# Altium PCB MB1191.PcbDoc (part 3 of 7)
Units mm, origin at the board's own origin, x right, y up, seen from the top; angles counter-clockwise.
Board outline 130 x 80 mm, 8 copper layers (Top, F2, F3, F4, F5, F6, F7, Bottom), stack 1.115 mm thick; 360 components, 347 nets, 1451 pads, 1068 vias.

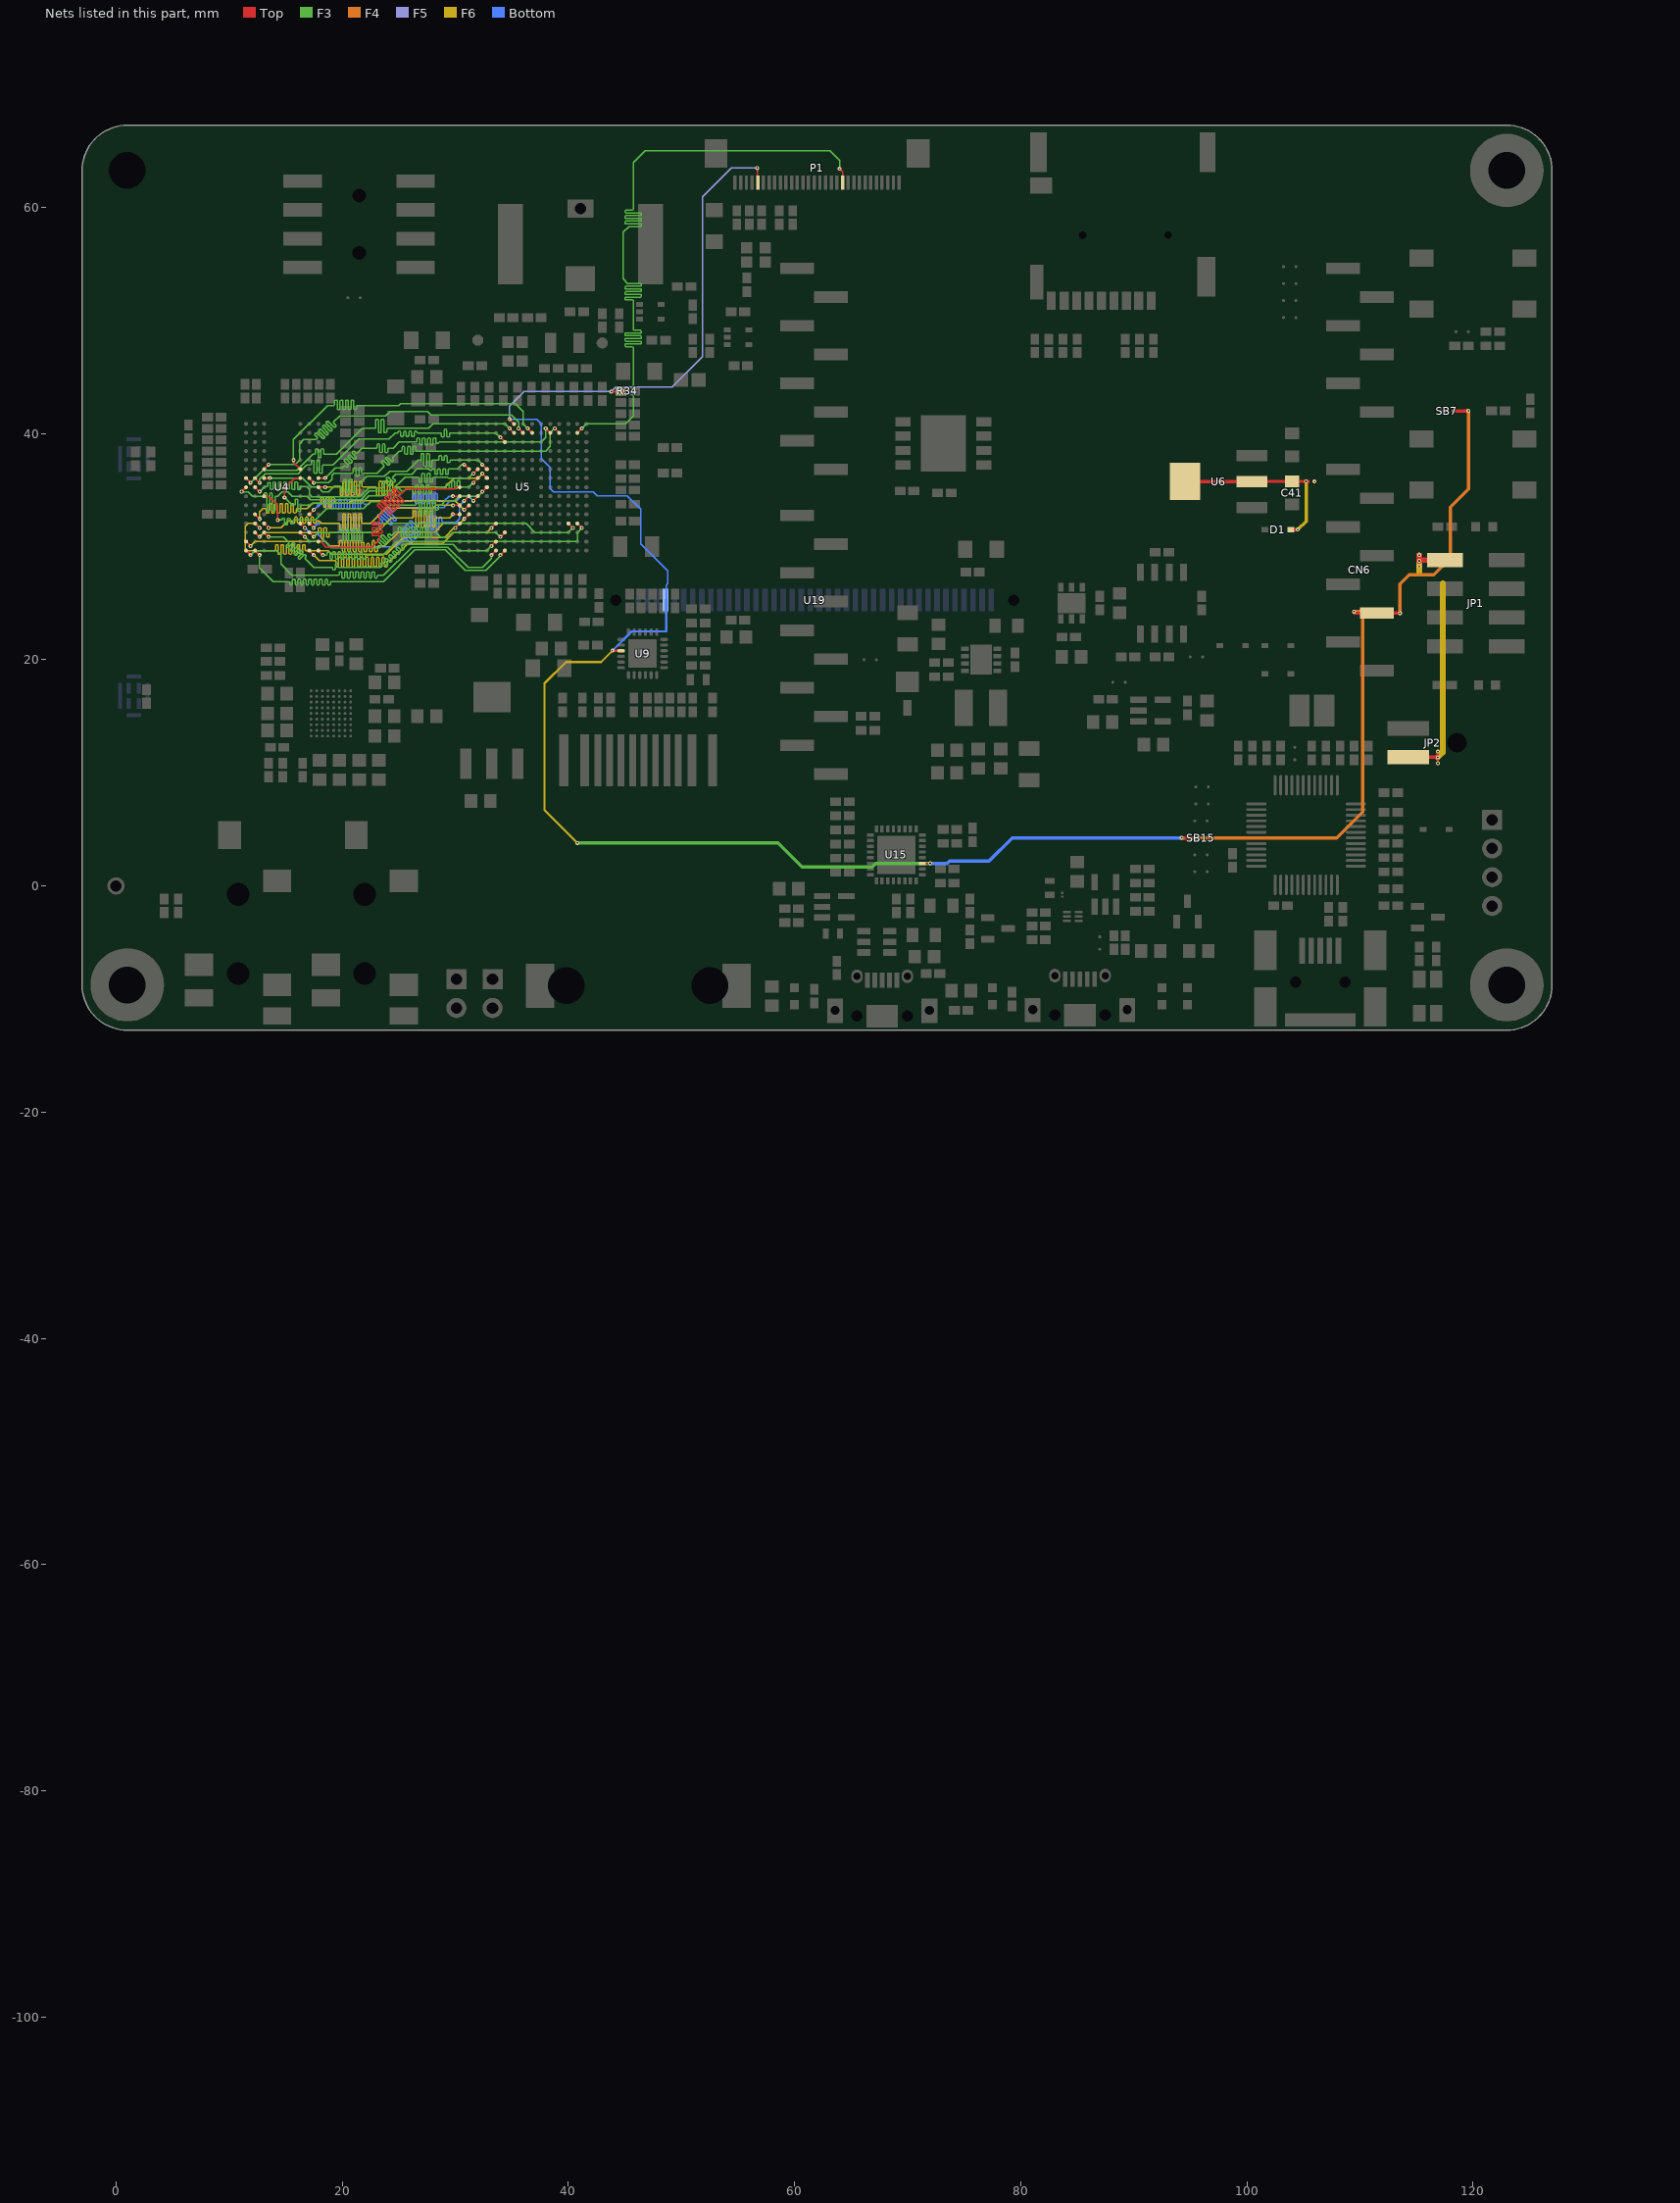
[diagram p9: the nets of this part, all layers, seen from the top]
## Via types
v1: diameter 0.35, hole 0.15, Top to Bottom, tented both sides, 1041 vias
v2: diameter 0.25, hole 0.1, Top to Bottom, tented both sides, 26 vias
v3: diameter 0.3, hole 0.1, Top to Bottom, tented both sides, 1 vias

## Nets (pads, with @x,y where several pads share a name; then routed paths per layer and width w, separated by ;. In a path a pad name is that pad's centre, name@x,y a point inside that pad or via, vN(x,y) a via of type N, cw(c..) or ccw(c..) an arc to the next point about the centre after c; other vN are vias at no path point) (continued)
DCMI_D7: P1.11 U5.B2 | length 74.9
  Top w0.12: U5.B2@40.8,40.05 v1(41.2,40.45) ; v1(64,63.4) 64.25,63.15 P1.11@64.25,62.175
  F3 w0.12: v1(41.2,40.45) 41.6,40.85 45.05,40.85 45.74,41.54 45.74,47.62 45.68,47.68 45.08,47.68 45.02,47.74 45.02,47.86 45.08,47.92 46.4,47.92 46.46,47.98 46.46,48.1 46.4,48.16 45.08,48.16 45.02,48.22 45.02,48.34 45.08,48.4 46.4,48.4 46.46,48.46 46.46,48.58 46.4,48.64 45.08,48.64 45.02,48.7 45.02,48.82 45.08,48.88 46.4,48.88 46.46,48.94 46.46,49.06 46.4,49.12 45.8,49.12 45.74,49.18 45.74,51.76 45.68,51.82 45.08,51.82 45.02,51.88 45.02,52 45.08,52.06 46.4,52.06 46.46,52.12 46.46,52.24 46.4,52.3 45.08,52.3 45.02,52.36 45.02,52.48 45.08,52.54 46.4,52.54 46.46,52.6 46.46,52.72 46.4,52.78 45.08,52.78 45.02,52.84 45.02,52.96 45.08,53.02 46.4,53.02 46.46,53.08 46.46,53.2 46.4,53.26 45.25,53.26 44.84,53.67 44.84,57.79 45.35,58.3 46.4,58.3 46.46,58.36 46.46,58.48 46.4,58.54 45.08,58.54 45.02,58.6 45.02,58.72 45.08,58.78 46.4,58.78 46.46,58.84 46.46,58.96 46.4,59.02 45.08,59.02 45.02,59.08 45.02,59.2 45.08,59.26 46.4,59.26 46.46,59.32 46.46,59.44 46.4,59.5 45.08,59.5 45.02,59.56 45.02,59.68 45.08,59.74 45.68,59.74 45.74,59.8 45.74,63.96 46.78,65 63.15,65 64,64.15 v1(64,63.4)
DCMI_NRST: CN6.3 P1.26 R34.1 SB7.1 SB15.2 U5.J1 U9.15 U15.27 U19.37 | length 221.2
  Top w0.12: v1(34.8,41.25) U5.J1@35.2,40.85 ; v1(56.71,63.47) 56.71,62.175 P1.26@56.75,62.175 ; U15.27@71.3,2 v1(72,2)
  Top w0.2: v1(43.8,43.7) 44.65,43.7 R34.1@44.65,43.75 ; v1(43.9,20.8) 43.9,20.789 U9.15@44.672,20.789
  Top w0.3: v1(94.25,4.25) SB15.2@95.4,4.25 ; v1(109.5,24.25) 109.5,24.12 CN6.3@111.5,24.12 113.57,24.12 v1(113.55,24.1) ; SB7.1@118.25,42 v1(119.6,42)
  F3 w0.3: v1(40.8,3.8) 58.55,3.8 60.68,1.67 66.87,1.67 67.2,2 v1(72,2)
  F4 w0.3: v1(94.25,4.25) 107.95,4.25 110.25,6.55 110.25,24.25 v1(109.5,24.25) ; v1(113.55,24.1) 113.55,26.7 114.35,27.5 116.55,27.5 118,28.95 118,33.5 119.6,35.1 v1(119.6,42)
  F5 w0.12: v1(34.8,41.25) 34.8,42.41 36.09,43.7 v1(43.8,43.7) 44.2,44.1 49.2,44.1 51.88,46.78 51.88,60.93 54.42,63.47 v1(56.71,63.47)
  F6 w0.2: v1(40.8,3.8) 37.9,6.7 37.9,17.9 39.8,19.8 42.9,19.8 v1(43.9,20.8)
  Bottom w0.12: v1(34.8,41.25) 37.2,41.25 37.6,40.85 37.6,37.8 38.4,37 38.4,35.15 38.7,34.85 42.2,34.85 42.55,34.5 45.2,34.5 46.4,33.3 46.4,30.25 48.804,27.846 48.804,27.148 ; U19.37@48.6,25.25 48.65,25.3 48.65,25.346 48.65,26.575 48.805,26.73 48.805,27.147
  Bottom w0.2: v1(43.9,20.8) 45.6,22.5 48.65,22.5 U19.37@48.65,25.3
  Bottom w0.3: v1(72,2) 73.5,2 73.7,2.2 77.2,2.2 79.25,4.25 v1(94.25,4.25)
E5V: C41.2 D1.1 JP1.1 JP2.2 U6.2 U6.4 | length 39.4
  Top w0.2: v1(116.89,11.375) v1@116.89,11.385 ; v1(116.9,11.875) 116.89,11.875 v1@116.89,11.385 ; v1(116.91,10.845) 116.91,11.385 v1@116.89,11.385
  Top w0.3: U6.4@94.55,35.75 U6.2@100.45,35.75 100.45,35.766 C41.2@104,35.766 v1(105.25,35.766) 105.434,35.766 ; D1.1@103.893,31.5 v1(104.5,31.5) ; 105.45,35.75 105.434,35.766 ; 105.45,35.766 105.434,35.766 ; JP2.2@114.3,11.385 v1@116.89,11.385
  Top w0.5: v1(115.25,28.75) 115.25,28.81 JP1.1@117.52,28.81 ; 115.25,29 v1(115.25,29.25)
  F6 w0.3: v1(104.5,31.5) 105.25,32.25 v1(105.25,35.766)
  F6 w0.5: 115.25,27.75 v1(115.25,28.25) v1(115.25,28.75) v1(115.25,29.25) ; v1(116.89,11.375) 117.325,11.81 117.325,26.75
  other v1: 106,35.75
FMC_A0: U4.G8 U5.D2 | length 33
  Top w0.12: U4.G8@17.1,36.05 v1(17.5,35.65) ; v1(38.8,40.45) U5.D2@39.2,40.05
  F3 w0.12: v1(17.5,35.65) 18.8,35.65 19.1,35.95 19.1,36.3 19.3,36.5 20.93,36.5 20.99,36.56 20.99,36.9 21.05,36.96 21.17,36.96 21.23,36.9 21.23,36.26 21.29,36.2 21.41,36.2 21.47,36.26 21.47,36.9 21.53,36.96 21.65,36.96 21.71,36.9 21.71,36.56 21.77,36.5 23.11,36.5 23.709,37.099 23.709,37.184 23.472,37.42 23.472,37.505 23.557,37.59 23.642,37.59 24.033,37.198 24.118,37.198 24.203,37.283 24.203,37.368 23.811,37.76 23.811,37.845 23.896,37.93 23.981,37.93 24.373,37.538 24.458,37.538 24.542,37.623 24.542,37.708 24.472,37.778 24.472,37.862 25.06,38.45 25.24,38.45 25.3,38.51 25.3,38.79 25.36,38.85 25.48,38.85 25.54,38.79 25.54,38.21 25.6,38.15 25.72,38.15 25.78,38.21 25.78,38.79 25.84,38.85 25.96,38.85 26.02,38.79 26.02,38.21 26.08,38.15 26.2,38.15 26.26,38.21 26.26,38.79 26.32,38.85 26.44,38.85 26.5,38.79 26.5,38.51 26.56,38.45 38,38.45 38.4,38.85 38.4,40.05 v1(38.8,40.45)
FMC_A1: U4.G9 U5.E2 | length 33.1
  Top w0.12: U4.G9@17.9,36.05 v1(18.5,36.05) ; v1(38,40.45) U5.E2@38.4,40.05
  F3 w0.12: v1(18.5,36.05) 19.4,36.95 20.01,36.95 20.206,37.146 20.291,37.146 20.387,37.051 20.472,37.051 20.557,37.136 20.557,37.221 20.198,37.579 20.198,37.664 20.283,37.748 20.368,37.748 20.726,37.39 20.811,37.39 20.896,37.475 20.896,37.56 20.538,37.918 20.538,38.003 20.623,38.088 20.708,38.088 21.066,37.73 21.15,37.73 21.235,37.815 21.235,37.9 20.877,38.258 20.877,38.342 20.962,38.427 21.047,38.427 21.225,38.25 21.31,38.25 21.76,38.7 23.02,38.7 23.08,38.76 23.08,39 23.14,39.06 23.26,39.06 23.32,39 23.32,38.35 23.38,38.29 23.5,38.29 23.56,38.35 23.56,39 23.62,39.06 23.74,39.06 23.8,39 23.8,38.35 23.86,38.29 23.98,38.29 24.04,38.35 24.04,38.64 24.1,38.7 24.51,38.7 25.06,39.25 26.55,39.25 26.61,39.31 26.61,39.56 26.67,39.62 26.79,39.62 26.85,39.56 26.85,39.05 26.91,38.99 27.03,38.99 27.09,39.05 27.09,39.56 27.15,39.62 27.27,39.62 27.33,39.56 27.33,39.05 27.39,38.99 27.51,38.99 27.57,39.05 27.57,39.56 27.63,39.62 27.75,39.62 27.81,39.56 27.81,39.05 27.87,38.99 27.99,38.99 28.05,39.05 28.05,39.56 28.11,39.62 28.23,39.62 28.29,39.56 28.29,39.18 28.35,39.12 28.47,39.12 28.53,39.18 28.53,39.19 28.59,39.25 37.6,39.25 38,39.65 v1(38,40.45)
FMC_A2: U4.F7 U5.G2 | length 33.1
  Top w0.12: v1(15.7,37.65) 15.7,37.45 U4.F7@16.3,36.85 ; v1(36.4,40.45) U5.G2@36.8,40.05
  F3 w0.12: v1(15.7,37.65) 15.7,39.45 18.72,42.47 19.28,42.47 19.34,42.53 19.34,42.88 19.4,42.94 19.52,42.94 19.58,42.88 19.58,42.16 19.64,42.1 19.76,42.1 19.82,42.16 19.82,42.88 19.88,42.94 20,42.94 20.06,42.88 20.06,42.16 20.12,42.1 20.24,42.1 20.3,42.16 20.3,42.88 20.36,42.94 20.48,42.94 20.54,42.88 20.54,42.16 20.6,42.1 20.72,42.1 20.78,42.16 20.78,42.88 20.84,42.94 20.96,42.94 21.02,42.88 21.02,42.16 21.08,42.1 21.2,42.1 21.26,42.16 21.26,42.41 21.32,42.47 24.98,42.47 25.16,42.65 35.31,42.65 36,41.96 36,40.85 v1(36.4,40.45)
FMC_A3: U4.F3 U5.H2 | length 33.1
  Top w0.12: U4.F3@13.1,36.85 v1(13.5,37.25) ; v1(35.6,40.45) U5.H2@36,40.05
  F3 w0.12: v1(13.5,37.25) 15.85,37.25 16.25,37.65 16.25,39.1 16.6,39.45 17.68,39.45 17.807,39.577 17.807,39.662 17.587,39.883 17.587,39.967 17.672,40.052 17.757,40.052 18.269,39.539 18.354,39.539 18.439,39.624 18.439,39.709 17.926,40.222 17.926,40.307 18.011,40.392 18.096,40.392 18.609,39.879 18.694,39.879 18.779,39.964 18.779,40.049 18.266,40.561 18.266,40.646 18.351,40.731 18.435,40.731 18.948,40.218 19.033,40.218 19.118,40.303 19.118,40.388 18.605,40.901 18.605,40.986 18.69,41.071 18.775,41.071 19.288,40.558 19.373,40.558 19.457,40.643 19.457,40.727 19.25,40.935 19.25,41.02 19.78,41.55 23.85,41.55 24.25,41.95 27.55,41.95 27.85,41.65 34.95,41.65 35.6,41 v1(35.6,40.45)
FMC_A4: U4.G1 U5.J2 | length 33.1
  Top w0.12: U4.G1@11.5,36.05 v1(11.9,35.65) ; v1(34.8,40.45) U5.J2@35.2,40.05
  F3 w0.12: v1(11.9,35.65) 13,36.75 16,36.75 17.4,38.15 17.58,38.15 17.64,38.21 17.64,38.6 17.7,38.66 17.82,38.66 17.88,38.6 17.88,37.92 17.94,37.86 18.06,37.86 18.12,37.92 18.12,38.6 18.18,38.66 18.3,38.66 18.36,38.6 18.36,38.21 18.42,38.15 19.5,38.15 21.8,40.45 22.92,40.45 22.98,40.51 22.98,41.18 23.04,41.24 23.16,41.24 23.22,41.18 23.22,40.12 23.28,40.06 23.4,40.06 23.46,40.12 23.46,41.18 23.52,41.24 23.64,41.24 23.7,41.18 23.7,40.12 23.76,40.06 23.88,40.06 23.94,40.12 23.94,40.39 24,40.45 27.65,40.45 28.05,40.85 34.4,40.85 v1(34.8,40.45)
FMC_A5: U4.G2 U5.K3 | length 33
  Top w0.12: U4.G2@12.3,36.05 v1(12.7,35.65) ; v1(34,39.65) U5.K3@34.4,39.25
  F3 w0.12: v1(12.7,35.65) 12.7,35.95 13.2,36.45 16.1,36.45 16.85,37.2 17.22,37.2 17.28,37.26 17.28,37.56 17.34,37.62 17.46,37.62 17.52,37.56 17.52,36.54 17.58,36.48 17.7,36.48 17.76,36.54 17.76,37.56 17.82,37.62 17.94,37.62 18,37.56 18,36.54 18.06,36.48 18.18,36.48 18.24,36.54 18.24,37.14 18.3,37.2 19.2,37.2 21.5,39.5 24.15,39.5 24.7,40.05 24.88,40.05 24.94,40.11 24.94,40.13 25,40.19 25.12,40.19 25.18,40.13 25.18,39.8 25.24,39.74 25.36,39.74 25.42,39.8 25.42,40.13 25.48,40.19 25.6,40.19 25.66,40.13 25.66,39.8 25.72,39.74 25.84,39.74 25.9,39.8 25.9,40.13 25.96,40.19 26.08,40.19 26.14,40.13 26.14,39.8 26.2,39.74 26.32,39.74 26.38,39.8 26.38,40.13 26.44,40.19 26.56,40.19 26.62,40.13 26.62,40.11 26.68,40.05 28.72,40.05 28.78,39.99 28.78,39.74 28.84,39.68 28.96,39.68 29.02,39.74 29.02,40.3 29.08,40.36 29.2,40.36 29.26,40.3 29.26,39.74 29.32,39.68 29.44,39.68 29.5,39.74 29.5,39.99 29.56,40.05 33.6,40.05 v1(34,39.65)
FMC_A6: U4.G3 U5.M6 | length 33
  Top w0.12: U4.G3@13.1,36.05 v1(13.6,36.05) ; v1(32.4,37.25) U5.M6@32.8,36.85
  F3 w0.12: v1(13.6,36.05) 16.5,36.05 17.3,35.25 17.9,35.25 18.3,34.85 18.8,34.85 19.32,35.37 19.86,35.37 19.92,35.31 19.92,34.84 19.98,34.78 20.1,34.78 20.16,34.84 20.16,35.92 20.22,35.98 20.34,35.98 20.4,35.92 20.4,34.84 20.46,34.78 20.58,34.78 20.64,34.84 20.64,35.92 20.7,35.98 20.82,35.98 20.88,35.92 20.88,34.84 20.94,34.78 21.06,34.78 21.12,34.84 21.12,35.31 21.18,35.37 21.36,35.37 22.19,36.2 23.75,36.2 24.2,36.65 25.75,36.65 26.75,37.65 26.93,37.65 26.99,37.71 26.99,38.15 27.05,38.21 27.17,38.21 27.23,38.15 27.23,37.15 27.29,37.09 27.41,37.09 27.47,37.15 27.47,38.15 27.53,38.21 27.65,38.21 27.71,38.15 27.71,37.15 27.77,37.09 27.89,37.09 27.95,37.15 27.95,37.59 28.01,37.65 28.51,37.65 28.57,37.71 28.57,37.96 28.63,38.02 28.75,38.02 28.81,37.96 28.81,37.69 28.87,37.63 28.99,37.63 29.05,37.69 29.05,37.96 29.11,38.02 29.23,38.02 29.29,37.96 29.29,37.48 29.35,37.42 29.47,37.42 29.53,37.48 29.53,37.59 29.59,37.65 32,37.65 v1(32.4,37.25)
FMC_A7: U4.H1 U5.N6 | length 33
  Top w0.12: v1(11.1,34.85) U4.H1@11.5,35.25 ; v1(31.6,36.45) U5.N6@32,36.85
  F3 w0.12: v1(11.1,34.85) 11.7,34.85 12.1,34.45 13.04,34.45 13.1,34.51 13.1,34.67 13.16,34.73 13.28,34.73 13.34,34.67 13.34,33.21 13.4,33.15 13.52,33.15 13.58,33.21 13.58,34.67 13.64,34.73 13.76,34.73 13.82,34.67 13.82,33.21 13.88,33.15 14,33.15 14.06,33.21 14.06,34.39 14.12,34.45 14.3,34.45 14.7,34.85 15.2,34.85 15.6,34.45 16.9,34.45 17.2,34.15 21.65,34.15 22.4,34.9 24.3,34.9 25.55,36.15 26.75,36.15 26.81,36.09 26.81,35.74 26.87,35.68 26.99,35.68 27.05,35.74 27.05,36.43 27.11,36.49 27.23,36.49 27.29,36.43 27.29,35.74 27.35,35.68 27.47,35.68 27.53,35.74 27.53,36.43 27.59,36.49 27.71,36.49 27.77,36.43 27.77,35.74 27.83,35.68 27.95,35.68 28.01,35.74 28.01,36.09 28.07,36.15 29.3,36.15 29.4,36.05 31.15,36.05 31.55,36.45 v1(31.6,36.45)
FMC_A8: U4.H2 U5.P6 | length 33.1
  Top w0.12: U4.H2@12.3,35.25 v1(12.7,34.85) ; v1(30.8,37.25) U5.P6@31.2,36.85
  F3 w0.12: v1(12.7,34.85) 13.17,35.32 13.35,35.32 13.41,35.38 13.41,35.61 13.47,35.67 13.59,35.67 13.65,35.61 13.65,35.1 13.71,35.04 13.83,35.04 13.89,35.1 13.89,35.65 13.95,35.71 14.07,35.71 14.13,35.65 14.13,35.1 14.19,35.04 14.31,35.04 14.37,35.1 14.37,35.65 14.43,35.71 14.55,35.71 14.61,35.65 14.61,35.15 14.67,35.09 14.79,35.09 14.85,35.15 14.85,35.65 14.91,35.71 15.03,35.71 15.09,35.65 15.09,35.15 15.15,35.09 15.27,35.09 15.33,35.15 15.33,35.65 15.39,35.71 15.51,35.71 15.57,35.65 15.57,35.1 15.63,35.04 15.75,35.04 15.81,35.1 15.81,35.65 15.87,35.71 15.99,35.71 16.05,35.65 16.05,35.1 16.11,35.04 16.23,35.04 16.29,35.1 16.29,35.26 16.35,35.32 16.83,35.32 17.1,35.05 17.1,34.65 17.35,34.4 21.55,34.4 22.35,35.2 23.55,35.2 23.737,35.387 23.737,35.472 23.59,35.62 23.59,35.704 23.675,35.789 23.76,35.789 24.188,35.36 24.273,35.36 24.358,35.445 24.358,35.53 23.931,35.957 23.931,36.042 24.016,36.127 24.101,36.127 24.528,35.7 24.613,35.7 24.698,35.785 24.698,35.869 24.501,36.066 24.501,36.151 24.75,36.4 26.15,36.4 26.6,36.85 27.65,36.85 27.77,36.73 27.89,36.73 28.01,36.85 28.13,36.85 28.19,36.79 28.19,36.45 28.25,36.39 28.37,36.39 28.43,36.45 28.43,36.79 28.49,36.85 28.61,36.85 28.67,36.79 28.67,36.45 28.73,36.39 28.85,36.39 28.91,36.45 28.91,36.79 28.97,36.85 29.09,36.85 29.15,36.79 29.15,36.45 29.21,36.39 29.33,36.39 29.39,36.45 29.39,36.79 29.45,36.85 30.2,36.85 30.6,37.25 v1(30.8,37.25)
FMC_A9: U4.J3 U5.M8 | length 33
  Top w0.12: U4.J3@13.1,34.45 13.5,34.45 14.3,33.65 v1(14.3,32.35) ; v1(32.4,34.85) U5.M8@32.8,35.25
  F3 w0.12: v1(14.3,32.35) 14.62,32.35 14.68,32.41 14.68,32.43 14.74,32.49 14.86,32.49 14.92,32.43 14.92,31.99 14.98,31.93 15.1,31.93 15.16,31.99 15.16,32.43 15.22,32.49 15.34,32.49 15.4,32.43 15.4,32.09 15.46,32.03 15.58,32.03 15.64,32.09 15.64,32.29 15.7,32.35 17.65,32.35 18.65,33.35 21.9,33.35 22.51,33.96 23.56,33.96 23.85,33.67 26.51,33.67 26.57,33.73 26.57,34.03 26.63,34.09 26.75,34.09 26.81,34.03 26.81,32.9 26.87,32.84 26.99,32.84 27.05,32.9 27.05,34.03 27.11,34.09 27.23,34.09 27.29,34.03 27.29,32.9 27.35,32.84 27.47,32.84 27.53,32.9 27.53,34.03 27.59,34.09 27.71,34.09 27.77,34.03 27.77,32.9 27.83,32.84 27.95,32.84 28.01,32.9 28.01,34.03 28.07,34.09 28.19,34.09 28.25,34.03 28.25,33.29 28.31,33.23 28.43,33.23 28.49,33.29 28.49,33.61 28.55,33.67 28.75,33.67 29.13,34.05 29.95,34.05 30.33,34.43 31.98,34.43 v1(32.4,34.85)
FMC_A10: U4.G7 U5.N7 | length 33
  Top w0.12: v1(14.9,34.35) 14.9,35.15 15.8,36.05 U4.G7@16.3,36.05 ; v1(31.6,35.65) U5.N7@32,36.05
  F3 w0.12: v1(14.9,34.35) 15.6,33.65 15.78,33.65 15.84,33.71 15.84,34.12 15.9,34.18 16.02,34.18 16.08,34.12 16.08,33.17 16.14,33.11 16.26,33.11 16.32,33.17 16.32,33.59 16.38,33.65 17.25,33.65 17.45,33.85 21.7,33.85 22.35,34.5 23.54,34.5 23.6,34.56 23.6,34.6 23.66,34.66 23.78,34.66 23.84,34.6 23.84,34.49 23.9,34.43 24.02,34.43 24.08,34.49 24.08,34.6 24.14,34.66 24.26,34.66 24.32,34.6 24.32,34.23 24.38,34.17 24.5,34.17 24.56,34.23 24.56,34.44 24.62,34.5 25.02,34.5 25.147,34.627 25.147,34.712 24.842,35.018 24.842,35.102 24.927,35.187 25.012,35.187 25.317,34.882 25.402,34.882 25.63,35.11 26.18,35.11 26.24,35.05 26.24,34.74 26.3,34.68 26.42,34.68 26.48,34.74 26.48,35.4 26.54,35.46 26.66,35.46 26.72,35.4 26.72,34.74 26.78,34.68 26.9,34.68 26.96,34.74 26.96,35.38 27.02,35.44 27.14,35.44 27.2,35.38 27.2,34.74 27.26,34.68 27.38,34.68 27.44,34.74 27.44,35.38 27.5,35.44 27.62,35.44 27.68,35.38 27.68,34.74 27.74,34.68 27.86,34.68 27.92,34.74 27.92,35.05 27.98,35.11 28.25,35.11 28.39,35.25 28.91,35.25 28.97,35.19 28.97,35.18 29.03,35.12 29.15,35.12 29.21,35.18 29.21,35.51 29.27,35.57 29.39,35.57 29.45,35.51 29.45,35.18 29.51,35.12 29.63,35.12 29.69,35.18 29.69,35.75 29.75,35.81 29.87,35.81 29.93,35.75 29.93,35.18 29.99,35.12 30.11,35.12 30.17,35.18 30.17,35.75 30.23,35.81 30.35,35.81 30.41,35.75 30.41,35.31 30.47,35.25 31.2,35.25 v1(31.6,35.65)
FMC_A11: U4.H9 U5.M7 | length 33.1
  Top w0.12: U4.H9@17.9,35.25 v1(18.5,35.25) ; v1(32.4,36.45) U5.M7@32.8,36.05
  F6 w0.12: v1(18.5,35.25) 19.78,35.25 19.84,35.19 19.84,34.59 19.9,34.53 20.02,34.53 20.08,34.59 20.08,35.69 20.14,35.75 20.26,35.75 20.32,35.69 20.32,34.59 20.38,34.53 20.5,34.53 20.56,34.59 20.56,35.69 20.62,35.75 20.74,35.75 20.8,35.69 20.8,34.59 20.86,34.53 20.98,34.53 21.04,34.59 21.04,35.69 21.1,35.75 21.22,35.75 21.28,35.69 21.28,34.59 21.34,34.53 21.46,34.53 21.52,34.59 21.52,35.69 21.58,35.75 21.7,35.75 21.76,35.69 21.76,35.31 21.82,35.25 22.97,35.25 23.03,35.19 23.03,34.59 23.09,34.53 23.21,34.53 23.27,34.59 23.27,35.72 23.33,35.78 23.45,35.78 23.51,35.72 23.51,34.59 23.57,34.53 23.69,34.53 23.75,34.59 23.75,35.72 23.81,35.78 23.93,35.78 23.99,35.72 23.99,34.59 24.05,34.53 24.17,34.53 24.23,34.59 24.23,35.72 24.29,35.78 24.41,35.78 24.47,35.72 24.47,34.59 24.53,34.53 24.65,34.53 24.71,34.59 24.71,35.19 24.77,35.25 29.1,35.25 29.9,36.05 32,36.05 v1(32.4,36.45)
FMC_D0: U4.R8 U5.L12 | length 33
  Top w0.12: U4.R8@17.1,29.65 v1(17.5,29.25) ; v1(33.2,31.65) U5.L12@33.6,32.05
  F6 w0.12: v1(17.5,29.25) 18,28.75 19.38,28.75 19.44,28.69 19.44,28.28 19.5,28.22 19.62,28.22 19.68,28.28 19.68,29 19.74,29.06 19.86,29.06 19.92,29 19.92,28.28 19.98,28.22 20.1,28.22 20.16,28.28 20.16,29 20.22,29.06 20.34,29.06 20.4,29 20.4,28.28 20.46,28.22 20.58,28.22 20.64,28.28 20.64,29 20.7,29.06 20.82,29.06 20.88,29 20.88,28.28 20.94,28.22 21.06,28.22 21.12,28.28 21.12,29 21.18,29.06 21.3,29.06 21.36,29 21.36,28.28 21.42,28.22 21.54,28.22 21.6,28.28 21.6,29 21.66,29.06 21.78,29.06 21.84,29 21.84,28.28 21.9,28.22 22.02,28.22 22.08,28.28 22.08,29 22.14,29.06 22.26,29.06 22.32,29 22.32,28.28 22.38,28.22 22.5,28.22 22.56,28.28 22.56,29 22.62,29.06 22.74,29.06 22.8,29 22.8,28.28 22.86,28.22 22.98,28.22 23.04,28.28 23.04,29 23.1,29.06 23.22,29.06 23.28,29 23.28,28.28 23.34,28.22 23.46,28.22 23.52,28.28 23.52,29 23.58,29.06 23.7,29.06 23.76,29 23.76,28.28 23.82,28.22 23.94,28.22 24,28.28 24,28.69 24.06,28.75 24.28,28.75 25.82,30.29 28.89,30.29 29.85,31.25 32.8,31.25 v1(33.2,31.65)
FMC_D1: U4.N7 U5.K13 | length 33
  Top w0.12: U4.N7@16.3,31.25 v1(16.7,30.85) ; v1(34,30.85) U5.K13@34.4,31.25
  F3 w0.12: v1(16.7,30.85) 17.1,30.45 18.5,30.45 19.04,29.91 23.33,29.91 23.48,30.06 23.48,30.144 23.117,30.507 23.117,30.592 23.202,30.677 23.287,30.677 23.765,30.199 23.85,30.199 23.935,30.283 23.935,30.368 23.456,30.847 23.456,30.931 23.541,31.016 23.626,31.016 24.104,30.538 24.189,30.538 24.274,30.623 24.274,30.708 24.052,30.93 24.052,31.015 24.137,31.099 24.222,31.099 24.328,30.993 24.413,30.993 24.71,31.29 24.91,31.29 24.97,31.35 24.97,31.65 25.03,31.71 25.15,31.71 25.21,31.65 25.21,30.88 25.27,30.82 25.39,30.82 25.45,30.88 25.45,31.65 25.51,31.71 25.63,31.71 25.69,31.65 25.69,30.88 25.75,30.82 25.87,30.82 25.93,30.88 25.93,31.65 25.99,31.71 26.11,31.71 26.17,31.65 26.17,30.88 26.23,30.82 26.35,30.82 26.41,30.88 26.41,31.65 26.47,31.71 26.59,31.71 26.65,31.65 26.65,30.88 26.71,30.82 26.83,30.82 26.89,30.88 26.89,31.65 26.95,31.71 27.07,31.71 27.13,31.65 27.13,30.88 27.19,30.82 27.31,30.82 27.37,30.88 27.37,31.65 27.43,31.71 27.55,31.71 27.61,31.65 27.61,30.88 27.67,30.82 27.79,30.82 27.85,30.88 27.85,31.23 27.91,31.29 28.23,31.29 28.72,30.8 29.3,30.8 29.75,31.25 33.6,31.25 v1(34,30.85)
FMC_D2: U4.R9 U5.B12 | length 33.1
  Top w0.12: U4.R9@17.9,29.65 v1(18.3,29.25) ; U5.B12@40.8,32.05 v1(41.2,31.65)
  F3 w0.12: v1(18.3,29.25) 18.62,29.25 18.68,29.31 18.68,29.47 18.74,29.53 18.86,29.53 18.92,29.47 18.92,28.97 18.98,28.91 19.1,28.91 19.16,28.97 19.16,29.47 19.22,29.53 19.34,29.53 19.4,29.47 19.4,28.97 19.46,28.91 19.58,28.91 19.64,28.97 19.64,29.47 19.7,29.53 19.82,29.53 19.88,29.47 19.88,28.97 19.94,28.91 20.06,28.91 20.12,28.97 20.12,29.47 20.18,29.53 20.3,29.53 20.36,29.47 20.36,28.97 20.42,28.91 20.54,28.91 20.6,28.97 20.6,29.47 20.66,29.53 20.78,29.53 20.84,29.47 20.84,28.97 20.9,28.91 21.02,28.91 21.08,28.97 21.08,29.47 21.14,29.53 21.26,29.53 21.32,29.47 21.32,28.97 21.38,28.91 21.5,28.91 21.56,28.97 21.56,29.47 21.62,29.53 21.74,29.53 21.8,29.47 21.8,28.97 21.86,28.91 21.98,28.91 22.04,28.97 22.04,29.19 22.1,29.25 23.62,29.25 24.82,30.45 40.75,30.45 40.8,30.5 40.8,31.25 v1(41.2,31.65)
FMC_D3: U4.N8 U5.C12 | length 33
  Top w0.12: U4.N8@17.1,31.25 v1(17.5,30.85) ; U5.C12@40,32.05 v1(40.4,31.65)
  F3 w0.12: v1(17.5,30.85) 17.9,31.25 19.81,31.25 19.87,31.31 19.87,31.51 19.93,31.57 20.05,31.57 20.11,31.51 20.11,30.55 20.17,30.49 20.29,30.49 20.35,30.55 20.35,31.51 20.41,31.57 20.53,31.57 20.59,31.51 20.59,30.55 20.65,30.49 20.77,30.49 20.83,30.55 20.83,31.51 20.89,31.57 21.01,31.57 21.07,31.51 21.07,30.55 21.13,30.49 21.25,30.49 21.31,30.55 21.31,31.51 21.37,31.57 21.49,31.57 21.55,31.51 21.55,30.55 21.61,30.49 21.73,30.49 21.79,30.55 21.79,31.19 21.85,31.25 22.76,31.25 23.56,32.05 36.25,32.05 37.05,31.25 40,31.25 v1(40.4,31.65)
FMC_D4: U4.P9 U5.R8 | length 33.1
  Top w0.12: U4.P9@17.9,30.45 18.1,30.45 18.6,29.95 22.6,29.95 23.3,30.65 23.3,30.9 23.24,30.96 22.72,30.96 22.66,31.02 22.66,31.14 22.72,31.2 23.51,31.2 23.57,31.26 23.57,31.38 23.51,31.44 22.72,31.44 22.66,31.5 22.66,31.62 22.72,31.68 23.52,31.68 23.58,31.74 23.58,31.86 23.52,31.92 22.72,31.92 22.66,31.98 22.66,32.1 22.72,32.16 23.24,32.16 23.3,32.22 23.3,32.75 23.598,33.048 23.598,33.133 23.122,33.609 23.122,33.694 23.207,33.778 23.291,33.778 24.225,32.845 24.31,32.845 24.395,32.93 24.395,33.015 23.461,33.948 23.461,34.033 23.546,34.118 23.631,34.118 24.564,33.185 24.649,33.185 24.734,33.269 24.734,33.354 23.801,34.288 23.801,34.372 23.885,34.457 23.97,34.457 24.904,33.524 24.988,33.524 25.073,33.609 25.073,33.694 24.14,34.627 24.14,34.712 24.225,34.797 24.31,34.797 25.243,33.863 25.328,33.863 25.413,33.948 25.413,34.033 24.479,34.966 24.479,35.051 24.564,35.136 24.649,35.136 25.125,34.66 25.21,34.66 25.65,35.1 29.95,35.1 30.1,35.25 U5.R8@30.4,35.25
FMC_D5: U4.M8 U5.N9 | length 33.1
  Top w0.12: U4.M8@17.1,32.05 17.483,31.667 v1(17.466,31.65) ; v1(31.6,34.05) U5.N9@32,34.45
  Bottom w0.12: v1(17.466,31.65) 17.866,32.05 19.74,32.05 19.8,31.99 19.8,31.39 19.86,31.33 19.98,31.33 20.04,31.39 20.04,32.56 20.1,32.62 20.22,32.62 20.28,32.56 20.28,31.39 20.34,31.33 20.46,31.33 20.52,31.39 20.52,32.56 20.58,32.62 20.7,32.62 20.76,32.56 20.76,31.39 20.82,31.33 20.94,31.33 21,31.39 21,32.56 21.06,32.62 21.18,32.62 21.24,32.56 21.24,31.39 21.3,31.33 21.42,31.33 21.48,31.39 21.48,32.56 21.54,32.62 21.66,32.62 21.72,32.56 21.72,32.11 21.78,32.05 23.45,32.05 23.58,32.18 23.58,32.265 23.156,32.689 23.156,32.774 23.241,32.859 23.326,32.859 24.259,31.926 24.344,31.926 24.429,32.01 24.429,32.095 23.495,33.029 23.495,33.114 23.58,33.198 23.665,33.198 24.598,32.265 24.683,32.265 24.768,32.35 24.768,32.435 23.835,33.368 23.835,33.453 23.92,33.538 24.004,33.538 24.429,33.114 24.514,33.114 24.86,33.46 28.97,33.46 29.56,34.05 30.1,34.05 30.5,34.45 31.2,34.45 v1(31.6,34.05)
FMC_D6: U4.M7 U5.P9 | length 33
  Top w0.12: U4.M7@16.3,32.05 v1(16.7,31.65) ; v1(30.8,34.05) U5.P9@31.2,34.45
  Bottom w0.12: v1(16.7,31.65) 17.1,31.25 17.7,31.25 18.97,29.98 24.75,29.98 25.53,30.76 25.615,30.76 26.039,30.336 26.124,30.336 26.209,30.42 26.209,30.505 25.275,31.439 25.275,31.524 25.36,31.608 25.445,31.608 26.378,30.675 26.463,30.675 26.548,30.76 26.548,30.845 25.615,31.778 25.615,31.863 25.7,31.948 25.784,31.948 26.718,31.014 26.803,31.014 26.888,31.099 26.888,31.184 25.954,32.118 25.954,32.202 26.039,32.287 26.124,32.287 26.548,31.863 26.633,31.863 26.93,32.16 27.3,32.16 27.36,32.1 27.36,31.55 27.42,31.49 27.54,31.49 27.6,31.55 27.6,32.63 27.66,32.69 27.78,32.69 27.84,32.63 27.84,31.55 27.9,31.49 28.02,31.49 28.08,31.55 28.08,32.63 28.14,32.69 28.26,32.69 28.32,32.63 28.32,31.55 28.38,31.49 28.5,31.49 28.56,31.55 28.56,32.56 28.62,32.62 28.74,32.62 28.8,32.56 28.8,32.22 28.86,32.16 30.09,32.16 30.37,32.44 30.37,33.62 v1(30.8,34.05)
FMC_D7: U4.L8 U5.R9 | length 33.1
  Top w0.12: U4.L8@17.1,32.85 v1(17.5,33.25) ; v1(29.8,34.45) U5.R9@30.4,34.45
  Bottom w0.12: v1(17.5,33.25) 18.01,33.76 18.21,33.76 18.27,33.82 18.27,34.11 18.33,34.17 18.45,34.17 18.51,34.11 18.51,33.42 18.57,33.36 18.69,33.36 18.75,33.42 18.75,34.11 18.81,34.17 18.93,34.17 18.99,34.11 18.99,33.42 19.05,33.36 19.17,33.36 19.23,33.42 19.23,34.11 19.29,34.17 19.41,34.17 19.47,34.11 19.47,33.42 19.53,33.36 19.65,33.36 19.71,33.42 19.71,34.11 19.77,34.17 19.89,34.17 19.95,34.11 19.95,33.42 20.01,33.36 20.13,33.36 20.19,33.42 20.19,34.11 20.25,34.17 20.37,34.17 20.43,34.11 20.43,33.42 20.49,33.36 20.61,33.36 20.67,33.42 20.67,34.11 20.73,34.17 20.85,34.17 20.91,34.11 20.91,33.42 20.97,33.36 21.09,33.36 21.15,33.42 21.15,34.11 21.21,34.17 21.33,34.17 21.39,34.11 21.39,33.42 21.45,33.36 21.57,33.36 21.63,33.42 21.63,34.11 21.69,34.17 21.81,34.17 21.87,34.11 21.87,33.82 21.93,33.76 22.36,33.76 22.6,34 26.19,34 26.25,34.06 26.25,34.66 26.31,34.72 26.43,34.72 26.49,34.66 26.49,33.86 26.55,33.8 26.67,33.8 26.73,33.86 26.73,34.66 26.79,34.72 26.91,34.72 26.97,34.66 26.97,33.86 27.03,33.8 27.15,33.8 27.21,33.86 27.21,34.66 27.27,34.72 27.39,34.72 27.45,34.66 27.45,33.86 27.51,33.8 27.63,33.8 27.69,33.86 27.69,34.66 27.75,34.72 27.87,34.72 27.93,34.66 27.93,33.86 27.99,33.8 28.11,33.8 28.17,33.86 28.17,34.66 28.23,34.72 28.35,34.72 28.41,34.66 28.41,34.06 28.47,34 29,34 29.45,34.45 v1(29.8,34.45)
FMC_D8: U4.L2 U5.P10 | length 33.1
  Top w0.12: U4.L2@12.3,32.85 v1(12.7,32.45) ; v1(30.8,33.25) U5.P10@31.2,33.65
  F6 w0.12: v1(12.7,32.45) 12.7,33.04 13.01,33.35 13.23,33.35 13.29,33.29 13.29,33.01 13.35,32.95 13.47,32.95 13.53,33.01 13.53,33.74 13.59,33.8 13.71,33.8 13.77,33.74 13.77,33.01 13.83,32.95 13.95,32.95 14.01,33.01 14.01,33.74 14.07,33.8 14.19,33.8 14.25,33.74 14.25,33.01 14.31,32.95 14.43,32.95 14.49,33.01 14.49,33.74 14.55,33.8 14.67,33.8 14.73,33.74 14.73,33.01 14.79,32.95 14.91,32.95 14.97,33.01 14.97,33.74 15.03,33.8 15.15,33.8 15.21,33.74 15.21,33.01 15.27,32.95 15.39,32.95 15.45,33.01 15.45,33.74 15.51,33.8 15.63,33.8 15.69,33.74 15.69,33.01 15.75,32.95 15.87,32.95 15.93,33.01 15.93,33.29 15.99,33.35 16.89,33.35 17.37,33.83 18.06,33.83 18.12,33.89 18.12,34.28 18.18,34.34 18.3,34.34 18.36,34.28 18.36,33.54 18.42,33.48 18.54,33.48 18.6,33.54 18.6,34.28 18.66,34.34 18.78,34.34 18.84,34.28 18.84,33.54 18.9,33.48 19.02,33.48 19.08,33.54 19.08,34.28 19.14,34.34 19.26,34.34 19.32,34.28 19.32,33.89 19.38,33.83 20.61,33.83 20.83,34.05 30,34.05 v1(30.8,33.25)
FMC_D9: U4.M3 U5.R10 | length 33
  Top w0.12: U4.M3@13.1,32.05 v1(13.5,31.65) ; v1(29.8,33.65) U5.R10@30.4,33.65
  F6 w0.12: v1(13.5,31.65) 14.6,31.65 15.23,32.28 15.49,32.28 15.55,32.22 15.55,32.13 15.61,32.07 15.73,32.07 15.79,32.13 15.79,32.55 15.85,32.61 15.97,32.61 16.03,32.55 16.03,32.13 16.09,32.07 16.21,32.07 16.27,32.13 16.27,32.55 16.33,32.61 16.45,32.61 16.51,32.55 16.51,32.13 16.57,32.07 16.69,32.07 16.75,32.13 16.75,32.55 16.81,32.61 16.93,32.61 16.99,32.55 16.99,32.13 17.05,32.07 17.17,32.07 17.23,32.13 17.23,32.55 17.29,32.61 17.41,32.61 17.47,32.55 17.47,32.13 17.53,32.07 17.65,32.07 17.71,32.13 17.71,32.22 17.77,32.28 17.95,32.28 18.18,32.05 19.74,32.05 19.8,31.99 19.8,31.55 19.86,31.49 19.98,31.49 20.04,31.55 20.04,32.82 20.1,32.88 20.22,32.88 20.28,32.82 20.28,31.55 20.34,31.49 20.46,31.49 20.52,31.55 20.52,32.82 20.58,32.88 20.7,32.88 20.76,32.82 20.76,31.55 20.82,31.49 20.94,31.49 21,31.55 21,32.82 21.06,32.88 21.18,32.88 21.24,32.82 21.24,31.55 21.3,31.49 21.42,31.49 21.48,31.55 21.48,32.82 21.54,32.88 21.66,32.88 21.72,32.82 21.72,32.11 21.78,32.05 22.53,32.05 23.877,33.397 28.047,33.397 28.3,33.65 v1(29.8,33.65)
FMC_D10: U4.M2 U5.R12 | length 33.1
  Top w0.12: U4.M2@12.3,32.05 v1(12.7,31.65) ; v1(30,31.65) U5.R12@30.4,32.05
  F6 w0.12: v1(12.7,31.65) 12.3,32.05 11.7,32.05 11.45,31.8 11.45,29.8 11.6,29.65 14.04,29.65 14.1,29.71 14.1,30.11 14.16,30.17 14.28,30.17 14.34,30.11 14.34,29.38 14.4,29.32 14.52,29.32 14.58,29.38 14.58,30.11 14.64,30.17 14.76,30.17 14.82,30.11 14.82,29.38 14.88,29.32 15,29.32 15.06,29.38 15.06,30.11 15.12,30.17 15.24,30.17 15.3,30.11 15.3,29.38 15.36,29.32 15.48,29.32 15.54,29.38 15.54,30.11 15.6,30.17 15.72,30.17 15.78,30.11 15.78,29.38 15.84,29.32 15.96,29.32 16.02,29.38 16.02,30.11 16.08,30.17 16.2,30.17 16.26,30.11 16.26,29.38 16.32,29.32 16.44,29.32 16.5,29.38 16.5,30.11 16.56,30.17 16.68,30.17 16.74,30.11 16.74,29.71 16.8,29.65 18.74,29.65 19.07,29.32 23.9,29.32 25.4,30.82 29.07,30.82 29.9,31.65 v1(30,31.65)
FMC_D11: U4.P1 U5.P11 | length 33.1
  Top w0.12: U4.P1@11.5,30.45 v1(11.9,30.05) ; v1(30.8,32.45) U5.P11@31.2,32.85
  F6 w0.12: v1(11.9,30.05) 12.3,30.45 18.5,30.45 18.9,30.05 19.71,30.05 19.77,30.11 19.77,30.47 19.83,30.53 19.95,30.53 20.01,30.47 20.01,29.62 20.07,29.56 20.19,29.56 20.25,29.62 20.25,30.47 20.31,30.53 20.43,30.53 20.49,30.47 20.49,29.62 20.55,29.56 20.67,29.56 20.73,29.62 20.73,30.47 20.79,30.53 20.91,30.53 20.97,30.47 20.97,29.62 21.03,29.56 21.15,29.56 21.21,29.62 21.21,30.47 21.27,30.53 21.39,30.53 21.45,30.47 21.45,29.62 21.51,29.56 21.63,29.56 21.69,29.62 21.69,30.32 21.75,30.38 21.87,30.38 21.93,30.32 21.93,29.62 21.99,29.56 22.11,29.56 22.17,29.62 22.17,30.21 22.23,30.27 22.35,30.27 22.41,30.21 22.41,29.62 22.47,29.56 22.59,29.56 22.65,29.62 22.65,30.47 22.71,30.53 22.83,30.53 22.89,30.47 22.89,29.62 22.95,29.56 23.07,29.56 23.13,29.62 23.13,29.99 23.19,30.05 23.73,30.05 24.98,31.3 28.21,31.3 28.96,32.05 30.4,32.05 v1(30.8,32.45)
FMC_D12: U4.N2 U5.R11 | length 33.1
  Top w0.12: U4.N2@12.3,31.25 v1(12.7,30.85) ; v1(29.8,32.85) U5.R11@30.4,32.85
  F6 w0.12: v1(12.7,30.85) 13.1,31.25 17.84,31.25 17.9,31.31 17.9,31.61 17.96,31.67 18.08,31.67 18.14,31.61 18.14,30.75 18.2,30.69 18.32,30.69 18.38,30.75 18.38,31.61 18.44,31.67 18.56,31.67 18.62,31.61 18.62,30.91 18.68,30.85 18.8,30.85 18.86,30.91 18.86,31.19 18.92,31.25 23.05,31.25 24.35,32.55 26.23,32.55 26.29,32.61 26.29,33.09 26.35,33.15 26.47,33.15 26.53,33.09 26.53,31.79 26.59,31.73 26.71,31.73 26.77,31.79 26.77,33.09 26.83,33.15 26.95,33.15 27.01,33.09 27.01,31.79 27.07,31.73 27.19,31.73 27.25,31.79 27.25,33.09 27.31,33.15 27.43,33.15 27.49,33.09 27.49,31.79 27.55,31.73 27.67,31.73 27.73,31.79 27.73,33.09 27.79,33.15 27.91,33.15 27.97,33.09 27.97,31.79 28.03,31.73 28.15,31.73 28.21,31.79 28.21,32.49 28.27,32.55 29.5,32.55 v1(29.8,32.85)
FMC_D13: U4.R1 U5.L15 | length 33.2
  Top w0.12: U4.R1@11.5,29.65 v1(11.9,29.25) ; v1(33.2,29.25) U5.L15@33.6,29.65
  F3 w0.12: v1(11.9,29.25) 12.3,29.65 14.22,29.65 14.58,29.29 14.58,28.45 15.56,27.47 19.69,27.47 19.75,27.53 19.75,27.72 19.81,27.78 19.93,27.78 19.99,27.72 19.99,27.28 20.05,27.22 20.17,27.22 20.23,27.28 20.23,27.72 20.29,27.78 20.41,27.78 20.47,27.72 20.47,27.28 20.53,27.22 20.65,27.22 20.71,27.28 20.71,27.72 20.77,27.78 20.89,27.78 20.95,27.72 20.95,27.28 21.01,27.22 21.13,27.22 21.19,27.28 21.19,27.72 21.25,27.78 21.37,27.78 21.43,27.72 21.43,27.28 21.49,27.22 21.61,27.22 21.67,27.28 21.67,27.72 21.73,27.78 21.85,27.78 21.91,27.72 21.91,27.28 21.97,27.22 22.09,27.22 22.15,27.28 22.15,27.72 22.21,27.78 22.33,27.78 22.39,27.72 22.39,27.28 22.45,27.22 22.57,27.22 22.63,27.28 22.63,27.72 22.69,27.78 22.81,27.78 22.87,27.72 22.87,27.28 22.93,27.22 23.05,27.22 23.11,27.28 23.11,27.41 23.17,27.47 23.67,27.47 26.15,29.95 29.35,29.95 31.15,28.15 32.4,28.15 33.2,28.95 v1(33.2,29.25)
FMC_D14: U4.N3 U5.L14 | length 33.2
  Top w0.12: U4.N3@13.1,31.25 v1(13.5,30.85) ; v1(33.2,30.05) U5.L14@33.6,30.45
  F3 w0.12: v1(13.5,30.85) 14.8,30.85 15.277,30.373 15.277,30.288 15.076,30.086 15.076,30.001 15.161,29.916 15.245,29.916 15.636,30.307 15.721,30.307 15.806,30.222 15.806,30.138 15.415,29.747 15.415,29.662 15.5,29.577 15.585,29.577 15.976,29.968 16.061,29.968 16.146,29.883 16.146,29.798 15.755,29.407 15.755,29.322 15.839,29.238 15.924,29.238 16.315,29.629 16.4,29.629 16.485,29.544 16.485,29.459 16.094,29.068 16.094,28.983 16.179,28.898 16.264,28.898 16.655,29.289 16.739,29.289 16.824,29.204 16.824,29.119 16.72,29.015 16.72,28.93 17.49,28.16 19.09,28.16 19.15,28.1 19.15,28.02 19.21,27.96 19.33,27.96 19.39,28.02 19.39,28.47 19.45,28.53 19.57,28.53 19.63,28.47 19.63,28.22 19.69,28.16 23.36,28.16 23.491,28.291 23.491,28.376 23.446,28.42 23.446,28.505 23.531,28.59 23.616,28.59 23.894,28.312 23.978,28.312 24.063,28.397 24.063,28.482 23.786,28.759 23.786,28.844 23.871,28.929 23.956,28.929 24.233,28.652 24.318,28.652 24.403,28.736 24.403,28.821 24.125,29.099 24.125,29.184 24.21,29.268 24.295,29.268 24.572,28.991 24.657,28.991 24.742,29.076 24.742,29.161 24.465,29.438 24.465,29.523 24.55,29.608 24.634,29.608 24.912,29.33 24.997,29.33 25.082,29.415 25.082,29.5 24.804,29.778 24.804,29.862 24.889,29.947 24.974,29.947 25.251,29.67 25.336,29.67 25.421,29.755 25.421,29.84 25.273,29.988 25.273,30.073 25.4,30.2 29.8,30.2 30.35,29.65 32.8,29.65 v1(33.2,30.05)
FMC_D15: U4.R2 U5.K15 | length 33
  Top w0.12: U4.R2@12.3,29.65 v1(12.7,29.25) ; v1(34,29.25) U5.K15@34.4,29.65
  F3 w0.12: v1(12.7,29.25) 12.7,28.11 13.91,26.9 15.3,26.9 15.36,26.84 15.36,26.67 15.42,26.61 15.54,26.61 15.6,26.67 15.6,27.05 15.66,27.11 15.78,27.11 15.84,27.05 15.84,26.67 15.9,26.61 16.02,26.61 16.08,26.67 16.08,27.05 16.14,27.11 16.26,27.11 16.32,27.05 16.32,26.67 16.38,26.61 16.5,26.61 16.56,26.67 16.56,27.05 16.62,27.11 16.74,27.11 16.8,27.05 16.8,26.67 16.86,26.61 16.98,26.61 17.04,26.67 17.04,27.05 17.1,27.11 17.22,27.11 17.28,27.05 17.28,26.67 17.34,26.61 17.46,26.61 17.52,26.67 17.52,27.05 17.58,27.11 17.7,27.11 17.76,27.05 17.76,26.67 17.82,26.61 17.94,26.61 18,26.67 18,27.05 18.06,27.11 18.18,27.11 18.24,27.05 18.24,26.67 18.3,26.61 18.42,26.61 18.48,26.67 18.48,27.05 18.54,27.11 18.66,27.11 18.72,27.05 18.72,26.67 18.78,26.61 18.9,26.61 18.96,26.67 18.96,26.84 19.02,26.9 23.65,26.9 26.45,29.7 29.1,29.7 30.9,27.9 32.7,27.9 34,29.2 v1(34,29.25)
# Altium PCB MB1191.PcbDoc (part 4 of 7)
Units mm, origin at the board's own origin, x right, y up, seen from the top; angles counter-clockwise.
Board outline 130 x 80 mm, 8 copper layers (Top, F2, F3, F4, F5, F6, F7, Bottom), stack 1.115 mm thick; 360 components, 347 nets, 1451 pads, 1068 vias.

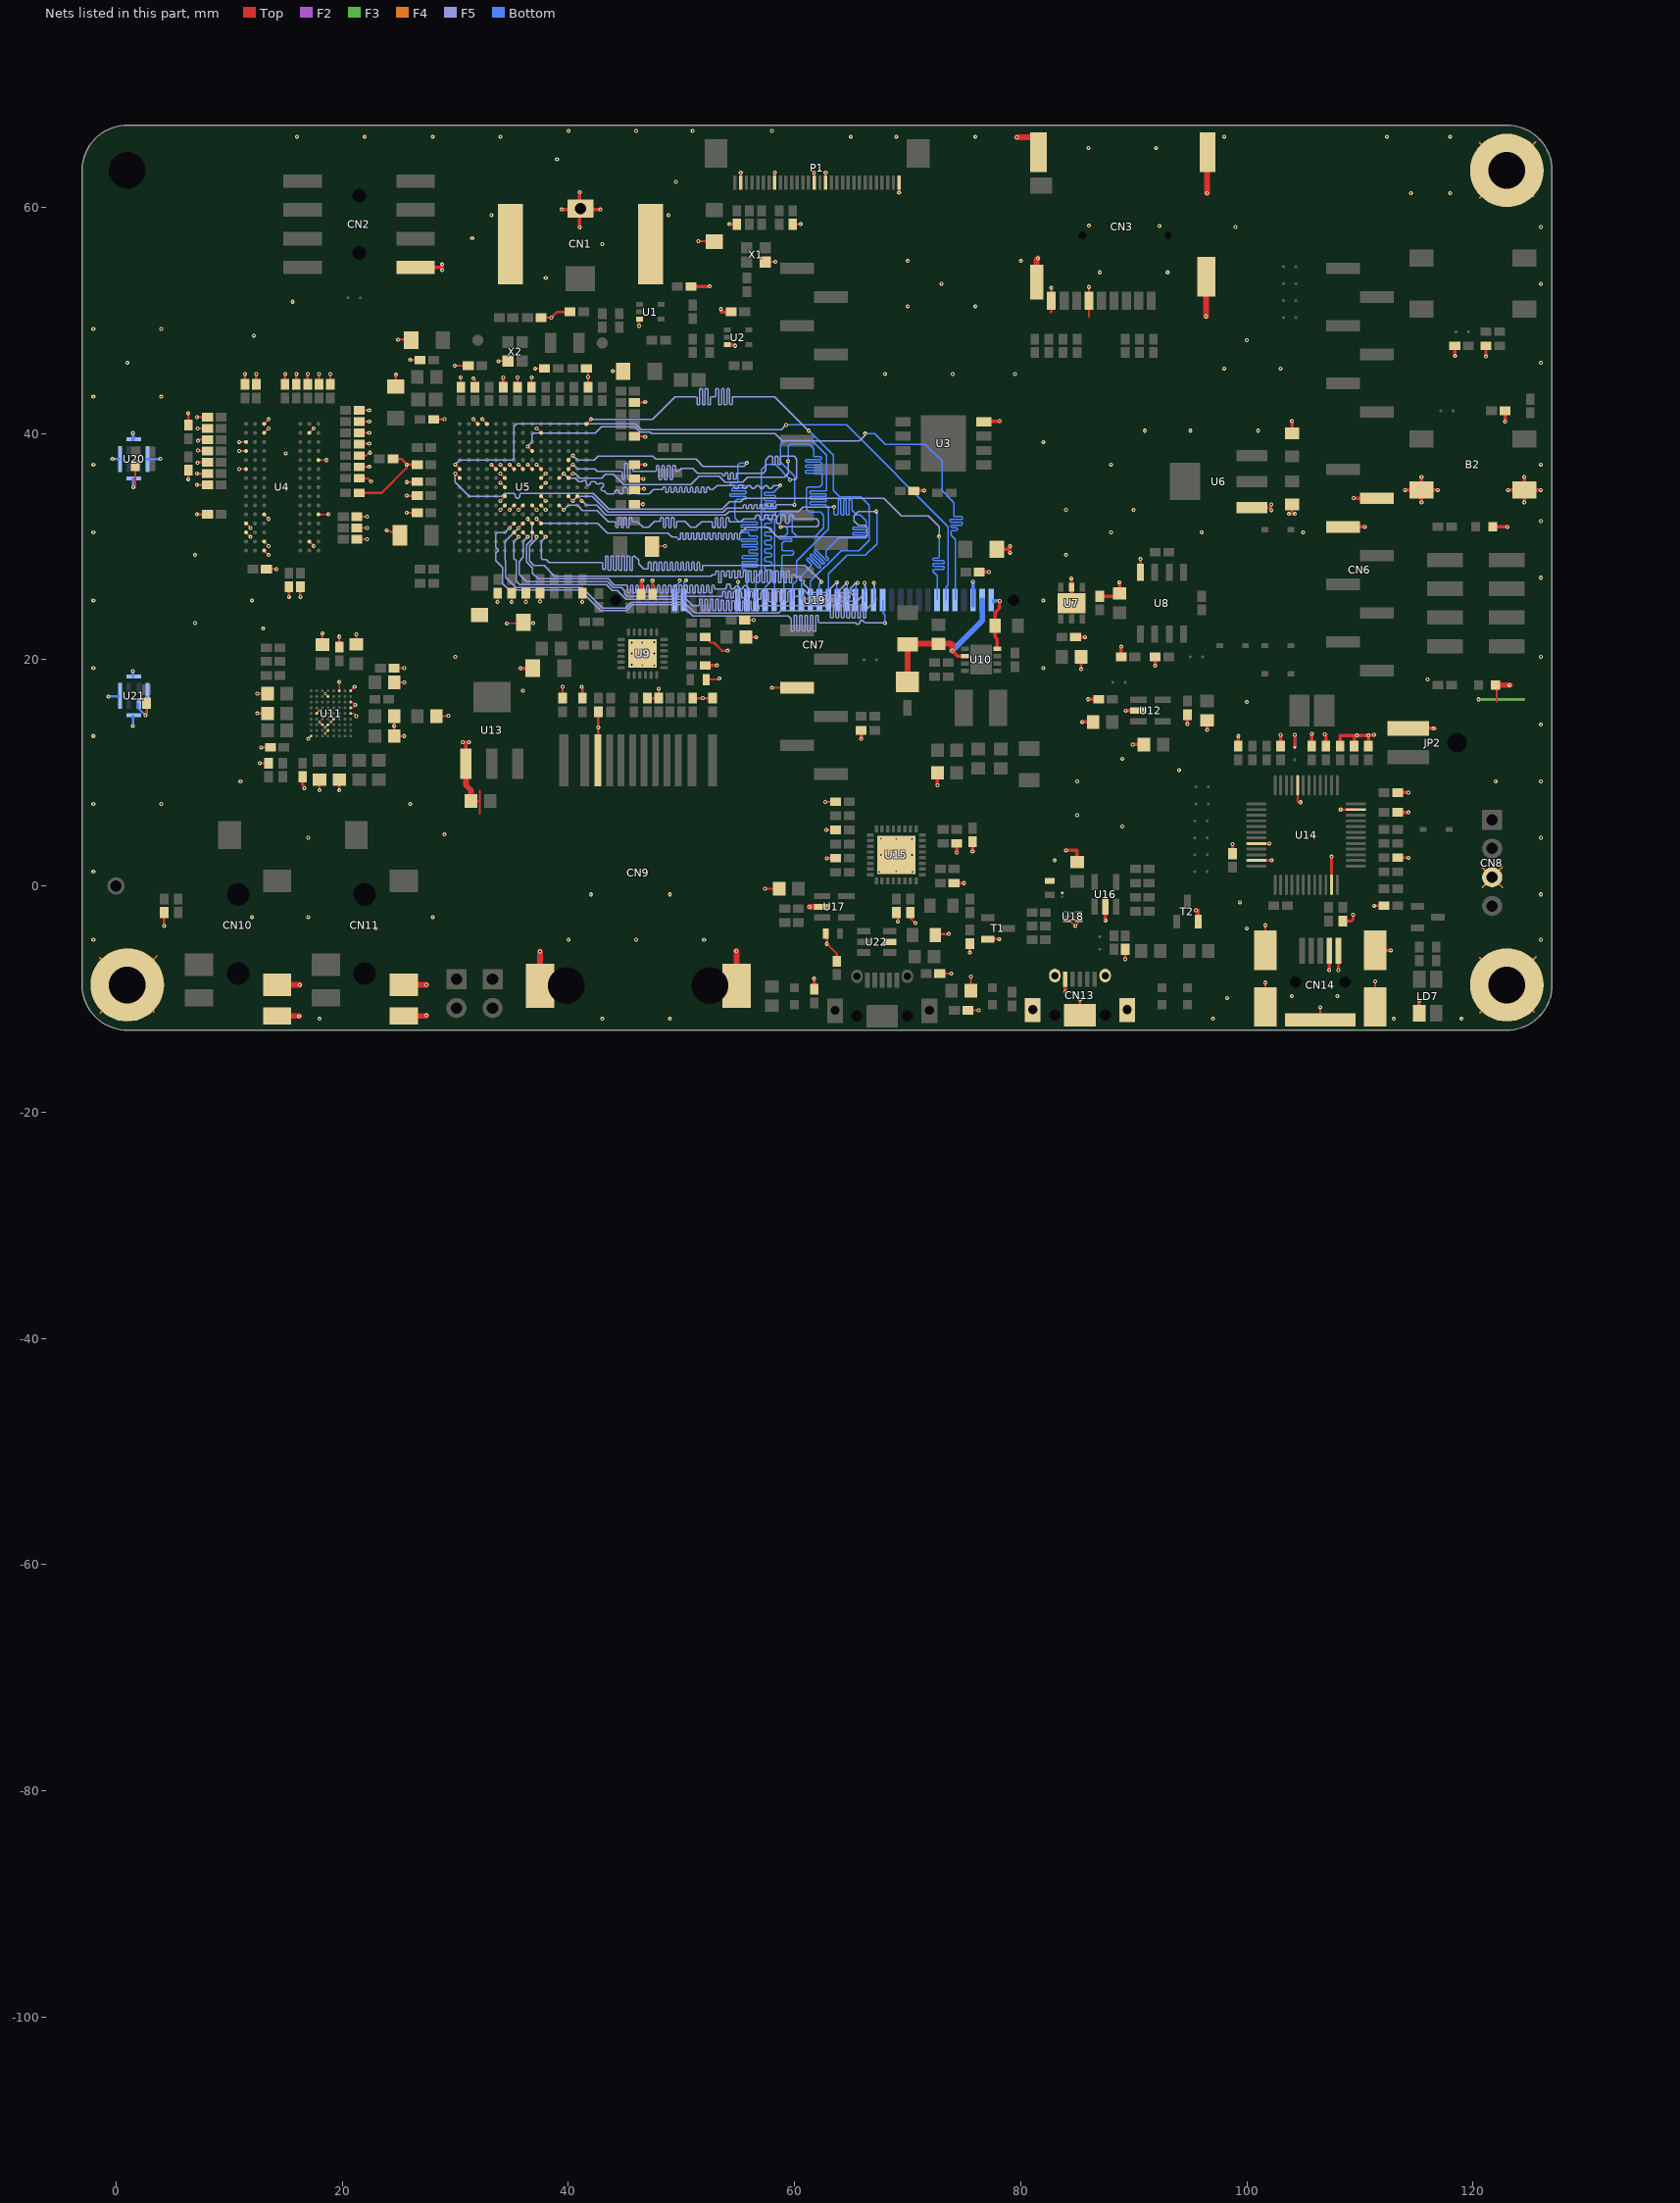
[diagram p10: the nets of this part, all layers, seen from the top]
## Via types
v1: diameter 0.35, hole 0.15, Top to Bottom, tented both sides, 1041 vias
v2: diameter 0.25, hole 0.1, Top to Bottom, tented both sides, 26 vias
v3: diameter 0.3, hole 0.1, Top to Bottom, tented both sides, 1 vias

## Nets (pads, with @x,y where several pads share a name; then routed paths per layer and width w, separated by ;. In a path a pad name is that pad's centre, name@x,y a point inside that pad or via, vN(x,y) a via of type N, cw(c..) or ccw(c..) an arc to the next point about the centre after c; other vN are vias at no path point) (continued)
GND: B2.2 B2.3 C1.2 C2.1 C3.1 C4.1 C5.1 C7.1 C8.2 C10.1 C11.1 C12.1 C13.1 C14.2 C15.1 C16.1 C17.2 C18.1 C19.1 C20.1 C21.1 C22.1 C23.1 C24.1 C25.1 C26.1 C27.1 C28.1 C29.1 C30.2 C31.1 C32.1 C33.1 C34.1 C35.1 C36.1 C37.1 C38.1 C39.1 C40.1 C41.1 C42.1 C43.1 C44.1 C45.1 C46.1 C47.1 C48.1 C49.2 C50.1 C51.1 C52.1 C53.1 C54.2 C55.1 C56.1 C57.1 C58.1 C59.1 C60.1 C61.1 C62.1 C63.2 C66.1 C67.1 C68.1 C69.1 C70.2 C71.1 C72.2 C73.2 C74.1 C75.1 C76.1 C77.2 C78.2 C79.2 C80.2 C81.1 C82.1 C83.1 C84.1 C85.1 C86.2 C88.1 C89.2 C90.1 C91.1 C92.2 C93.2 C94.1 C98.1 C99.1 C100.1 C101.1 C103.2 C104.2 C105.1 C108.1 C109.1 C110.1 C111.2 C112.1 C113.1 C114.2 C116.1 C117.2 C118.2 C119.1 C120.1 C121.1 C122.1 C123.1 CN1.1 CN2.7 CN3.6 CN3.9 CN3.11 CN3.12 CN3.13 CN3.14 CN6.6 CN6.7 CN7.7 CN8.3 CN9.10 CN9.13 CN9.14 CN10.2 CN10.3 CN11.2 CN11.3 CN13.5 CN13.6 CN14.4 CN14.5 CN14.6 JP2.1 L5.1 L7.1 LD1.2 LD2.2 LD7.1 P1.1 P1.14 P1.16 P1.23 P1.29 pad.1@1,-8.75 pad.1@123,63.25 pad.1@123,-8.75 R6.1 R19.1 R20.1 R23.2 R24.2 R25.2 R26.2 R27.2 R35.1 R36.2 R37.2 R40.2 R41.2 R43.2 R45.1 R48.2 R49.2 R50.2 R51.2 R52.2 R53.2 R55.1 R56.1 R68.1 R74.2 R79.2 R84.2 R88.1 R89.1 R94.1 R95.1 R97.1 R100.1 R101.1 R102.2 R103.1 R105.1 R106.1 R111.1 R112.1 R115.2 R121.2 R129.1 R131.2 R135.2 SB11.1 T1.2 T2.2 U1.3 U2.3 U3.4 U4.A3 U4.B3 U4.B8 U4.C1 U4.D1 U4.E9 U4.F1 U4.L3 U4.L9 U4.M1 U4.N1 U4.P3 U4.P8 U4.R3 U5.F2 U5.F6 U5.F7 U5.F8 U5.F9 U5.F10 U5.G6 U5.G10 U5.H6 U5.H10 U5.J6 U5.J10 U5.K6 U5.K7 U5.K8 U5.K9 U5.K10 U5.L6 U5.M1 U5.N1 U6.1 U7.2 U7.7 U8.4 U9.25 U11.A1 U11.A3 U11.A4 U11.A5 U11.C1 U11.D6 U11.E2 U11.E7 U11.E8 U11.F7 U11.G5 U11.H9 U12.2 U13.1 U14.8 U14.20 U14.23 U14.35 U14.47 U15.33 U16.2 U17.2 U18.3 U18.4 U19.3 U19.29 U19.35 U19.36 U20.5 U21.2 U21.5 U22.2 U23.2 U24.2 U25.2 X1.2 X2.2 | length 397.7
  Top w0.12: v1(10.9,36.85) U4.F1@11.5,36.85 ; U4.N1@11.5,31.25 v1(11.9,30.85) ; U4.M1@11.5,32.05 v1(11.9,31.65) ; U4.R3@13.1,29.65 v1(13.5,29.25) ; U4.P3@13.1,30.45 v1(13.5,30.05) ; U4.L3@13.1,32.85 v1(13.5,32.45) ; U4.B3@13.1,40.05 v1(13.5,40.45) ; U4.A3@13.1,40.85 v1(13.5,41.25) ; U4.P8@17.1,30.45 v1(17.5,30.05) ; v1(31.6,41.25) U5.N1@32,40.85 ; v1(32.4,41.25) U5.M1@32.8,40.85 ; v1(34,33.25) U5.K10@34.4,33.65 ; v1(34,34.05) U5.K9@34.4,34.45 ; v1(34,35.65) U5.K8@34.4,35.25 ; v1(34.575,23.2) 35.94,23.2 C63.2@36.03,23.29 36.095,23.225 v1(36.9,23.225) ; v1(34.8,33.25) U5.J10@35.2,33.65 ; v1(35.6,33.25) U5.H10@36,33.65 ; v1(35.6,37.25) U5.H6@36,36.85 ; v1(36.4,37.25) U5.G6@36.8,36.85 ; U5.G10@36.8,33.65 v1(37.2,33.25) ; v1(37.2,37.25) U5.F6@37.6,36.85 ; v1(37.2,40.45) U5.F2@37.6,40.05 ; U5.F10@37.6,33.65 v1(38,33.25) ; U5.F9@37.6,34.45 v1(38,34.05) ; U5.F8@37.6,35.25 v1(38,35.65) ; U5.F7@37.6,36.05 v1(38,36.45) ; U25.2@62.775,-4.2 U25.2@62.875,-4.3 ; U25.2@62.973,-4.267 U25.2@62.99,-4.285 ; v1@69.15,-3.204 v1(69.15,-3.142) ; U18.3@84.1,-3.1 84.14,-3.14 84.44,-3.14 v1(84.85,-3.55) 85.09,-3.31 85.09,-3.14 85.13,-3.1 U18.4@85.15,-3.1
  Top w0.15: v1(2.6,15.09) 2.7,15.19 C77.2@2.7,16.15 ; v1(10.9,38.45) U4.D1@11.5,38.45 ; v1(10.9,39.25) U4.C1@11.5,39.25 ; v1(17,13) U11.H9@17.25,13.25 ; U11.G5@17.75,15.25 v2(18,15.5) ; U4.L9@17.9,32.85 v1(18.8,32.85) ; v2(18,14.5) U11.F7@18.25,14.25 ; v2(18.5,13.5) U11.E8@18.75,13.75 ; v2(18.5,14) U11.E7@18.75,14.25 ; v2(18.5,17) U11.E2@18.75,16.75 ; v2(19,14.5) U11.D6@19.25,14.75 ; U11.C1@19.75,17.25 v1(19.75,18.05) ; U11.A5@20.75,15.25 21,15.25 v1(21.25,15) ; U11.A4@20.75,15.75 20.9,15.75 v1(21.15,16) 20.9,16.25 U11.A3@20.75,16.25 ; U11.A1@20.75,17.25 v1(21.1,17.6) ; C46.1@21.3,30.65 v1(22.2,30.65) ; C45.1@21.3,31.65 v1(22.2,31.65) ; C43.1@21.3,32.65 v1(22.2,32.65) ; v1(29.95,46) R20.1@31.15,46 ; C18.1@30.5,44.1 v1(30.5,44.95) ; C108.1@31.4,7.5 32.125,7.5 32.15,7.525 ; v1(31.6,44.85) 31.75,44.7 C19.1@31.75,44.1 ; 32.175,6.375 32.175,8.425 ; v1(33.75,25.1) C55.1@33.75,25.9 ; v1(33.8,46.4) 33.8,46.425 X2.2@34.675,46.425 ; v1(34,36.45) U5.K7@34.306,36.144 ; v1(34,37.25) 34.255,36.995 ; v1(35,25.1) C56.1@35,25.9 ; C21.1@35.5,44.1 v1(35.5,44.95) ; v1(36.25,25.1) C57.1@36.25,25.9 ; C22.1@36.75,44.1 v1(36.75,44.95) ; v1(37.05,45.75) C12.1@37.9,45.75 ; v1(37.5,25.15) C58.1@37.5,25.9 ; C5.1@37.6,50.25 v1(38.5,50.25) ; v1(41.25,25.1) C59.1@41.25,25.9 ; C13.1@41.6,45.75 41.75,45.6 v1(41.75,45) C23.1@41.75,44.1 ; v1(43.9,45.5) 44.5,45.5 44.676,45.676 44.853,45.853 C14.2@44.853,45.5 ; R45.1@45.85,39.75 46.8,39.75 v1(46.8,39.7) ; R35.1@45.85,42.75 46.75,42.75 v1(46.8,42.8) ; C48.1@47.397,30 47.397,30.05 v1(48.55,30.05) ; C83.1@48,16.6 v1(48,17.45) ; v1(51.5,57) 52.9,57 C1.2@52.9,56.953
  Top w0.165: U4.B8@17.1,40.05 v1(17.5,40.45) ; U4.E9@17.9,37.65 v1(18.6,37.65) ; 34.255,36.995 U5.K6@34.4,36.85 ; U5.K7@34.306,36.144 U5.K7@34.4,36.05
  Top w0.2: v1(1.53,35.26) v1@1.7,35.26 ; 1.7,35.21 v1@1.7,35.26 ; C30.2@1.7,37.15 v1@1.7,35.26 ; v1(4.25,-3.55) R121.2@4.25,-2.35 ; v1(6.4,35.95) R48.2@6.4,36.75 ; R40.2@6.4,40.75 v1(6.4,41.8) ; v1(7.15,32.85) C42.1@8.1,32.85 ; v1(7.15,35.45) R55.1@8.1,35.45 ; v1(7.15,36.45) R52.2@8.1,36.45 ; v1(7.15,41.45) R36.2@8.1,41.45 ; v1(7.2,37.4) 7.2,37.45 C31.1@8.1,37.45 ; v1(7.2,40.45) C26.1@8.1,40.45 ; v1(7.25,38.5) 7.25,38.45 R49.2@8.1,38.45 ; v1(7.25,39.35) 7.25,39.45 R43.2@8.1,39.45 ; R23.2@11.4,44.35 v1(11.4,45.25) ; R24.2@12.4,44.35 v1(12.4,45.25) ; v1(12.5,15.25) C80.2@13.4,15.25 ; v1(12.5,17) C78.2@13.4,17 ; v1(12.7,10.85) R102.2@13.5,10.85 ; v1(12.85,12.25) C92.2@13.65,12.25 ; C50.1@13.3,28 v1(14.2,28) ; R25.2@14.95,44.35 v1(14.95,45.25) ; v1(15.3,25.55) C51.1@15.3,26.45 ; C15.1@15.95,44.35 v1(15.95,45.25) ; v1(16.3,25.55) C52.1@16.3,26.45 ; C16.1@16.95,44.35 v1(16.95,45.25) ; R26.2@17.95,44.35 v1(17.95,45.25) ; v1(18,8.45) C104.2@18,9.4 ; v1(18.25,22.35) 18.25,21.35 C69.1@18.26,21.34 ; R27.2@18.95,44.35 v1(18.95,45.25) ; v1(19.75,8.45) C105.1@19.75,9.4 ; C70.2@19.75,21.1 v1(19.75,22.05) ; C71.1@21.25,21.35 v1(21.25,22.25) ; R56.1@21.5,34.75 23.5,34.75 25.7,36.95 v1(25.7,37.25) v1@25.75,37.25 ; C34.1@21.5,36.05 22.301,36 v1@22.551,35.75 ; R53.2@21.5,37.05 v1(22.4,37.05) ; R50.2@21.5,38.05 22.1,38.05 22.35,38.3 v1(22.45,38.3) ; C28.1@21.5,39.05 21.5,39.1 v1(22.4,39.1) ; C27.1@21.5,40.05 v1(22.4,40.05) ; R41.2@21.5,41.05 v1(22.4,41.05) ; R37.2@21.5,42.05 v1(22.4,42.05) ; v1(23.95,31.45) C47.1@25.103,31 ; R51.2@24.5,37.75 25.25,37.75 v1@25.75,37.25 ; C88.1@24.6,15 v1(24.6,14.15) C93.2@24.6,13.25 v1(25.5,13.25) ; C79.2@24.6,18 v1(25.5,18) ; C72.2@24.6,19.25 v1(25.5,19.25) ; C17.2@24.75,44.147 v1(24.75,45.2) ; v1(24.95,48.3) 26.103,48.3 C8.2@26.103,48.25 ; v1(25.7,33) C44.1@26.65,33 ; v1(25.7,34.5) C39.1@26.65,34.5 ; v1(25.7,35.7) 26.65,35.7 C35.1@26.65,35.75 ; v1(26,46.5) C11.1@26.9,46.5 ; C32.1@26.65,37.25 v1@25.75,37.25 ; C24.1@28.1,41.25 28.1,41.26 v1(29.06,41.26) ; C89.2@28.35,15 29.4,15 v1(29.4,15.05) ; v1(33.2,37.25) U5.L6@33.6,36.85 ; v1(34.8,37.25) U5.J6@35.2,36.85 ; v1(38.5,50.25) 39,50.75 R6.1@40.15,50.75 ; R88.1@39.5,16.6 v1(39.5,17.6) ; v1(41.2,17.6) 41.25,17.6 R89.1@41.25,16.6 ; CN9.10@42.63,11.099 v1@42.63,14 ; v1(42.65,14) v1@42.63,14 ; C81.1@42.65,15.4 42.65,14.02 v1@42.63,14 ; C40.1@45.85,33.75 v1(46.6,33.75) ; C37.1@45.85,35 45.85,35.1 v1(46.7,35.1) ; C36.1@45.85,36 v1(46.65,36) ; C33.1@45.85,37.25 v1(46.8,37.25) ; v1@46.3,49.5 U1.3@46.3,50.1 ; C82.1@47,16.6 C83.1@48,16.6 ; R94.1@51,16.6 v1(51.9,16.6) R95.1@52.75,16.6 ; C66.1@52.1,22 52.6,21.5 52.9,21.5 53.6,20.8 v1(54.1,20.8) ; R84.2@52.35,18.25 53.25,18.25 v1(53.35,18.35) ; v1(54.25,58.5) C2.1@54.9,58.5 ; P1.29@55.25,62.175 v1(55.25,63.075) ; R74.2@55.6,23.5 v1(56.4,23.5) ; C67.1@55.7,22 v1(56.6,22) ; v1(57.4,-0.25) C114.2@58.65,-0.25 ; X1.2@57.425,55.175 v1(58.325,55.175) ; v1(58,17.5) 58,17.516 CN7.7@60.24,17.516 ; P1.23@58.25,62.175 v1(58.25,63.075) ; C3.1@59.85,58.5 v1(60.55,58.5) ; P1.16@61.75,62.175 v1(61.75,63.075) ; v1(62.725,7.425) 63.625,7.425 R103.1@63.65,7.45 ; P1.14@62.75,62.175 v1(62.75,63.075) ; v1(62.8,4.95) R106.1@63.65,4.95 ; v1(62.85,2.45) R111.1@63.65,2.45 ; U25.2@62.875,-4.3 v1(62.875,-5.125) 63.736,-5.986 63.736,-6.636 C120.1@63.75,-6.65 ; v1(67.65,2.75) v1(69,2.75) ; C116.1@69,-2.35 69.15,-2.5 v1(69.15,-3.142) ; v1(69,1.3) v1(69,2.75) ; v1(69.25,61.275) P1.1@69.25,62.175 ; C117.2@70.25,-2.35 70.25,-2.85 v1(70.7,-3.3) ; v1(70.4,2.75) v1(69,2.75) ; C119.1@72.397,-4.25 v1(73.65,-4.25) ; C121.1@72.85,-7.75 v1(73.85,-7.75) ; C123.1@75.35,-11 v1(76.3,-11) ; v1(75.5,-5.9) R131.2@75.5,-5.1 ; L7.1@75.6,-9.25 v1(75.6,-8) ; T1.2@77.1,-4.7 v1(78.1,-4.7) ; 82.675,50.75 82.65,50.75 82.75,50.85 82.725,50.875 v1(82.725,52.875) ; CN13.6@85.25,-11.45 v1(85.25,-10.04) ; 86.05,50.35 CN3.6@86.05,51.725 86.093,51.768 86.05,51.81 v1(86.05,52.95) ; U6.1@100.45,33.45 102.16,33.45 ; v1(101.65,-8.55) 101.653,-8.55 CN14.6@101.653,-10.7 ; v1(101.65,-3.48) 101.653,-3.48 CN14.6@101.653,-5.7 ; v1(102.16,33.22) 102.16,33.45 ; v1@102.16,33.77 v1(102.16,33.73) 102.16,33.45 ; v1(103.71,32.89) 103.74,32.86 104,32.86 ; C41.1@104,33.734 104,32.86 ; v1(104.26,32.89) 104.26,32.87 104.25,32.86 104,32.86 ; U14.8@104.5,8.9 104.5,7.4 v1(104.75,7.4) ; CN14.6@106.5,-11.85 v1(106.5,-10.72) ; v1(111.35,-8.44) 111.353,-8.44 CN14.6@111.353,-10.7 ; 122.1,16.3 LD2.2@122.1,17.75
  Top w0.25: C113.1@98.75,2.85 v1(98.75,3.7) ; U14.23@100.85,2.25 v1(102.2,2.25) ; U14.20@100.85,3.75 v1(102,3.75) ; SB11.1@104.25,12.25 v1(104.25,13.35) ; U14.35@107.5,0.1 v1(107.5,2.6) ; v1(108.3,6.75) U14.47@109.65,6.75 ; C118.2@108.5,-3.1 109.25,-3.1 109.4,-2.95 v1(109.4,-2.55) ; v1(111.25,-1.75) R129.1@112.15,-1.75 ; R112.1@113.35,2.5 v1(114.3,2.5)
  Top w0.3: C103.2@16.5,9.65 16.5,8.949 16.65,8.799 v1(16.65,8.65) ; CN2.7@26.5,54.69 28.85,54.69 ; v1(28.85,54.45) 28.85,54.69 ; v1(28.85,54.95) 28.85,54.69 ; v1(30.65,12.7) 30.95,12.7 ; U13.1@30.95,10.8 30.95,12.7 ; v1(31.2,12.7) 30.95,12.7 ; C20.1@34.25,44.1 v1(34.25,44.95) ; v1(35.75,19.25) C73.2@36.853,19.25 ; v1(39.42,59.8) CN1.1@41,59.8 ; v1(41,58.22) CN1.1@41,59.8 ; v1(41,61.34) CN1.1@41,59.8 ; v1(42.83,59.8) CN1.1@41,59.8 ; v1(46.25,49.5) U1.3@46.25,49.95 ; R68.1@46.436,25.786 46.436,27 v1(46.55,27) ; C60.1@47.45,25.8 v1(47.45,27) ; C4.1@50.85,53 v1(52.5,53) ; C74.1@52.1,19.5 v1(53.15,19.5) ; v1(53.5,51) 53.5,50.75 C7.1@54.4,50.75 ; U2.3@54.05,47.85 54.75,47.85 v1(54.75,47.75) ; C122.1@61.75,-9.15 v1(61.75,-8.2) ; v1(65.9,13) C90.1@65.9,13.75 ; C38.1@70.547,34.924 70.547,34.95 v1(71.5,34.95) ; v1(72.65,8.9) L5.1@72.65,10 ; R115.2@74.1,0.25 v1(75,0.25) ; v1(74.35,2.95) C110.1@74.35,3.75 ; v1(75.75,3.05) C111.2@75.75,3.9 ; C53.1@76.35,27.75 v1(77.2,27.75) ; U3.4@77.122,41.079 78.15,41.079 v1(78.15,41.1) ; C49.2@77.897,29.75 79.05,29.75 ; v1(79.05,29.45) 79.05,29.75 ; v1(79.05,30.05) 79.05,29.75 ; v1(83.95,-9.35) CN13.5@83.95,-8.25 ; v1(84,3.15) 85,3.15 C112.1@85,2.1 ; U7.7@84.5,25 U7.2@84.5,26.4 v1(84.5,27.2) ; C68.1@84.85,22 v1(85.7,22) ; v1(85.35,19.15) C75.1@85.35,20.25 ; v1(85.45,14.5) C91.1@86.4,14.5 ; v1(85.95,16.5) C84.1@86.9,16.5 ; C61.1@87,25.6 88.75,25.6 C62.1@88.75,25.85 v1(88.75,26.85) ; v1(87.5,-3.05) U16.2@87.5,-1.825 ; R79.2@88.9,20.25 v1(88.9,21.15) ; v1(89.25,-6.5) R135.2@89.25,-5.6 ; v1(89.3,15.5) U12.2@90.425,15.5 ; v1(89.9,12.5) C94.1@90.9,12.5 ; U8.4@90.595,27.73 90.595,28.9 v1(90.6,28.9) ; v1(91.9,19.45) C76.1@91.9,20.25 ; v1(94.75,14.3) C85.1@94.75,15.15 ; v1(95.5,-2.15) 95.7,-2.15 T2.2@95.7,-3.15 ; v1(96.5,13.8) C86.2@96.5,14.65 ; R97.1@99.25,12.35 v1(99.25,13.25) ; C98.1@103,12.35 v1(103,13.35) ; C29.1@104,40.016 v1(104,41.1) ; C99.1@105.75,12.35 v1(105.75,13.45) ; v1(106.9,13.4) 107,13.4 C100.1@107,12.35 ; v1(107.3,-7.45) 107.303,-7.45 CN14.4@107.303,-5.75 ; v1(108.1,-7.45) 108.103,-7.45 CN14.5@108.103,-5.75 ; R100.1@108.25,12.35 108.25,13.3 109.5,13.3 ; CN6.6@108.5,31.74 110.45,31.74 v1(110.45,31.75) ; v1(109.45,34.3) 109.45,34.28 CN6.7@111.5,34.28 ; R101.1@109.5,12.35 109.5,13.3 ; C101.1@110.75,12.35 v1(110.75,13.3) ; v1(111.25,13.35) 110.75,13.35 v1(110.75,13.3) ; CN14.6@111.353,-5.7 v1(112.75,-5.7) ; R105.1@113.35,6.5 v1(114.3,6.5) ; C109.1@113.35,8.25 v1(114.3,8.25) ; v1(114,35) B2.2@115.45,35 ; JP2.1@114.3,13.925 116.66,13.925 116.66,13.905 v1(116.5,13.905) ; LD7.1@115.25,-11.25 v1(115.25,-10.15) ; v1(115.45,33.9) B2.2@115.45,35 ; v1(115.45,36.15) B2.2@115.45,35 ; v1(116.9,35) B2.2@115.45,35 ; v1(118.4,46.85) C10.1@118.4,47.75 ; v1(121.15,46.8) R19.1@121.15,47.75 ; LD1.2@121.85,31.75 v1(123.05,31.75) ; v1(122.85,41.05) C25.1@122.85,42 ; v1(123.1,35) B2.3@124.55,35 ; v1(124.55,33.9) B2.3@124.55,35 ; v1(124.55,36.15) B2.3@124.55,35 ; v1(126,35) B2.3@124.55,35 ; 109.5,13.3 v1(109.75,13.3) v1(110.75,13.3)
  Top w0.5: CN10.2@14.25,-11.5 v1(16.2,-11.5) ; CN10.3@14.25,-8.75 v1(16.25,-8.75) ; CN11.2@25.45,-11.5 27.4,-11.5 v1(27.45,-11.45) ; CN11.3@25.45,-8.75 v1(27.45,-8.75) ; U13.1@30.95,10.8 30.95,8.9 31.4,8.45 C108.1@31.4,7.5 ; CN9.14@37.499,-8.814 v1(37.5,-5.8) ; v1(54.85,-5.75) 54.873,-5.75 CN9.13@54.873,-8.814 ; v1(61.325,-1.85) U17.2@62.45,-1.85 ; v1(79.675,66.2) 81.4,66.2 81.55,66.05 CN3.11@81.55,63.9 ; CN3.14@81.4,52.4 81.4,55.35 v1(81.525,55.475) ; v1(96.4,50.35) CN3.13@96.4,52.9 ; v1(96.5,61.25) CN3.12@96.5,63.9 ; LD2.2@122.1,17.75 v1(123.25,17.75) v1@123.3,17.75
  F2 w0.2: 104.29,12.31 v1@104.29,13.35
  F3 w0.2: v1(120.5,16.5) 124.5,16.5
  F4 w0.15: -1.43,-6.345 0.988,-8.762 pad.1@1.025,-8.8 ; -1.405,-11.23 pad.1@1.025,-8.8 ; 3.38,-11.155 pad.1@1.025,-8.8 ; 3.612,-6.212 pad.1@1.025,-8.8 ; 120.57,65.73 pad.1@123.025,63.275 ; 120.595,-6.345 pad.1@123,-8.75 pad.1@123.05,-8.8 ; 120.595,60.845 pad.1@123,63.25 pad.1@123.025,63.275 ; 120.62,-11.23 pad.1@123.05,-8.8 ; 120.825,-0.15 CN8.3@121.725,0.75 ; 120.825,1.65 CN8.3@121.7,0.775 ; CN8.3@121.7,0.85 CN8.3@121.7,0.775 ; 122.6,1.75 122.6,1.67 CN8.3@121.703,0.773 ; 122.625,-0.15 CN8.3@121.725,0.75 ; 125.38,60.92 pad.1@123.025,63.275 ; 125.405,-11.155 pad.1@123.05,-8.8 ; 125.538,65.788 pad.1@123.025,63.275 ; 125.588,-6.262 pad.1@123.05,-8.8 ; CN8.3@121.7,0.775 CN8.3@121.702,0.773 ; CN8.3@121.7,0.775 CN8.3@121.7,0.77 CN8.3@121.703,0.773 ; CN8.3@121.703,0.773 CN8.3@121.725,0.75
  F4 w0.2: v1(120.5,16.5) 124.5,16.5
  Bottom w0.15: v1(-0.31,37.74) v1@-0.31,37.75 ; v1(2.6,15.09) 2.725,15.215 U21.5@2.725,16.75 ; U19.36@49.454,25.144 49.454,26.454 49.85,26.85 v1(49.85,27) ; v1(50.4,27) 50.225,26.825 50.225,25.323 U19.35@50.404,25.144 ; U19.29@55,25.348 v1(55,26.875)
  Bottom w0.2: v1(-0.66,16.75) U21.5@0.275,16.75 ; v1@-0.31,37.75 U20.5@0.275,37.75 ; v1(1.49,19.01) 1.5,19.01 U21.5@1.5,18.475 ; v1(1.5,14.15) U21.5@1.5,15.025 ; v1@1.5,35.21 v1@1.5,35.26 ; U20.5@1.5,36.025 v1@1.5,35.26 ; v1@1.7,35.26 v1(1.53,35.26) v1@1.5,35.26 ; U21.2@1.95,16.075 1.95,15.75 2.6,15.1 v1(2.6,15.09) ; U20.5@2.725,37.75 U20.5@2.8,37.75 v1(3.93,37.75) ; v1(46.55,19.5) v1@46.572,19.5 ; v1(46.55,21.5) v1@46.572,21.5 ; v1(70.45,1.25) v1@70.475,1.275 ; v1(120.5,16.5) 124.5,16.5
  Bottom w0.3: U20.5@1.5,39.475 v1(1.5,40.05) ; U19.3@75.775,24.775 v1(75.775,26.9)
  other v1: 18,-11.75 43,-11.75 49,-11.75 97,-11.75 113,-11.75 119,-11.75 98.26,-9.895 104,-9.75 108,-9.75 -2,-4.75 40,-4.75 46,-4.75 52,-4.75 126,-4.75 23,-3.75 100,-3.75 12,-2.75 17,-2.75 28,-2.75 99.4,-1.45 42,-0.75 49,-0.75 126,-0.75 -2,1.25 67.5,1.25 83,2.25 69,4.15 70.4,4.15 67.65,4.2 17,4.25 126,4.25 29.05,4.55 89,5.25 85,6.25 -2,7.25 4,7.25 26,7.25 11,9.25 85,9.25 122,9.25 126,9.25 94,10.25 89,11.25 -2,13.25 126,14.25 100,16.25 36,17.25 116,18.25 -2,19.25 82,19.25 47.6,19.5 45.6,19.55 30,20.25 126,20.25 45.6,20.55 46.572,20.539 47.6,20.55 45.6,21.5 47.6,21.55 13,22.75 7,23.25 -2,25.25 12,25.25 82,25.25 126,27.25 7,29.25 84,29.25 -2,31.25 88,31.25 96,31.25 105,31.25 126,32.25 84,33.25 90,33.25 22.55,35.75 -2,37.25 88,37.25 126,37.25 15,38.25 82,39.25 91,40.25 95,40.25 101,40.25 -2,43.25 4,43.25 68,45.25 74,45.25 79.5,45.25 98,45.75 103,45.75 1,46.25 126,46.25 100,48.25 12.2,48.65 -2,49.25 4,49.25 70,51.25 76,51.25 15.6,51.65 73,53.25 126,53.25 38,53.75 87,54.25 93,54.25 70,55.25 80,55.25 43,56.75 31.5,57.25 99,58.25 126,58.25 92.275,58.35 86.05,58.375 33.2,59.3 48.875,59.3 114.5,61.25 118,61.25 49.5,62.25 39,64.25 86,65.25 92,65.25 16,66.25 22,66.25 28,66.25 34,66.25 65,66.25 69,66.25 76,66.25 98,66.25 112.4,66.25 118,66.25 40,66.75 46,66.75 51,66.75 58,66.75
LCD_B0: U5.A1 U19.21 | length 58.3
  Top w0.12: U5.A1@41.6,40.85 v1(42,41.25)
  F5 w0.12: v1(42,41.25) 47.46,41.25 49.46,43.25 51.32,43.25 51.38,43.19 51.38,42.59 51.44,42.53 51.56,42.53 51.62,42.59 51.62,43.91 51.68,43.97 51.8,43.97 51.86,43.91 51.86,42.59 51.92,42.53 52.04,42.53 52.1,42.59 52.1,43.91 52.16,43.97 52.28,43.97 52.34,43.91 52.34,42.59 52.4,42.53 52.52,42.53 52.58,42.59 52.58,43.19 52.64,43.25 53,43.25 53.06,43.31 53.06,43.91 53.12,43.97 53.24,43.97 53.3,43.91 53.3,42.59 53.36,42.53 53.48,42.53 53.54,42.59 53.54,43.91 53.6,43.97 53.72,43.97 53.78,43.91 53.78,42.59 53.84,42.53 53.96,42.53 54.02,42.59 54.02,43.91 54.08,43.97 54.2,43.97 54.26,43.91 54.26,42.59 54.32,42.53 54.44,42.53 54.5,42.59 54.5,43.19 54.56,43.25 58.25,43.25 v1(61.25,40.25)
  Bottom w0.12: v1(61.25,40.25) 61.28,40.25 63.43,38.1 63.43,34.97 64,34.4 65.86,34.4 66.6,33.66 66.6,30.56 65.69,29.65 64.12,29.65 61.425,26.955 U19.21@61.425,25.15
LCD_B1: U5.B9 U19.22 | length 57.9
  Top w0.12: U5.B9@40.8,34.45 v1(41.2,34.05)
  F5 w0.12: v1(41.2,34.05) 41.6,33.65 42.5,33.65 43.35,32.8 53.9,32.8 54.19,33.09 60.35,33.09 60.76,33.5 v1(63.5,33.5)
  Bottom w0.12: U19.22@60.625,25.323 60.625,27.435 61.51,28.32 61.51,28.405 61.086,28.829 61.086,28.914 61.171,28.999 61.256,28.999 62.15,28.104 62.235,28.104 62.32,28.189 62.32,28.274 61.425,29.169 61.425,29.254 61.51,29.338 61.595,29.338 62.49,28.444 62.574,28.444 62.659,28.529 62.659,28.614 61.765,29.508 61.765,29.593 61.85,29.678 61.934,29.678 62.829,28.783 62.914,28.783 62.999,28.868 62.999,28.953 62.79,29.162 62.79,29.63 63.92,30.76 66.3,30.76 66.36,30.82 66.36,30.94 66.3,31 65.22,31 65.16,31.06 65.16,31.18 65.22,31.24 66.3,31.24 66.36,31.3 66.36,31.42 66.3,31.48 65.22,31.48 65.16,31.54 65.16,31.66 65.22,31.72 66.3,31.72 66.36,31.78 66.36,32.27 65.84,32.79 65.52,32.79 65.07,33.24 65.07,34.1 65.01,34.16 64.89,34.16 64.83,34.1 64.83,32.84 64.77,32.78 64.65,32.78 64.59,32.84 64.59,34.1 64.53,34.16 64.41,34.16 64.35,34.1 64.35,32.84 64.29,32.78 64.17,32.78 64.11,32.84 64.11,34.1 64.05,34.16 63.93,34.16 63.87,34.1 63.87,32.84 63.81,32.78 63.62,32.78 63.5,32.9 v1(63.5,33.5)
LCD_B2: U5.C9 U19.23 | length 57.9
  Top w0.12: U5.C9@40,34.45 v1(40.4,34.05)
  F5 w0.12: v1(40.4,34.05) 40.8,34.45 42.1,34.45 43.5,33.05 53.7,33.05 54.05,33.4 55.42,33.4 55.48,33.46 55.48,33.65 55.54,33.71 55.66,33.71 55.72,33.65 55.72,33.4 55.78,33.34 55.9,33.34 55.96,33.4 55.96,33.65 56.02,33.71 56.14,33.71 56.2,33.65 56.2,33.4 56.26,33.34 56.38,33.34 56.44,33.4 56.44,33.65 56.5,33.71 56.62,33.71 56.68,33.65 56.68,33.4 56.74,33.34 56.86,33.34 56.92,33.4 56.92,33.65 56.98,33.71 57.1,33.71 57.16,33.65 57.16,33.4 57.22,33.34 57.34,33.34 57.4,33.4 57.4,33.65 57.46,33.71 57.58,33.71 57.64,33.65 57.64,33.4 57.7,33.34 57.82,33.34 57.88,33.4 57.88,33.65 57.94,33.71 58.06,33.71 58.12,33.65 58.12,33.4 58.18,33.34 58.3,33.34 58.36,33.4 58.36,33.65 58.42,33.71 60,33.71 v1(60,33.7)
  Bottom w0.12: U19.23@59.825,25.323 59.825,26.625 60.175,26.975 60.175,28.725 62.99,31.54 62.99,33.41 62.69,33.71 61.43,33.71 61.37,33.77 61.37,33.89 61.43,33.95 62.75,33.95 62.81,34.01 62.81,34.13 62.75,34.19 61.43,34.19 61.37,34.25 61.37,34.37 61.43,34.43 62.75,34.43 62.81,34.49 62.81,34.61 62.75,34.67 61.43,34.67 61.37,34.73 61.37,34.85 61.43,34.91 62.75,34.91 62.83,34.99 62.83,38.1 61.53,39.4 59.14,39.4 58.74,39 58.74,37.47 60,36.21 v1(60,33.7)
LCD_B3: U5.D10 U19.24 | length 58.2
  Top w0.12: U5.D10@39.2,33.65 v1(39.6,33.25)
  F5 w0.12: v1(39.6,33.25) 40,33.65 40.8,33.65 41.25,33.2 42.55,33.2 43.54,32.21 44.12,32.21 44.18,32.15 44.18,31.75 44.24,31.69 44.36,31.69 44.42,31.75 44.42,32.5 44.48,32.56 44.6,32.56 44.66,32.5 44.66,31.75 44.72,31.69 44.84,31.69 44.9,31.75 44.9,32.5 44.96,32.56 45.08,32.56 45.14,32.5 45.14,31.75 45.2,31.69 45.32,31.69 45.38,31.75 45.38,32.5 45.44,32.56 45.56,32.56 45.62,32.5 45.62,32.27 45.68,32.21 46.1,32.21 46.61,31.7 47.11,31.7 47.63,32.22 48.09,32.22 48.15,32.28 48.15,32.5 48.21,32.56 48.33,32.56 48.39,32.5 48.39,31.75 48.45,31.69 48.57,31.69 48.63,31.75 48.63,32.5 48.69,32.56 48.81,32.56 48.87,32.5 48.87,31.75 48.93,31.69 49.05,31.69 49.11,31.75 49.11,32.5 49.17,32.56 49.29,32.56 49.35,32.5 49.35,31.75 49.41,31.69 49.53,31.69 49.59,31.75 49.59,32.16 49.65,32.22 50.31,32.22 50.83,31.7 51.28,31.7 51.79,32.21 52.69,32.21 52.75,32.15 52.75,31.75 52.81,31.69 52.93,31.69 52.99,31.75 52.99,32.5 53.05,32.56 53.17,32.56 53.23,32.5 53.23,31.75 53.29,31.69 53.41,31.69 53.47,31.75 53.47,32.5 53.53,32.56 53.65,32.56 53.71,32.5 53.71,31.75 53.77,31.69 53.89,31.69 53.95,31.75 53.95,32.5 54.01,32.56 54.13,32.56 54.19,32.5 54.19,32.27 54.29,32.17 55.23,32.17 55.5,32.44 56.375,32.44 56.45,32.44 56.562,32.552 56.562,32.67 56.674,32.783 56.824,32.783 56.936,32.67 56.936,32.44 57.016,32.36 57.23,32.36 57.31,32.44 57.31,32.67 57.422,32.783 57.572,32.783 57.684,32.67 57.684,32.44 57.764,32.36 57.978,32.36 58.058,32.44 58.058,32.67 58.17,32.783 58.32,32.783 58.432,32.67 58.432,32.44 58.432,32.145 58.544,32.033 58.694,32.033 58.806,32.145 58.806,32.44 58.806,32.67 58.918,32.783 59.068,32.783 59.18,32.67 59.18,32.44 59.18,32.17 59.292,32.057 59.442,32.057 59.554,32.17 59.554,32.44 59.554,32.67 59.666,32.783 59.816,32.783 59.928,32.67 59.928,32.552 60.04,32.44 61.96,32.44 62.15,32.25 62.15,31.95 61.95,31.75 v1(58.8,31.75)
  Bottom w0.12: v1(58.8,31.75) 59.24,31.75 59.38,31.61 59.38,31.156 59.144,30.92 58.7,30.92 58.644,30.864 58.644,30.736 58.7,30.68 59.7,30.68 59.76,30.62 59.76,30.5 59.7,30.44 59.05,30.44 58.875,30.265 58.875,30.05 58.875,29.825 58.875,29.75 58.987,29.638 59.807,29.638 59.919,29.526 59.919,29.376 59.807,29.264 58.987,29.264 58.875,29.152 58.875,28.975 58.875,27.8 58.875,27.461 59.05,27.286 U19.24@59.05,25.298
LCD_B4: U5.C7 U19.25 | length 57.9
  Top w0.12: U5.C7@40,36.05 v1(40.4,36.45)
  F5 w0.12: v1(40.4,36.45) 40.65,36.45 41.05,36.05 42.95,36.05 43.3,36.4 44,36.4 44.9,35.5 50.85,35.5 51.55,36.2 53.35,36.2 53.85,35.7 55.44,35.7 55.87,36.13 59.09,36.13 59.45,36.49 v1(59.45,37.55)
  Bottom w0.12: U19.25@58.225,25.323 58.225,32.365 58.77,32.91 59.61,32.91 59.81,32.71 59.81,31.31 60.22,30.9 61.84,30.9 62.59,31.65 62.59,32.77 62.32,33.04 61.34,33.04 61.07,33.31 61.07,35.15 61.19,35.27 62.24,35.27 62.45,35.48 62.45,36.36 62.31,36.5 61.04,36.5 60.98,36.56 60.98,36.68 61.04,36.74 62.36,36.74 62.42,36.8 62.42,36.92 62.36,36.98 61.04,36.98 60.98,37.04 60.98,37.16 61.04,37.22 62.36,37.22 62.42,37.28 62.42,37.4 62.36,37.46 61.04,37.46 60.98,37.52 60.98,37.64 61.04,37.7 62.36,37.7 62.42,37.76 62.42,37.88 62.36,37.94 61.76,37.94 61.7,38 61.7,38.66 61.27,39.09 59.68,39.09 59.45,38.86 v1(59.45,37.55)
LCD_B5: U5.D7 U19.26 | length 57.9
  Top w0.12: U5.D7@39.2,36.05 v1(39.6,36.45)
  F5 w0.12: v1(39.6,36.45) 40,36.05 40.6,36.05 40.9,35.75 41.05,35.75 41.215,35.75 41.275,35.81 41.529,35.81 41.589,35.75 41.589,35.552 41.701,35.44 41.851,35.44 41.963,35.552 41.963,35.638 42.075,35.75 42.15,35.75 42.35,35.75 42.525,35.575 42.578,35.522 42.737,35.522 42.833,35.618 42.991,35.618 43.097,35.512 43.097,35.354 42.922,35.178 42.921,35.177 42.921,35.019 43.026,34.913 43.185,34.913 43.187,34.913 43.35,34.75 43.45,34.65 43.925,34.65 44,34.65 44.112,34.762 44.112,34.881 44.224,34.993 44.374,34.993 44.486,34.881 44.486,34.762 44.598,34.65 44.748,34.65 44.86,34.762 44.86,35.148 44.972,35.26 45.122,35.26 45.234,35.148 45.234,34.762 45.346,34.65 45.496,34.65 45.608,34.762 45.608,35.148 45.72,35.26 45.87,35.26 45.982,35.148 45.982,34.762 46.094,34.65 46.275,34.65 47.15,34.65 47.53,35.03 48.32,35.03 48.38,35.09 48.38,35.2 48.44,35.26 48.56,35.26 48.62,35.2 48.62,34.85 48.68,34.79 48.8,34.79 48.86,34.85 48.86,35.2 48.92,35.26 49.04,35.26 49.1,35.2 49.1,34.85 49.16,34.79 49.28,34.79 49.34,34.85 49.34,35.2 49.4,35.26 49.52,35.26 49.58,35.2 49.58,34.85 49.64,34.79 49.76,34.79 49.82,34.85 49.82,35.2 49.88,35.26 50,35.26 50.06,35.2 50.06,34.85 50.12,34.79 50.24,34.79 50.3,34.85 50.3,35.2 50.36,35.26 50.48,35.26 50.54,35.2 50.54,34.85 50.6,34.79 50.72,34.79 50.78,34.85 50.78,35.2 50.84,35.26 50.96,35.26 51.02,35.2 51.02,34.85 51.08,34.79 51.2,34.79 51.26,34.85 51.26,35.2 51.32,35.26 51.44,35.26 51.5,35.2 51.5,34.85 51.56,34.79 51.68,34.79 51.74,34.85 51.74,35.2 51.8,35.26 51.92,35.26 51.98,35.2 51.98,34.85 52.04,34.79 52.16,34.79 52.22,34.85 52.22,35.2 52.28,35.26 52.4,35.26 52.46,35.2 52.46,35.09 52.52,35.03 52.8,35.03 53.17,35.4 54.12,35.4 54.307,35.4 54.367,35.46 54.621,35.46 54.681,35.4 54.681,35.245 54.793,35.133 54.943,35.133 55.055,35.245 55.055,35.4 55.115,35.46 55.369,35.46 55.429,35.4 55.429,35.252 55.541,35.14 55.691,35.14 55.803,35.252 55.803,35.288 55.915,35.4 56.065,35.4 56.177,35.288 56.177,35.252 56.289,35.14 56.439,35.14 56.551,35.252 56.551,35.288 56.663,35.4 56.813,35.4 56.925,35.288 56.925,35.252 57.037,35.14 57.187,35.14 57.299,35.252 57.299,35.288 57.411,35.4 57.561,35.4 57.673,35.288 57.673,35.252 57.785,35.14 57.935,35.14 58.047,35.252 58.047,35.288 58.159,35.4 58.2,35.4 v1(58.75,35.4)
  Bottom w0.12: U19.26@57.425,25.323 57.425,26.435 57.985,26.995 57.985,27.182 57.985,27.556 57.985,27.818 57.873,27.93 57.466,27.93 57.354,28.042 57.354,28.192 57.466,28.304 57.873,28.304 57.985,28.416 57.985,28.566 57.873,28.678 57.466,28.678 57.354,28.79 57.354,28.94 57.466,29.052 57.873,29.052 57.985,29.164 57.985,29.314 57.873,29.426 57.466,29.426 57.354,29.538 57.354,29.688 57.466,29.8 57.873,29.8 57.985,29.912 57.985,30.062 57.873,30.174 57.466,30.174 57.354,30.286 57.354,30.436 57.466,30.548 57.873,30.548 57.985,30.66 57.985,30.81 57.873,30.922 57.466,30.922 57.354,31.034 57.354,31.184 57.466,31.296 57.873,31.296 57.985,31.408 57.985,31.558 57.873,31.67 57.466,31.67 57.354,31.782 57.354,31.932 57.466,32.044 57.873,32.044 57.985,32.156 57.985,32.35 57.985,32.418 57.915,32.489 57.451,32.489 57.31,32.63 57.31,32.75 57.37,32.81 58.26,32.81 58.32,32.87 58.32,32.99 58.26,33.05 57.375,33.05 57.325,33.1 57.325,33.295 57.38,33.35 58.26,33.35 58.32,33.41 58.32,33.53 58.26,33.59 57.37,33.59 57.31,33.65 57.31,33.77 57.37,33.83 58.26,33.83 58.32,33.89 58.32,34.01 58.26,34.07 57.37,34.07 57.31,34.13 57.31,34.25 57.37,34.31 58.26,34.31 58.32,34.37 58.32,34.49 58.26,34.55 57.37,34.55 57.31,34.61 57.31,34.73 57.37,34.79 58.14,34.79 v1(58.75,35.4)
LCD_B6: U5.C6 U19.27 | length 57.9
  Top w0.12: U5.C6@40,36.85 v1(40.4,37.25)
  F5 w0.12: v1(40.4,37.25) 40.8,36.85 42.35,36.85 42.55,36.65 44.69,36.65 44.75,36.59 44.75,35.99 44.81,35.93 44.93,35.93 44.99,35.99 44.99,37.31 45.05,37.37 45.17,37.37 45.23,37.31 45.23,35.99 45.29,35.93 45.41,35.93 45.47,35.99 45.47,37.31 45.53,37.37 45.65,37.37 45.71,37.31 45.71,36.71 45.77,36.65 47.73,36.65 47.79,36.71 47.79,37.1 47.85,37.16 47.97,37.16 48.03,37.1 48.03,35.99 48.09,35.93 48.21,35.93 48.27,35.99 48.27,37.1 48.33,37.16 48.45,37.16 48.51,37.1 48.51,35.99 48.57,35.93 48.69,35.93 48.75,35.99 48.75,37.1 48.81,37.16 48.93,37.16 48.99,37.1 48.99,35.99 49.05,35.93 49.17,35.93 49.23,35.99 49.23,37.1 49.29,37.16 49.41,37.16 49.47,37.1 49.47,36.71 49.53,36.65 49.71,36.65 49.99,36.93 51.02,36.93 51.45,36.5 53.58,36.5 53.64,36.44 53.64,36.31 53.7,36.25 53.82,36.25 53.88,36.31 53.88,36.45 53.94,36.51 54.06,36.51 54.12,36.45 54.12,36 54.18,35.94 54.3,35.94 54.36,36 54.36,36.45 54.42,36.51 54.54,36.51 54.6,36.45 54.6,36 54.66,35.94 54.78,35.94 54.84,36 54.84,36.44 54.9,36.5 57.24,36.5 57.47,36.73 57.47,37.67 57.78,37.98 57.99,37.98 58.05,37.92 58.05,37.32 58.11,37.26 58.23,37.26 58.29,37.32 58.29,37.92 58.35,37.98 58.47,37.98 58.53,37.92 58.53,37.32 58.59,37.26 58.71,37.26 58.77,37.32 58.77,37.92 58.83,37.98 59.97,37.98 60.21,37.74 60.21,36.05 60.06,35.9 v1(59.6,35.9)
  Bottom w0.12: U19.27@56.6,25.144 56.6,27.29 57.07,27.76 57.07,36.77 57.54,37.24 58.31,37.24 59.6,35.95 v1(59.6,35.9)
LCD_B7: U5.C5 U19.28 | length 57.9
  Top w0.12: U5.C5@40,37.65 v1(40.4,38.05)
  F5 w0.12: v1(40.4,38.05) 40.8,37.65 42.3,37.65 42.65,38 47.47,38 47.75,37.72 51.29,37.72 51.92,37.09 55.49,37.09 v1(55.8,37.4)
  Bottom w0.12: U19.28@55.8,25.348 55.8,27.836 55.656,27.98 55.42,27.98 55.36,28.04 55.36,28.16 55.42,28.22 56.66,28.22 56.72,28.28 56.72,28.4 56.66,28.46 55.42,28.46 55.36,28.52 55.36,28.64 55.42,28.7 56.66,28.7 56.72,28.76 56.72,28.88 56.66,28.94 55.42,28.94 55.36,29 55.36,29.12 55.42,29.18 56.66,29.18 56.72,29.24 56.72,29.36 56.66,29.42 56.064,29.42 56.004,29.48 56.004,29.66 56.064,29.72 56.66,29.72 56.72,29.78 56.72,29.9 56.66,29.96 55.42,29.96 55.36,30.02 55.36,30.14 55.42,30.2 56.66,30.2 56.72,30.26 56.72,30.38 56.66,30.44 55.35,30.44 55.29,30.5 55.29,30.62 55.35,30.68 56.66,30.68 56.72,30.74 56.72,30.86 56.66,30.92 56.064,30.92 56.004,30.98 56.004,31.16 55.944,31.22 55.35,31.22 55.29,31.28 55.29,31.4 55.35,31.46 56.66,31.46 56.72,31.52 56.72,31.64 56.66,31.7 55.35,31.7 55.29,31.76 55.29,31.88 55.35,31.94 56.66,31.94 56.72,32 56.72,32.12 56.66,32.18 55.07,32.18 54.73,32.52 54.73,33.99 54.94,34.2 55.66,34.2 55.72,34.26 55.72,34.38 55.66,34.44 54.35,34.44 54.29,34.5 54.29,34.62 54.35,34.68 55.66,34.68 55.72,34.74 55.72,34.86 55.66,34.92 54.52,34.92 54.46,34.98 54.46,35.1 54.52,35.16 55.66,35.16 55.72,35.22 55.72,35.34 55.66,35.4 54.34,35.4 54.28,35.46 54.28,35.58 54.34,35.64 54.94,35.64 55,35.7 55,37.2 55.2,37.4 v1(55.8,37.4)
LCD_BL_A: C64.1 C65.2 D5.2 U10.6 U19.2 | length 15.1
  Top w0.3: C64.1@69.923,21.43 C64.1@70,21.353 ; v1(73.95,20.8) 74.425,20.325 U10.6@75.075,20.325
  Top w0.5: C64.1@69.923,21.43 C64.1@70.17,21.43 ; D5.2@70,18.05 70,21.26 C64.1@70.17,21.43 ; C65.2@72.75,21.4 72.7,21.4 C65.2@72.67,21.43 ; v1(73.95,20.8) 73.95,21.35 73.87,21.43 C65.2@72.67,21.43 ; C64.1@70.17,21.43 C65.2@72.67,21.43
  Bottom w0.5: v1(73.95,20.8) 76.612,23.462 76.612,24.341 76.6,24.354 U19.2@76.6,25.25
LCD_BL_K: R75.2 U10.4 U19.1 | length 5.3
  Top w0.3: R75.2@77.734,23 R75.2@77.734,22.82 ; U10.4@77.925,20.975 77.925,21.815 77.734,22.006 R75.2@77.734,22.82 ; v1(78.15,25.2) 78.15,24.57 77.734,24.154 R75.2@77.734,22.82
  Bottom w0.3: U19.1@77.604,25.144 77.604,25.2 v1(78.15,25.2)
LCD_G0: U5.J12 U19.13 | length 58.1
  Top w0.12: v1(34.8,31.65) U5.J12@35.2,32.05
  F5 w0.12: v1(34.8,31.65) 34.4,31.25 33.75,31.25 33.6,31.1 33.6,30.1 33.6,29.948 33.688,29.86 33.8,29.748 33.8,29.598 33.688,29.486 33.6,29.398 33.6,29.112 33.6,28.925 33.6,28.75 34.2,28.15 34.2,26.75 34.8,26.15 41.041,26.15 42.851,24.34 45.154,24.34 45.664,24.85 50.05,24.85 51.02,23.88 59.45,23.88 59.7,23.63 59.7,23.625 59.72,23.605 59.72,22.59 59.78,22.53 59.9,22.53 59.96,22.59 59.96,23.85 60.02,23.91 60.14,23.91 60.2,23.85 60.2,22.59 60.26,22.53 60.38,22.53 60.44,22.59 60.44,23.85 60.5,23.91 60.62,23.91 60.68,23.85 60.68,22.59 60.74,22.53 60.86,22.53 60.92,22.59 60.92,23.85 60.98,23.91 61.1,23.91 61.16,23.85 61.16,22.59 61.22,22.53 61.34,22.53 61.4,22.59 61.4,23.85 61.46,23.91 61.58,23.91 61.64,23.85 61.64,22.59 61.7,22.53 61.82,22.53 61.88,22.59 61.88,23.85 61.94,23.91 62.06,23.91 62.12,23.85 62.12,23.31 62.18,23.25 65.225,23.25 65.393,23.25 65.503,23.14 65.657,23.14 65.767,23.25 65.767,23.35 65.879,23.462 66.029,23.462 66.141,23.35 66.241,23.25 66.515,23.25 66.889,23.25 67.263,23.25 67.45,23.25 v1(68,23.25)
  Bottom w0.12: U19.13@67.8,25.25 67.8,24.165 68.004,23.961 68.004,23.25 v1(68,23.25)
LCD_G1: U5.H12 U19.14 | length 58.4
  Top w0.12: v1(35.6,31.65) U5.H12@36,32.05
  F5 w0.12: v1(35.6,31.65) 34.4,30.45 34.4,28.8 34.45,28.75 34.45,27.3 35.35,26.4 41.2,26.4 43.02,24.58 45.055,24.58 45.575,25.1 50.24,25.1 51.22,24.12 58.6,24.12 58.82,24.34 63.19,24.34 63.19,23.74 63.25,23.68 63.37,23.68 63.43,23.74 63.43,24.81 63.49,24.87 63.61,24.87 63.67,24.81 63.67,23.74 63.73,23.68 63.85,23.68 63.91,23.74 63.91,24.81 63.97,24.87 64.09,24.87 64.15,24.81 64.15,23.74 64.21,23.68 64.33,23.68 64.39,23.74 64.39,24.81 64.45,24.87 64.57,24.87 64.63,24.81 64.63,23.74 64.69,23.68 64.81,23.68 64.87,23.74 64.87,24.81 64.93,24.87 65.05,24.87 65.11,24.81 65.11,23.74 65.17,23.68 65.29,23.68 65.35,23.74 65.35,24.81 65.41,24.87 65.53,24.87 65.59,24.81 65.59,23.74 65.65,23.68 65.77,23.68 65.83,23.74 65.83,24.81 65.89,24.87 66.01,24.87 66.07,24.81 66.07,23.74 66.13,23.68 66.25,23.68 66.31,23.74 66.31,24.376 67.204,25.27 v1(67.029,26.775)
  Bottom w0.12: U19.14@67.029,25.019 v1(67.029,26.775)
LCD_G2: U5.J13 U19.15 | length 58.1
  Top w0.12: U5.J13@35.2,31.25 v1(35.6,30.85)
  F5 w0.12: v1(35.6,30.85) 35.2,30.45 35.2,28.95 35.4,28.75 35.4,26.95 35.7,26.65 43.361,26.65 43.878,26.132 44.328,26.132 45.1,25.361 45.1,25.35 50.45,25.35 51.02,24.78 51.53,24.78 51.59,24.84 51.59,25.3 51.65,25.36 51.77,25.36 51.83,25.3 51.83,24.42 51.89,24.36 52.01,24.36 52.07,24.42 52.07,25.3 52.13,25.36 52.25,25.36 52.31,25.3 52.31,24.42 52.37,24.36 52.49,24.36 52.55,24.42 52.55,25.3 52.61,25.36 52.73,25.36 52.79,25.3 52.79,24.42 52.85,24.36 52.97,24.36 53.03,24.42 53.03,25.3 53.09,25.36 53.21,25.36 53.27,25.3 53.27,24.42 53.33,24.36 53.45,24.36 53.51,24.42 53.51,25.21 53.57,25.27 53.69,25.27 53.75,25.21 53.75,24.42 53.81,24.36 53.93,24.36 53.99,24.42 53.99,25.16 54.05,25.22 54.17,25.22 54.23,25.16 54.23,24.42 54.29,24.36 54.41,24.36 54.47,24.42 54.47,25.16 54.53,25.22 54.65,25.22 54.71,25.16 54.71,24.42 54.77,24.36 54.89,24.36 54.95,24.42 54.95,25.16 55.01,25.22 55.13,25.22 55.19,25.16 55.19,24.42 55.25,24.36 55.37,24.36 55.43,24.42 55.43,25.16 55.49,25.22 55.61,25.22 55.67,25.16 55.67,24.42 55.73,24.36 55.85,24.36 55.91,24.42 55.91,25.16 55.97,25.22 56.09,25.22 56.15,25.16 56.15,24.42 56.21,24.36 56.33,24.36 56.39,24.42 56.39,25.16 56.45,25.22 56.57,25.22 56.63,25.16 56.63,24.42 56.69,24.36 56.81,24.36 56.87,24.42 56.87,24.72 56.93,24.78 62.7,24.78 63.07,25.15 65.524,25.15 66.404,26.03 v1(66.204,26.8)
  Bottom w0.12: U19.15@66.204,25.144 v1(66.204,26.8)
LCD_G3: U5.H13 U19.16 | length 58.1
  Top w0.12: U5.H13@36,31.25 v1(36.4,30.85)
  F5 w0.12: v1(36.4,30.85) 36,30.45 36,29.05 35.65,28.7 35.65,27.55 36.3,26.9 43.45,26.9 43.978,26.372 44.728,26.372 45,26.1 45,25.8 45.2,25.6 53.6,25.6 53.66,25.66 53.66,25.97 53.72,26.03 53.84,26.03 53.9,25.97 53.9,25.52 53.96,25.46 54.08,25.46 54.14,25.52 54.14,25.97 54.2,26.03 54.32,26.03 54.38,25.97 54.38,25.52 54.44,25.46 54.56,25.46 54.62,25.52 54.62,25.97 54.68,26.03 54.8,26.03 54.86,25.97 54.86,25.52 54.92,25.46 55.04,25.46 55.1,25.52 55.1,25.97 55.16,26.03 55.28,26.03 55.34,25.97 55.34,25.52 55.4,25.46 55.52,25.46 55.58,25.52 55.58,25.97 55.64,26.03 55.76,26.03 55.82,25.97 55.82,25.52 55.88,25.46 56,25.46 56.06,25.52 56.06,25.97 56.12,26.03 56.24,26.03 56.3,25.97 56.3,25.52 56.36,25.46 56.48,25.46 56.54,25.52 56.54,25.97 56.6,26.03 56.72,26.03 56.78,25.97 56.78,25.41 56.84,25.35 56.96,25.35 57.02,25.41 57.02,25.97 57.08,26.03 57.2,26.03 57.26,25.97 57.26,25.17 57.32,25.11 57.44,25.11 57.5,25.17 57.5,25.97 57.56,26.03 57.68,26.03 57.74,25.97 57.74,25.17 57.8,25.11 57.92,25.11 57.98,25.17 57.98,25.97 58.04,26.03 58.16,26.03 58.22,25.97 58.22,25.17 58.28,25.11 58.4,25.11 58.46,25.17 58.46,25.97 58.52,26.03 58.64,26.03 58.7,25.97 58.7,25.17 58.76,25.11 58.88,25.11 58.94,25.17 58.94,25.97 59,26.03 59.12,26.03 59.18,25.97 59.18,25.17 59.24,25.11 59.36,25.11 59.42,25.17 59.42,25.97 59.48,26.03 59.6,26.03 59.66,25.97 59.66,25.17 59.72,25.11 59.84,25.11 59.9,25.17 59.9,25.54 59.96,25.6 60.68,25.6 60.88,25.4 64.046,25.4 64.193,25.548 64.193,25.633 64.05,25.776 64.05,25.861 64.135,25.946 64.22,25.946 64.733,25.432 64.818,25.432 64.903,25.517 64.903,25.602 64.39,26.115 64.39,26.2 64.474,26.285 64.559,26.285 65.212,25.633 65.297,25.633 65.381,25.718 65.381,25.802 64.957,26.227 64.957,26.311 65.446,26.8 v1(65.6,26.8)
  Bottom w0.12: U19.16@65.425,25.323 65.425,26.625 v1(65.6,26.8)
LCD_G4: U5.G12 U19.17 | length 57.9
  Top w0.12: v1(36.4,32.45) U5.G12@36.8,32.05
  F5 w0.12: v1(36.4,32.45) 36.8,32.05 36.8,30.65 36.3,30.15 36.3,28.65 36.85,28.1 36.85,27.65 37.35,27.15 43.55,27.15 43.87,26.83 43.87,26.823 44.08,26.612 45.157,26.612 45.24,26.53 45.24,25.95 45.3,25.89 45.42,25.89 45.48,25.95 45.48,26.53 45.54,26.59 45.66,26.59 45.72,26.53 45.72,25.95 45.78,25.89 45.9,25.89 45.96,25.95 45.96,26.53 46.02,26.59 46.14,26.59 46.2,26.53 46.2,25.95 46.26,25.89 46.38,25.89 46.44,25.95 46.44,26.53 46.5,26.59 46.62,26.59 46.68,26.53 46.68,25.95 46.74,25.89 46.86,25.89 46.92,25.95 46.92,26.53 46.98,26.59 47.1,26.59 47.16,26.53 47.16,25.95 47.22,25.89 47.34,25.89 47.4,25.95 47.4,26.53 47.46,26.59 47.58,26.59 47.64,26.53 47.64,25.95 47.7,25.89 47.82,25.89 47.88,25.95 47.88,26.53 47.94,26.59 48.06,26.59 48.12,26.53 48.12,25.95 48.18,25.89 48.3,25.89 48.36,25.95 48.36,26.53 48.42,26.59 48.54,26.59 48.6,26.53 48.6,25.95 48.66,25.89 48.78,25.89 48.84,25.95 48.84,26.53 48.9,26.59 49.02,26.59 49.08,26.53 49.08,25.95 49.14,25.89 49.26,25.89 49.32,25.95 49.32,26.53 49.38,26.59 49.5,26.59 49.56,26.53 49.56,25.95 49.62,25.89 49.74,25.89 49.8,25.95 49.8,26.53 49.86,26.59 49.98,26.59 50.04,26.53 50.04,25.95 50.1,25.89 50.22,25.89 50.28,25.95 50.28,26.53 50.34,26.59 50.46,26.59 50.52,26.53 50.52,25.95 50.58,25.89 50.7,25.89 50.76,25.95 50.76,26.53 50.82,26.59 50.94,26.59 51,26.53 51,25.95 51.06,25.89 51.18,25.89 51.24,25.95 51.24,26.53 51.3,26.59 51.42,26.59 51.48,26.53 51.48,25.95 51.54,25.89 51.66,25.89 51.72,25.95 51.72,26.53 51.78,26.59 51.9,26.59 51.96,26.53 51.96,25.95 52.02,25.89 52.14,25.89 52.2,25.95 52.2,26.53 52.26,26.59 52.38,26.59 52.44,26.53 52.44,25.95 52.5,25.89 52.62,25.89 52.68,25.95 52.68,26.53 52.74,26.59 52.86,26.59 52.92,26.53 52.92,26.33 52.98,26.27 53.8,26.27 53.875,26.27 53.987,26.382 53.987,26.566 54.099,26.678 54.249,26.678 54.361,26.566 54.361,26.382 54.473,26.27 54.623,26.27 54.735,26.382 54.735,26.408 54.847,26.52 54.997,26.52 55.109,26.408 55.109,26.382 55.221,26.27 55.371,26.27 55.483,26.382 55.483,26.448 55.595,26.56 55.745,26.56 55.857,26.448 55.857,26.382 55.969,26.27 56.05,26.27 60.77,26.27 61.34,25.7 63.55,25.7 v1(64.65,26.8)
  Bottom w0.12: U19.17@64.65,25.298 v1(64.65,26.8)
LCD_G5: U5.G13 U19.18 | length 57.9
  Top w0.12: U5.G13@36.8,31.25 v1(37.2,30.85)
  F5 w0.12: v1(37.2,30.85) 37.2,30.7 36.56,30.06 36.56,28.74 36.95,28.35 37.85,28.35 38.8,27.4 52.6,27.4 52.72,27.52 52.99,27.52 53.05,27.58 53.05,27.81 53.11,27.87 53.23,27.87 53.29,27.81 53.29,26.86 53.35,26.8 53.47,26.8 53.53,26.86 53.53,27.81 53.59,27.87 53.71,27.87 53.77,27.81 53.77,27.44 53.83,27.38 53.95,27.38 54.01,27.44 54.01,27.81 54.07,27.87 54.19,27.87 54.25,27.81 54.25,27.3 54.31,27.24 54.43,27.24 54.49,27.3 54.49,27.81 54.55,27.87 54.67,27.87 54.73,27.81 54.73,27.27 54.79,27.21 54.833,27.21 54.853,27.23 54.93,27.23 54.97,27.27 54.97,27.81 55.03,27.87 55.15,27.87 55.21,27.81 55.21,27.34 55.27,27.28 55.39,27.28 55.45,27.34 55.45,27.81 55.51,27.87 55.63,27.87 55.69,27.81 55.69,26.86 55.75,26.8 55.87,26.8 55.93,26.86 55.93,27.81 55.99,27.87 56.11,27.87 56.17,27.81 56.17,26.86 56.23,26.8 56.35,26.8 56.41,26.86 56.41,27.81 56.47,27.87 56.59,27.87 56.65,27.81 56.65,26.86 56.71,26.8 56.83,26.8 56.89,26.86 56.89,27.81 56.95,27.87 57.07,27.87 57.13,27.81 57.13,26.86 57.19,26.8 57.31,26.8 57.37,26.86 57.37,27.81 57.43,27.87 57.55,27.87 57.61,27.81 57.61,26.86 57.67,26.8 57.79,26.8 57.85,26.86 57.85,27.81 57.91,27.87 58.03,27.87 58.09,27.81 58.09,26.86 58.15,26.8 58.27,26.8 58.33,26.86 58.33,27.81 58.39,27.87 58.51,27.87 58.57,27.81 58.57,26.86 58.63,26.8 58.75,26.8 58.81,26.86 58.81,27.81 58.87,27.87 58.99,27.87 59.05,27.81 59.05,26.86 59.11,26.8 59.23,26.8 59.29,26.86 59.29,27.81 59.35,27.87 59.47,27.87 59.53,27.81 59.53,26.86 59.59,26.8 59.71,26.8 59.77,26.86 59.77,27.46 59.83,27.52 60.01,27.52 60.218,27.312 60.302,27.312 60.365,27.375 60.45,27.375 60.535,27.291 60.535,27.206 60.472,27.143 60.472,27.058 60.557,26.973 60.642,26.973 60.705,27.036 60.79,27.036 60.875,26.951 60.875,26.866 60.812,26.803 60.812,26.718 61.58,25.95 62.85,25.95 v1(63.75,26.85)
  Bottom w0.12: U19.18@63.75,25.398 v1(63.75,26.85)
LCD_G6: U5.F12 U19.19 | length 58
  Top w0.12: v1(37.2,32.45) U5.F12@37.6,32.05
  F5 w0.12: v1(37.2,32.45) 37.6,32.05 42.6,32.05 43.45,31.2 48.81,31.2 49.18,30.83 49.6,30.83 49.66,30.77 49.66,30.7 49.72,30.64 49.84,30.64 49.9,30.7 49.9,31.15 49.96,31.21 50.08,31.21 50.14,31.15 50.14,30.7 50.2,30.64 50.32,30.64 50.38,30.7 50.38,31.15 50.44,31.21 50.56,31.21 50.62,31.15 50.62,30.7 50.68,30.64 50.8,30.64 50.86,30.7 50.86,31.15 50.92,31.21 51.04,31.21 51.1,31.15 51.1,30.7 51.16,30.64 51.28,30.64 51.34,30.7 51.34,31.15 51.4,31.21 51.52,31.21 51.58,31.15 51.58,30.7 51.64,30.64 51.76,30.64 51.82,30.7 51.82,31.15 51.88,31.21 52,31.21 52.06,31.15 52.06,30.7 52.12,30.64 52.24,30.64 52.3,30.7 52.3,31.15 52.36,31.21 52.48,31.21 52.54,31.15 52.54,30.7 52.6,30.64 52.72,30.64 52.78,30.7 52.78,31.15 52.84,31.21 52.96,31.21 53.02,31.15 53.02,30.7 53.08,30.64 53.2,30.64 53.26,30.7 53.26,31.15 53.32,31.21 53.44,31.21 53.5,31.15 53.5,30.7 53.56,30.64 53.68,30.64 53.74,30.7 53.74,31.15 53.8,31.21 53.92,31.21 53.98,31.15 53.98,30.7 54.04,30.64 54.16,30.64 54.22,30.7 54.22,31.15 54.28,31.21 54.4,31.21 54.46,31.15 54.46,30.7 54.52,30.64 54.64,30.64 54.7,30.7 54.7,31.15 54.76,31.21 54.88,31.21 54.94,31.15 54.94,30.7 55,30.64 55.12,30.64 55.18,30.7 55.18,31.15 55.75,31.72 57.63,31.72 58.52,30.83 66.3,30.83 66.45,30.98 66.45,31.68 66.23,31.9 65.64,31.9 65.27,32.27 65.27,32.72 65.65,33.1 v1(67.25,33.1)
  Bottom w0.12: U19.19@63.01,25.338 63.01,27.61 64.65,29.25 66.28,29.25 67.28,30.25 67.28,33.1 v1(67.25,33.1)
LCD_G7: U5.F13 U19.20 | length 57.9
  Top w0.12: U5.F13@37.6,31.25 v1(38,30.85)
  F5 w0.12: v1(38,30.85) 37.6,30.45 37.6,29 37.75,28.85 38.05,28.85 38.3,28.6 42.98,28.6 43.04,28.54 43.04,28.06 43.1,28 43.22,28 43.28,28.06 43.28,29.11 43.34,29.17 43.46,29.17 43.52,29.11 43.52,27.95 43.58,27.89 43.7,27.89 43.76,27.95 43.76,29.11 43.82,29.17 43.94,29.17 44,29.11 44,27.95 44.06,27.89 44.18,27.89 44.24,27.95 44.24,29.11 44.3,29.17 44.42,29.17 44.48,29.11 44.48,27.95 44.54,27.89 44.66,27.89 44.72,27.95 44.72,29.11 44.78,29.17 44.9,29.17 44.96,29.11 44.96,27.95 45.02,27.89 45.14,27.89 45.2,27.95 45.2,29.11 45.26,29.17 45.38,29.17 45.44,29.11 45.44,27.95 45.5,27.89 45.62,27.89 45.68,27.95 45.68,29.11 45.74,29.17 45.86,29.17 46.23,28.8 46.23,28.45 46.65,28.03 47.03,28.03 47.07,28.07 47.07,28.57 47.13,28.63 47.25,28.63 47.31,28.57 47.31,27.95 47.37,27.89 47.49,27.89 47.55,27.95 47.55,28.57 47.61,28.63 47.73,28.63 47.79,28.57 47.79,27.95 47.85,27.89 47.97,27.89 48.03,27.95 48.03,28.57 48.09,28.63 48.21,28.63 48.27,28.57 48.27,27.95 48.33,27.89 48.45,27.89 48.51,27.95 48.51,28.57 48.57,28.63 48.69,28.63 48.75,28.57 48.75,27.95 48.81,27.89 48.93,27.89 48.99,27.95 48.99,28.57 49.05,28.63 49.17,28.63 49.23,28.57 49.23,27.95 49.29,27.89 49.41,27.89 49.47,27.95 49.47,28.57 49.53,28.63 49.65,28.63 49.71,28.57 49.71,27.95 49.77,27.89 49.89,27.89 49.95,27.95 49.95,28.57 50.01,28.63 50.13,28.63 50.19,28.57 50.19,27.95 50.25,27.89 50.37,27.89 50.43,27.95 50.43,28.57 50.49,28.63 50.61,28.63 50.67,28.57 50.67,27.95 50.73,27.89 50.85,27.89 50.91,27.95 50.91,28.57 50.97,28.63 51.09,28.63 51.15,28.57 51.15,27.95 51.21,27.89 51.33,27.89 51.39,27.95 51.39,28.57 51.45,28.63 51.57,28.63 51.63,28.57 51.63,27.95 51.69,27.89 51.81,27.89 51.87,27.95 51.87,28.29 51.93,28.35 60.95,28.35 v1(62.4,26.9)
  Bottom w0.12: U19.20@62.2,25.25 62.2,26.7 v1(62.4,26.9) ; U19.20@62.4,25.148 U19.20@62.404,25.144
LCD_R0: U5.G4 U19.5 | length 57.7
  Top w0.12: v1(36.4,38.85) U5.G4@36.8,38.45
  F5 w0.12: v1(36.4,38.85) 36.8,39.25 36.8,39.9 36.95,40.05 42.4,40.05 42.95,40.6 45.85,40.6 46.35,40.1 47.25,40.1 47.35,40 58.3,40 58.95,39.35 65.75,39.35 66.25,39.85 v1(66.25,40)
  Bottom w0.12: v1(66.25,40) 67.1,40 68.05,39.05 71.55,39.05 73.05,37.55 73.05,34.95 74.1,33.9 74.1,32.71 74.16,32.65 74.79,32.65 74.85,32.59 74.85,32.46 74.79,32.4 73.8,32.4 73.75,32.35 73.75,32.22 73.82,32.15 74.79,32.15 74.85,32.09 74.85,31.96 74.79,31.9 73.91,31.9 73.85,31.84 73.85,31.71 73.91,31.65 74.34,31.65 74.4,31.59 74.4,31.46 74.34,31.4 73.91,31.4 73.85,31.34 73.85,31.04 74.25,30.64 U19.5@74.25,25.298
LCD_R1: U5.R6 U19.6 | length 58
  Top w0.12: v1(30,37.25) U5.R6@30.4,36.85
  F5 w0.12: v1(30,37.25) 30.4,37.65 35.05,37.65 35.2,37.8 35.2,40.6 35.45,40.85 45.95,40.85 46.45,40.35 58.85,40.35 v1(59.25,40.75)
  Bottom w0.12: v1(59.25,40.75) 64.62,40.75 73.6,31.77 73.6,26.579 73.4,26.379 U19.6@73.4,25.25
LCD_R2: U5.R7 U19.7 | length 58.1
  Top w0.12: v1(30,36.45) U5.R7@30.4,36.05
  F5 w0.12: v1(30,36.45) 30,35.7 31.25,34.45 34.1,34.45 34.35,34.7 34.75,34.7 34.937,34.7 35.199,34.7 35.311,34.588 35.311,34.395 35.423,34.283 35.573,34.283 35.685,34.395 35.685,34.588 35.797,34.7 36.025,34.7 42.2,34.7 43.6,33.3 53.6,33.3 54.25,33.95 55.24,33.95 55.55,34.26 67.9,34.26 69.46,32.7 71.84,32.7 72.8,31.74 v1(72.8,30.9)
  Bottom w0.12: U19.7@72.65,25.298 72.65,27.41 72.25,27.81 72.25,27.94 72.31,28 73.19,28 73.25,28.06 73.25,28.19 73.19,28.25 72.31,28.25 72.25,28.31 72.25,28.44 72.31,28.5 73.19,28.5 73.25,28.56 73.25,28.69 73.19,28.75 72.31,28.75 72.25,28.81 72.25,28.94 72.31,29 72.744,29 72.804,29.06 72.804,30.9 v1(72.8,30.9)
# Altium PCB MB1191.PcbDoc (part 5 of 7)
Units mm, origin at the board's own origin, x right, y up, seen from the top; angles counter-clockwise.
Board outline 130 x 80 mm, 8 copper layers (Top, F2, F3, F4, F5, F6, F7, Bottom), stack 1.115 mm thick; 360 components, 347 nets, 1451 pads, 1068 vias.

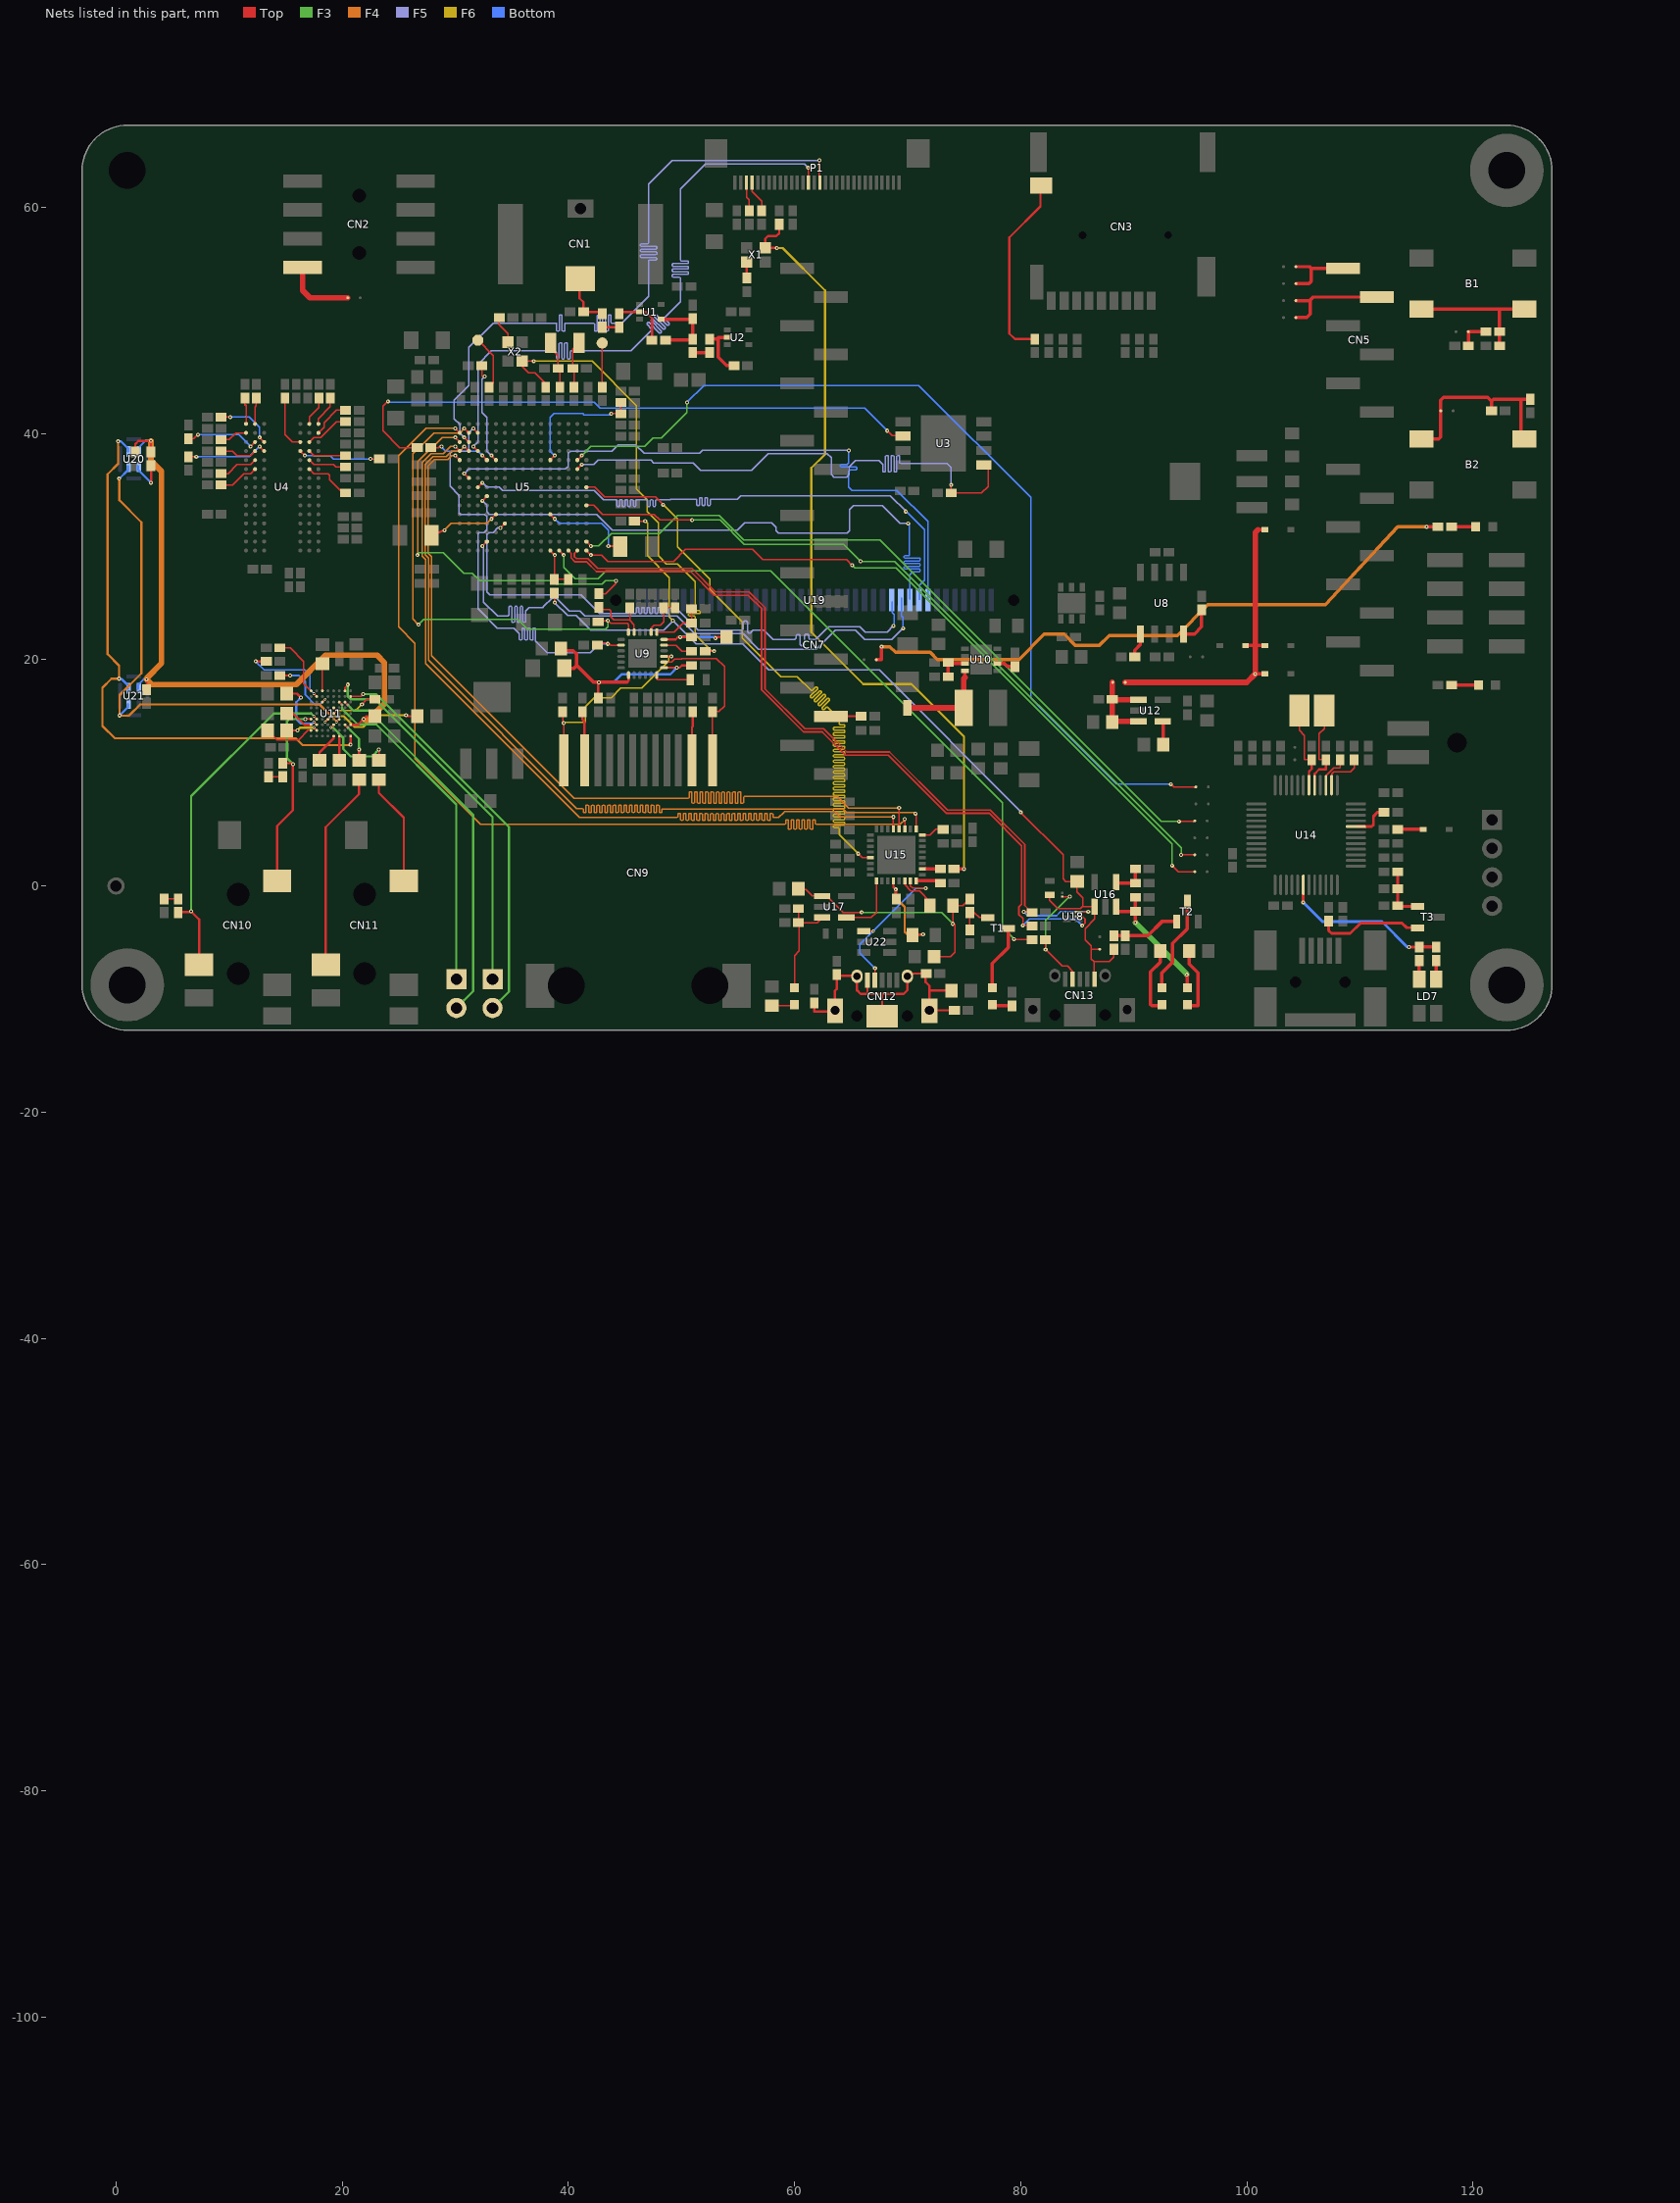
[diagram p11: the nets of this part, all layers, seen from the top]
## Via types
v1: diameter 0.35, hole 0.15, Top to Bottom, tented both sides, 1041 vias
v2: diameter 0.25, hole 0.1, Top to Bottom, tented both sides, 26 vias
v3: diameter 0.3, hole 0.1, Top to Bottom, tented both sides, 1 vias

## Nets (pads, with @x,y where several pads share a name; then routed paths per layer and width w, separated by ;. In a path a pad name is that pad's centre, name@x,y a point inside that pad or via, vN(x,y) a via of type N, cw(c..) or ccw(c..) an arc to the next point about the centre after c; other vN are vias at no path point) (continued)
LCD_R3: U5.P7 U19.8 | length 57.7
  Top w0.12: v1(30.8,36.45) U5.P7@31.2,36.05
  F5 w0.12: v1(30.8,36.45) 31.2,36.85 39.75,36.85 40,37.1 40,38.25 40.2,38.45 43.85,38.45 44.4,39 45.95,39 46.7,38.25 51.61,38.25 51.87,38.51 64.8,38.51 v1(64.8,38.5)
  Bottom w0.12: v1(64.8,38.5) 64.79,38.49 64.79,37.4 64.66,37.27 64.13,37.27 64.07,37.21 64.07,37.09 64.13,37.03 65.45,37.03 65.51,36.97 65.51,36.85 65.45,36.79 64.92,36.79 64.79,36.66 64.79,35.25 65.07,34.97 69.05,34.97 71.8,32.22 U19.8@71.8,25.348
LCD_R4: U5.N8 U19.9 | length 58.1
  Top w0.12: U5.N8@32,35.25 32.375,35.625 32.4,35.6 v1(32.4,35.65)
  F5 w0.12: v1(32.4,35.65) 32.8,35.25 33.9,35.25 34.2,34.95 42.3,34.95 43.1,34.15 44.24,34.15 44.3,34.09 44.3,33.6 44.36,33.54 44.48,33.54 44.54,33.6 44.54,34.09 44.6,34.15 44.72,34.15 44.78,34.09 44.78,33.6 44.84,33.54 44.96,33.54 45.02,33.6 45.02,34.09 45.08,34.15 45.2,34.15 45.26,34.09 45.26,33.6 45.32,33.54 45.44,33.54 45.5,33.6 45.5,34.09 45.56,34.15 45.68,34.15 45.74,34.09 45.74,33.6 45.8,33.54 45.92,33.54 45.98,33.6 45.98,34.09 46.04,34.15 46.94,34.15 47,34.09 47,33.6 47.06,33.54 47.18,33.54 47.24,33.6 47.24,34.09 47.3,34.15 47.42,34.15 47.48,34.09 47.48,33.6 47.54,33.54 47.66,33.54 47.72,33.6 47.72,34.09 47.78,34.15 49,34.15 49.05,34.2 51.3,34.2 51.36,34.14 51.36,33.69 51.42,33.63 51.54,33.63 51.6,33.69 51.6,34.25 51.66,34.31 51.78,34.31 51.84,34.25 51.84,33.69 51.9,33.63 52.02,33.63 52.08,33.69 52.08,34.25 52.14,34.31 52.26,34.31 52.32,34.25 52.32,33.69 52.38,33.63 52.5,33.63 52.56,33.69 52.56,34.14 52.62,34.2 54.95,34.2 55.25,34.5 68.48,34.5 69.88,33.1 v1(69.85,33.1)
  Bottom w0.12: v1(69.85,33.1) 69.9,33.1 71.5,31.5 71.5,27.046 71.05,26.596 U19.9@71.05,25.298
LCD_R5: U5.M9 U19.10 | length 58
  Top w0.12: v1(32.4,34.05) U5.M9@32.8,34.45
  F5 w0.12: v1(32.4,34.05) 32.8,33.65 32.8,33.08 33.03,32.85 42.5,32.85 43.9,31.45 54.94,31.45 55.61,32.12 57.96,32.12 58.38,31.7 58.38,31.4 58.6,31.18 64.66,31.18 64.87,31.39 64.87,33.26 65.23,33.62 67.77,33.62 69.34,32.05 v1(70.05,32.05)
  Bottom w0.12: v1(70.05,32.05) 70.14,32.05 70.14,29.22 69.75,29.22 69.69,29.16 69.69,29.04 69.75,28.98 71.06,28.98 71.12,28.92 71.12,28.8 71.06,28.74 69.75,28.74 69.69,28.68 69.69,28.56 69.75,28.5 71.06,28.5 71.12,28.44 71.12,28.32 71.06,28.26 69.75,28.26 69.69,28.2 69.69,28.08 69.75,28.02 71.06,28.02 71.12,27.96 71.12,27.84 71.06,27.78 70.464,27.78 70.2,27.516 U19.10@70.2,25.348
LCD_R6: U5.M14 U19.11 | length 58.3
  Top w0.12: v1(32.4,30.05) U5.M14@32.8,30.45
  F5 w0.12: v1(32.4,30.05) 32.5,29.95 32.5,25.1 33.75,23.85 34.65,23.85 34.77,23.97 34.77,24.66 34.83,24.72 34.95,24.72 35.01,24.66 35.01,23.35 35.07,23.29 35.19,23.29 35.25,23.35 35.25,24.67 35.31,24.73 35.43,24.73 35.49,24.67 35.49,23.35 35.55,23.29 35.67,23.29 35.73,23.35 35.73,24.67 35.79,24.73 35.91,24.73 35.97,24.67 35.97,23.35 36.03,23.29 36.15,23.29 36.21,23.35 36.21,24.29 36.54,24.62 37.74,24.62 37.84,24.72 38.57,25.45 38.95,25.45 40.1,24.3 41.05,24.3 41.49,23.86 49.62,23.86 51.18,22.3 55.46,22.3 56.82,20.94 61.94,20.94 63.6,22.6 65.4,22.6 66.2,21.8 68.6,21.8 69.58,22.78 v1(69.604,22.78)
  Bottom w0.12: U19.11@69.45,25.475 69.45,23.878 69.604,23.724 v1(69.604,22.78)
LCD_R7: U5.K12 U19.12 | length 58
  Top w0.12: v1(34,31.65) U5.K12@34.4,32.05
  F5 w0.12: v1(34,31.65) 33.75,31.65 33.35,31.25 33,31.25 32.8,31.05 32.8,26.01 33.07,25.74 41.112,25.74 41.605,25.247 41.605,25.245 42.75,24.1 45.94,24.1 46,24.16 46,24.55 46.06,24.61 46.18,24.61 46.24,24.55 46.24,24.16 46.3,24.1 46.42,24.1 46.48,24.16 46.48,24.55 46.54,24.61 46.66,24.61 46.72,24.55 46.72,24.16 46.78,24.1 46.9,24.1 46.96,24.16 46.96,24.55 47.02,24.61 47.14,24.61 47.2,24.55 47.2,24.16 47.26,24.1 47.38,24.1 47.44,24.16 47.44,24.55 47.5,24.61 47.62,24.61 47.68,24.55 47.68,24.16 47.74,24.1 47.86,24.1 47.92,24.16 47.92,24.55 47.98,24.61 48.1,24.61 48.16,24.55 48.16,24.16 48.22,24.1 48.34,24.1 48.4,24.16 48.4,24.55 48.46,24.61 48.58,24.61 48.64,24.55 48.64,24.16 48.7,24.1 48.82,24.1 48.88,24.16 48.88,24.55 48.94,24.61 49.06,24.61 49.12,24.55 49.12,24.35 49.18,24.29 49.81,24.29 51.5,22.6 53.875,22.6 54.775,22.6 54.9,22.6 55.353,22.6 55.465,22.712 55.465,23.315 55.577,23.427 55.727,23.427 55.839,23.315 55.839,22.6 55.839,22.473 55.951,22.361 56.101,22.361 56.213,22.473 56.213,22.488 56.325,22.6 56.4,22.6 57.3,22.6 58.1,21.8 59.95,21.8 60.025,21.8 60.137,21.912 60.137,22.128 60.249,22.24 60.399,22.24 60.511,22.128 60.511,21.8 60.511,21.342 60.623,21.23 60.773,21.23 60.885,21.342 60.885,21.8 60.885,22.139 60.997,22.251 61.147,22.251 61.259,22.139 61.259,21.912 61.371,21.8 61.375,21.8 61.9,21.8 63,22.9 65.8,22.9 66.26,22.44 68.19,22.44 v1(68.75,23)
  Bottom w0.12: U19.12@68.628,25.138 68.628,24.172 68.804,23.996 68.804,23.054 v1(68.75,23)
LED_STLINK: R138.1 R139.2 U14.30 | length 14.9
  Top w0.25: v1(105,-1.45) U14.30@105,0.1 ; v1(114.35,-5.4) R138.1@115.25,-5.4
  Top w0.3: R138.1@115.25,-5.4 R139.2@116.75,-5.4
  Bottom w0.25: v1(105,-1.45) 106.7,-3.15 111.95,-3.15 114.2,-5.4 v1(114.35,-5.4)
MIC_CLK: U11.C6 U20.3 U21.3 | length 45.9
  Top w0.12: v2(19.5,14.5) U11.C6@19.75,14.75
  F4 w0.2: v1(0.29,36.01) 0.29,34.11 2.25,32.15 2.25,18.8 0.32,16.87 v1(0.32,15.07) 0.32,15.05 1.15,15.05 2.15,16.05 18,16.05 19.5,14.55 v2(19.5,14.5)
  Bottom w0.2: v1(0.29,36.01) 1.05,36.77 U20.3@1.05,37.075 ; v1(0.32,15.07) 1.05,15.8 U21.3@1.05,16.075
MIC_DATA: U11.A9 U20.4 U21.4 | length 53.1
  Top w0.2: v1(20.75,12.5) U11.A9@20.75,13.25
  F4 w0.2: v1(0.18,39.3) 0.18,37.33 -0.75,36.4 -0.75,20.5 0.27,19.48 v1(0.27,18.32) -0.4,18.32 -1.2,17.52 -1.2,14.15 -0.1,13.05 15.9,13.05 16.5,12.45 20.7,12.45 v1(20.75,12.5)
  Bottom w0.2: v1(0.18,39.3) 0.45,39.3 1.05,38.7 U20.4@1.05,38.425 ; v1(0.27,18.32) 0.3,18.29 0.496,18.29 1.05,17.736 U21.4@1.05,17.425
MIC_VDD: C30.1 C77.1 C88.2 R47.2 U11.A7 U20.1 U21.1 | length 60.2
  Top w0.2: C30.1@1.7,38.35 1.7,39.06 1.99,39.35 v1(3.09,39.35) 3.09,38.36 R47.2@3.1,38.35 ; C77.1@2.7,17.35 v1(2.7,18.27) ; U11.A7@20.75,14.25 21.4,14.25 v1(21.9,14.75) 22.15,15 C88.2@22.9,15
  F4 w0.5: v1(2.7,18.27) v1@2.72,18.25 ; v1(3.09,39.35) 3.09,37.6 4.03,36.66 4.03,19.68 2.72,18.37 v1@2.72,18.25 ; v1@21.94,14.71 22.35,14.71 23.75,16.11 23.75,19.74 23.09,20.4 18.53,20.4 15.94,17.81 3.16,17.81 v1@2.72,18.25
  Bottom w0.2: U21.1@1.95,17.425 1.95,17.75 2.47,18.27 v1(2.7,18.27) ; U20.1@1.95,38.425 1.95,38.7 2.6,39.35 v1(3.09,39.35)
NetB1_2: B1.2 B1.3 R18.2 R19.2 | length 12.4
  Top w0.3: B1.2@115.45,51 122.35,51 ; R19.2@122.35,47.75 R18.2@122.35,49 122.35,51 ; B1.3@124.55,51 122.35,51
NetB2_1: B2.1 B2.4 C25.2 R39.1 SB7.2 | length 17.8
  Top w0.3: B2.1@115.45,39.5 116.95,39.5 117.15,39.7 SB7.2@117.15,42 117.15,42.95 117.4,43.2 121.3,43.2 121.65,42.85 ; C25.2@121.65,42 121.65,42.85 ; B2.4@124.55,39.5 124.25,39.8 124.25,43.021 ; R39.1@125.071,43.021 124.25,43.021 ; 121.65,42.85 121.821,43.021 124.25,43.021
NetC6_1: C6.1 CN1.2 R6.2 | length 4.7
  Top w0.2: CN1.2@41,53.6 41,51.95 41.35,51.6 R6.2@41.35,50.75 42.85,50.75 C6.1@43,50.6
NetC6_2: C6.2 R7.1 | length 1.5
  Top w0.2: C6.2@43,49.4 R7.1@44.5,49.4
NetC9_1: C9.1 R8.1 R9.2 U1.4 | length 7
  Top w0.3: U1.4@48.2,50.1 R8.1@51,50.1 ; R9.2@48.6,48.25 50.9,48.25 C9.1@51,48.35 R8.1@51,50.1 ; R8.1@51,50.15 R8.1@51,50.1
NetC9_2: C9.2 R10.1 | length 1.5
  Top w0.3: C9.2@51,47.15 R10.1@52.5,47.15
NetC10_2: C10.2 R18.1 SB6.2 | length 2.8
  Top w0.3: C10.2@119.6,47.75 SB6.2@119.6,49 R18.1@121.15,49
NetC12_2: C12.2 R31.1 X3.2 | length 4.3
  Top w0.12: X3.2@38.45,48 38.45,47.55 39.1,46.9 C12.2@39.1,45.75 39.25,45.75 R31.1@39.25,44.1
NetC13_2: C13.2 R32.1 X3.1 | length 4.2
  Top w0.12: R32.1@40.5,44.1 40.5,45.75 C13.2@40.4,45.75 40.4,47.45 X3.1@40.95,48
NetC47_2: C47.2 U5.L11 | length 6.4
  Top w0.12: v1(33.2,32.45) U5.L11@33.6,32.85
  Top w0.2: C47.2@27.897,31 v1(29.05,31.45)
  F4 w0.12: v1(29.05,31.45) 29.65,32.05 32.8,32.05 v1(33.2,32.45)
NetC48_2: C48.2 U5.E11 | length 8.2
  Top w0.12: U5.E11@38.4,32.85 v1(38.8,32.45)
  Top w0.2: v1(43.55,30.05) 44.603,30.05 C48.2@44.603,30
  Bottom w0.12: v1(38.8,32.45) 39.2,32.05 42.95,32.05 43.55,31.45 v1(43.55,30.05)
NetC66_2: C66.2 C67.2 U9.6 | length 6.8
  Top w0.2: U9.6@48.472,21.789 49.489,21.789 49.7,22 v1(49.9,22) C66.2@50.9,22 ; v1(53,21.9) 53,22 C67.2@54,22
  Bottom w0.2: v1(49.9,22) 53,22 v1(53,21.9)
NetC69_2: C69.2 U11.F1 | length 2.4
  Top w0.12: U11.F1@18.25,17.25 18.25,19.63 C69.2@18.26,19.64
NetC73_1: C73.1 C74.2 C81.2 L2.1 U9.1 U9.19 | length 20.9
  Top w0.2: C81.2@42.65,16.6 42.65,17.95 v1(42.7,18) ; 45.2,18 45.322,18.122 U9.19@45.322,18.639 ; U9.1@48.472,19.289 v1(49.6,19.289) 49.839,19.289 50.05,19.5 C74.2@50.9,19.5
  Top w0.3: L2.1@39.35,21 39.545,20.805 40.445,20.805 40.75,20.5 40.75,19.5 ; C73.1@39.647,19.25 40.5,19.25 40.75,19.5 ; 45.2,18 42.75,18 v1(42.7,18) 42.25,18 40.75,19.5
  Bottom w0.2: v1(42.7,18) 44,18 44.7,18.7 49.011,18.7 v1(49.6,19.289)
NetC78_1: C78.1 U11.G7 | length 5.6
  Top w0.12: v2(17.5,14.5) U11.G7@17.75,14.25
  Top w0.2: C78.1@15.1,17 16,17 v1(16.35,16.65)
  Bottom w0.2: v1(16.35,16.65) 15.95,16.25 15.95,14.75 16.35,14.35 17.35,14.35 v2(17.5,14.5)
NetC80_1: C80.1 U11.H7 | length 2.6
  Top w0.2: C80.1@15.1,15.25 15.65,15.25 16.65,14.25 U11.H7@17.25,14.25
NetC84_2: C84.2 C91.2 SB10.2 U12.1 U12.3 | length 8.2
  Top w0.3: SB10.2@88.1,18 SB10.2@88.15,18
  Top w0.5: C91.2@88.1,14.5 C91.2@88.1,14.55 ; SB10.2@88.1,18 C84.2@88.1,16.5 C84.2@88.1,16.45 ; U12.3@90.425,14.55 C91.2@88.1,14.55 ; U12.1@90.425,16.45 C84.2@88.1,16.45 ; C91.2@88.1,14.55 C84.2@88.1,16.45
NetC87_1: C87.1 U11.H8 | length 4.6
  Top w0.12: C87.1@13.4,13.75 14.25,12.9 16.15,12.9 17,13.75 U11.H8@17.25,13.75
NetC87_2: C87.2 U11.G8 | length 2.9
  Top w0.12: v2(17.5,14) U11.G8@17.75,13.75
  Top w0.2: C87.2@15.1,13.75 v1(16.05,13.75)
  F6 w0.2: v1(16.05,13.75) 16.3,14 v2(17.5,14)
NetC89_1: C89.1 U11.E6 | length 9.6
  Top w0.12: v2(18.5,14.5) U11.E6@18.75,14.75
  Top w0.2: v1(25.65,15.1) 25.75,15 C89.1@26.65,15
  F6 w0.2: v2(18.5,14.5) 19,15 20.15,15 21.1,14.05 21.85,14.05 22.9,15.1 v1(25.65,15.1)
NetC94_2: C94.2 U12.4 | length 2.1
  Top w0.3: U12.4@92.575,14.55 92.6,14.55 C94.2@92.6,12.5
NetC102_1: C102.1 CN10.6 U11.H6 | length 18
  Top w0.12: v1(16.75,14.75) U11.H6@17.25,14.75
  Top w0.2: CN10.6@14.25,0.45 14.25,5.3 15.65,6.7 v1(15.65,10.75) 15.55,10.85 C102.1@14.75,10.85
  F3 w0.2: v1(15.65,10.75) 15.13,11.27 15.13,14.56 15.32,14.75 v1(16.75,14.75)
NetC102_2: C102.2 R102.1 | length 1.3
  Top w0.12: R102.1@13.5,9.65 C102.2@14.75,9.65
NetC104_1: C104.1 U11.D9 | length 2.7
  Top w0.2: C104.1@18,11.1 18,11.8 19.25,13.05 U11.D9@19.25,13.25
NetC105_2: C105.2 U11.C9 | length 2.2
  Top w0.12: C105.2@19.75,11.1 19.8,11.1 C105.2@19.75,11.15
  Top w0.2: C105.2@19.75,11.15 U11.C9@19.75,13.25
NetC106_1: C106.1 U11.B7 | length 3.7
  Top w0.12: U11.B7@20.25,14.25 v2(20.5,14)
  Top w0.2: C106.1@21.5,11.1 v1(21.5,12.05)
  F3 w0.2: v2(20.5,14) 21.5,13 v1(21.5,12.05)
NetC106_2: C106.2 CN11.4 | length 17.6
  Top w0.12: CN11.4@18.55,-6.95 CN11.4@18.55,-6.46
  Top w0.2: CN11.4@18.55,-6.46 18.55,5.19 21.5,8.14 C106.2@21.5,9.4
NetC107_1: C107.1 U11.D7 | length 7.4
  Top w0.12: v2(19,14) U11.D7@19.25,14.25 ; C107.1@23.25,11.1 v1(23.25,12.05)
  F3 w0.2: v2(19,14) 19.2,14 20.09,13.11 20.09,12.13 20.76,11.46 22.66,11.46 v1(23.25,12.05)
NetC107_2: C107.2 CN11.6 | length 9.9
  Top w0.2: C107.2@23.25,9.4 23.25,8.23 25.45,6.03 CN11.6@25.45,0.45
NetC114_1: C114.1 L6.1 R123.2 R124.1 U17.1 | length 23
  Top w0.12: C114.1@60.35,-0.3 60.364,-0.314 61.01,-0.314 61.596,-0.9 62.9,-0.9 63.115,-1.115 63.115,-1.14 63.441,-1.466 64.32,-2.345 65.4,-2.345 65.405,-2.35 v1(65.95,-2.35) ; L6.1@72.35,-6.25 73.8,-6.25 74.2,-5.85 74.2,-3.45 v1@74,-3.25 ; v1(74,-3.35) v1@74,-3.25 ; R124.1@75.5,-1.15 74.9,-1.75 R123.2@74.016,-1.75 74,-1.75 v1@74,-3.25
  F3 w0.12: v1(65.95,-2.35) 73,-2.35 v1(74,-3.35)
NetC115_1: C115.1 CN10.4 U11.G6 | length 30.8
  Top w0.12: C115.1@5.5,-2.35 C115.1@5.57,-2.28 ; v1(6.65,-2.25) v1@6.7,-2.3 ; v2(17.5,15) U11.G6@17.75,14.75
  Top w0.2: C115.1@5.57,-2.28 5.59,-2.3 6.7,-2.3 7.35,-2.95 CN10.4@7.35,-6.95
  F3 w0.2: v1(6.65,-2.25) 6.65,7.94 13.96,15.25 17.25,15.25 v2(17.5,15)
NetC115_2: C115.2 R121.1 | length 1.3
  Top w0.12: R121.1@4.25,-1.15 C115.2@5.5,-1.15
NetC116_2: C116.2 C119.2 U15.20 | length 8.9
  Top w0.2: U15.20@68.75,0.45 68.75,-0.05 ; v1(68.95,-0.31) 68.94,-0.31 68.75,-0.12 68.75,-0.05 ; C116.2@69,-1.05 69,-0.3 68.75,-0.05 ; C119.2@70.434,-4.275 v1(71.375,-4.275)
  Top w0.3: C116.2@69,-1.15 68.9,-1.15 C116.2@69,-1.05
  F4 w0.2: v1(68.95,-0.31) 68.95,-1.05 69.75,-1.85 69.75,-4.06 69.98,-4.29 71.36,-4.29 v1(71.375,-4.275)
NetC120_2: C120.2 C121.2 C122.2 C123.2 CN12.5 CN12.6 L7.2 | length 27.5
  Top w0.2: C122.2@61.75,-10.35 61.75,-11.1 63.582,-11.1 63.582,-9.268 63.75,-9.1 C120.2@63.75,-7.85 63.85,-7.95 65.49,-7.95 CN12.6@65.532,-7.993 65.532,-9.232 65.85,-9.55 66.457,-9.55 ; CN12.5@66.457,-8.318 66.457,-9.55 ; CN12.6@67.757,-11.517 67.757,-9.55 ; C121.2@71.65,-7.75 C121.2@71.6,-7.75 ; L7.2@73.9,-9.25 71.932,-9.25 ; C123.2@74.15,-11 74.132,-11.018 CN12.6@71.932,-10.993 71.932,-9.25 ; 66.457,-9.55 67.757,-9.55 ; 67.757,-9.55 69.65,-9.55 69.982,-9.218 CN12.6@69.982,-7.993 70.225,-7.75 C121.2@71.6,-7.75 ; C121.2@71.6,-7.75 71.6,-8.5 71.932,-8.832 71.932,-9.25
NetCN2_8: CN2.8 SB2.1 | length 6.3
  Top w0.5: CN2.8@16.5,54.69 16.5,52.65 17.15,52 SB2.1@20.5,52
NetCN3_10: CN3.10 R11.2 | length 16.3
  Top w0.2: R11.2@81.25,48.35 79.5,48.35 79.01,48.84 79.01,57.33 81.75,60.07 CN3.10@81.75,61.575
NetCN5_5: CN5.5 SB4.2 SB5.2 | length 9.9
  Top w0.3: SB5.2@104.35,50.25 105.3,50.25 105.6,50.55 105.6,51.75 ; SB4.2@104.35,51.75 105.6,51.75 ; CN5.5@111.5,52.06 105.86,52.06 105.6,51.8 105.6,51.75
NetCN5_6: CN5.6 SB1.2 SB3.2 | length 6.8
  Top w0.3: SB3.2@104.35,53.25 105.5,53.25 105.7,53.45 105.7,54.5 105.8,54.6 ; SB1.2@104.35,54.75 105.55,54.75 105.7,54.6 105.8,54.6 ; CN5.6@108.5,54.6 105.8,54.6
NetCN7_8: CN7.8 R96.1 | length 2.7
  Top w0.2: CN7.8@63.24,14.976 63.24,15 R96.1@65.9,15
NetCN9_1: CN9.1 R95.2 U9.2 | length 14.8
  Top w0.12: U9.2@48.472,19.789 49.139,19.789 49.4,20.05 50,20.05 50.05,20.1 53.1,20.1 53.8,19.4 53.8,15.9 53.3,15.4 R95.2@52.75,15.4 52.75,11.114 CN9.1@52.764,11.099
NetCN9_2: CN9.2 R94.2 | length 4.3
  Top w0.2: CN9.2@50.936,11.099 50.936,14.036 51,14.1 R94.2@51,15.4
NetCN9_11: CN9.11 R89.2 | length 4.4
  Top w0.2: R89.2@41.25,15.4 41.25,14.699 41.436,14.513 CN9.11@41.436,11.099
NetCN9_12: CN9.12 R88.2 U9.3 | length 18
  Top w0.12: R88.2@39.5,15.4 39.5,14.507 v1@39.6,14.407 ; v1(39.6,14.4) v1@39.6,14.407 ; CN9.12@39.607,11.099 v1@39.607,14.4 ; v1@39.6,14.407 39.6,14.45 39.607,14.45 v1@39.607,14.4 ; v1@39.6,14.407 v1@39.607,14.4
  Top w0.2: U9.3@48.472,20.289 49.1,20.289 v1(49.1,20.3)
  F6 w0.12: v1(39.6,14.4) 39.6,14.45 41.45,14.45 41.5,14.5 41.5,15.85 42.3,16.65 43.8,16.65 44.65,17.5 46.5,17.5 48.9,19.9 48.9,20.2 49,20.3 v1(49.1,20.3)
NetCN12_4: CN12.4 U15.23 U22.4 | length 14.6
  Top w0.12: U22.4@66.125,-4 U22.4@66.365,-4.24 ; U22.4@66.132,-3.993 v3(66.965,-3.993) ; CN12.4@67.107,-8.318 67.107,-7.843 67.125,-7.825 v1(67.125,-7.284) ; U15.23@70.25,0.45 70.25,0 70.45,-0.2 v1(71.6,-0.2)
  Bottom w0.12: v1(67.125,-7.284) 67.119,-7.284 65.775,-5.94 65.775,-5.183 v3(66.965,-3.993) 70.758,-0.2 v1(71.6,-0.2)
NetCN13_4: CN13.4 R133.2 U23.1 | length 11.2
  Top w0.12: R133.2@82.2,-4.75 v1@82.2,-5.62 ; v1(82.21,-5.64) 82.2,-5.64 v1@82.2,-5.62 ; U23.1@83.675,-0.95 v1(84.35,-0.95) ; CN13.4@84.6,-8.25 84.6,-7.55 84.14,-7.09 83.67,-7.09 v1@82.2,-5.62
  F3 w0.12: v1(82.21,-5.64) 82.21,-3.04 84.325,-0.925 84.35,-0.9 v1(84.35,-0.95)
NetD1_2: D1.2 D2.2 D3.2 D4.2 SB10.1 | length 27.8
  Top w0.12: D3.2@101.5,21.25 D3.2@101.607,21.25
  Top w0.3: D2.2@99.893,21.25 100.75,21.25 D3.2@101.5,21.25 ; v1(100.75,18.75) D4.2@101.607,18.75 ; 101,31.5 D1.2@101.607,31.5
  Top w0.5: SB10.1@89.25,18 100,18 v1(100.75,18.75) 100.75,21.25 100.75,31.25 101,31.5
NetD5_1: D5.1 L3.2 U10.8 | length 8.3
  Top w0.3: D5.1@70,15.74 70.02,15.76 D5.1@70.029,15.75 ; 75.075,18.43 U10.8@75.075,19.025
  Top w0.5: D5.1@70.029,15.75 L3.2@74.976,15.75 74.976,18.331 75.075,18.43
NetD6_2: D6.2 R108.2 | length 2.3
  Top w0.3: R108.2@113.35,5 D6.2@115.607,5
NetJP3_1: JP3.1 U11.C3 | length 29.8
  Top w0.12: U11.C3@19.75,16.25 19.975,16.025 20,16.025 v2(20,16)
  F3 w0.2: v2(20,16) 20,15.65 21.35,14.3 23,14.3 30.1,7.2 JP3.1@30.1,-8.25
NetJP3_2: JP3.2 U11.B3 | length 33.2
  Top w0.12: U11.B3@20.25,16.25 v2(20.5,16)
  F3 w0.2: v2(20.5,16) 21,15.5 22.35,15.5 31.6,6.25 31.6,-9.29 JP3.2@30.1,-10.79
NetJP4_1: JP4.1 U11.B1 | length 33.3
  Top w0.15: U11.B1@20.25,17.25 20.25,17.55 v1(20.5,17.8)
  F3 w0.2: v1(20.5,17.8) 20.5,16.75 20.75,16.5 22.9,16.5 33.3,6.1 JP4.1@33.3,-8.25
NetJP4_2: JP4.2 U11.A2 | length 35.5
  Top w0.12: U11.A2@20.75,16.75 21.65,16.75 v1(21.85,16.95)
  F3 w0.2: v1(21.85,16.95) 23,16.95 34.75,5.2 34.75,-9.34 JP4.2@33.3,-10.79
NetLD1_1: LD1.1 R59.1 | length 2
  Top w0.3: R59.1@118.1,31.75 LD1.1@120.15,31.75
NetLD2_1: LD2.1 R86.2 | length 2.3
  Top w0.3: R86.2@118.1,17.75 LD2.1@120.4,17.75
NetLD3_1: LD3.1 R140.1 | length 2
  Top w0.12: R140.1@58,-10.6 LD3.1@60,-10.6
NetLD3_2: LD3.2 R122.2 R130.1 U17.3 | length 9.4
  Top w0.12: LD3.2@60,-8.9 60,-6.15 60.4,-5.75 R130.1@60.4,-3.25 ; R122.2@60.35,-2 R130.1@60.35,-3.25 R130.1@60.4,-3.25 ; U17.3@62.45,-2.8 62,-3.25 R130.1@60.4,-3.25
NetLD4_1: LD4.1 R141.1 | length 1.7
  Top w0.3: LD4.1@77.5,-10.6 R141.1@79.25,-10.6
NetLD4_2: LD4.2 T1.3 | length 5.7
  Top w0.3: LD4.2@77.5,-8.9 77.5,-6.85 78.9,-5.45 T1.3@78.9,-3.75
NetLD5_1: LD5.1 R136.1 | length 6.1
  Top w0.3: R136.1@92.35,-5.75 92.35,-6.75 91.5,-7.6 91.5,-10.5 91.6,-10.6 LD5.1@92.5,-10.6
NetLD5_2: LD5.2 T2.3 | length 8.5
  Top w0.3: LD5.2@92.5,-8.9 92.5,-7.7 93.45,-6.75 93.45,-5.1 94.75,-3.8 T2.3@94.75,-1.35
NetLD6_1: LD6.1 R137.1 | length 6.1
  Top w0.3: LD6.1@94.75,-10.6 95.7,-10.6 95.7,-7.7 94.9,-6.9 R137.1@94.9,-5.75
NetLD6_2: LD6.2 R119.1 R126.1 U16.3 | length 12
  Top w0.3: U16.3@88.45,-1.825 88.45,-2.25 R126.1@90.15,-2.25 ; v1(90.15,-3.25) R126.1@90.15,-2.25 ; R119.1@90.15,-1 R126.1@90.15,-2.25 ; v1(94.7,-7.85) 94.75,-7.85 LD6.2@94.75,-8.9
  F3 w0.5: v1(90.15,-3.25) 94.7,-7.8 v1(94.7,-7.85)
NetLD7_2: LD7.2 R138.2 | length 1.6
  Top w0.3: LD7.2@115.25,-8.25 R138.2@115.25,-6.6
NetLD7_3: LD7.3 R139.1 | length 1.6
  Top w0.3: LD7.3@116.75,-8.25 R139.1@116.75,-6.6
NetP1_27: P1.27 R2.2 | length 2.8
  Top w0.12: P1.27@56.25,62.175 56.25,61.4 57.1,60.55 R2.2@57.1,59.7
NetP1_28: P1.28 R1.2 | length 2.6
  Top w0.12: P1.28@55.75,62.175 55.75,60.9 56,60.65 R1.2@56,59.7
NetR4_2: R4.2 X1.1 | length 1.4
  Top w0.12: R4.2@55.775,53.75 R4.2@55.8,53.75
  Top w0.2: R4.2@55.775,53.75 X1.1@55.775,55.175
NetR5_2: R5.2 X2.1 | length 2.5
  Top w0.12: R5.2@33.9,50.25 33.9,49.6 34.675,48.825 X2.1@34.675,48.075
NetR7_2: R7.2 R9.1 U1.2 | length 5.2
  Top w0.2: R7.2@44.5,50.6 44.5,50.75 U1.2@46.3,50.75 46.85,50.75 47.4,50.2 R9.1@47.4,48.25
NetR10_2: R10.2 R22.1 U2.2 | length 5
  Top w0.3: R10.2@52.5,48.35 53.25,48.35 ; U2.2@54.05,48.5 53.25,48.5 53.25,48.35 ; R22.1@54.65,46 54,46 53.25,46.75 53.25,48.35
NetR20_2: R20.2 U5.L5 | length 9.2
  Top w0.12: R20.2@32.35,46 32.35,45.05 v1(32.6,45.05) ; v1(33.2,38.05) U5.L5@33.6,37.65
  F5 w0.12: v1(32.6,45.05) 32.35,44.8 32.35,41.85 32.8,41.4 32.8,38.45 v1(33.2,38.05)
NetR23_1: R23.1 U4.A1 | length 2.5
  Top w0.12: R23.1@11.4,43.15 11.4,42.459 11.5,42.559 U4.A1@11.5,40.85
NetR24_1: R24.1 U4.A2 | length 2.3
  Top w0.12: U4.A2@12.3,40.85 12.3,42.35 12.4,42.45 R24.1@12.4,43.15
NetR25_1: R25.1 U4.C7 | length 4.9
  Top w0.12: R25.1@14.95,43.15 14.944,39.906 15.6,39.25 U4.C7@16.3,39.25
NetR26_1: R26.1 U4.A8 | length 2.6
  Top w0.12: U4.A8@17.1,40.85 17.1,41.45 17.944,42.294 R26.1@17.95,43.15
NetR27_1: R27.1 U4.A9 | length 2.7
  Top w0.12: U4.A9@17.9,40.85 17.9,41.312 18.944,42.356 R27.1@18.95,43.15
NetR29_2: R29.2 TP1.1 | length 4.9
  Top w0.12: TP1.1@32,48.25 33.35,46.9 33.35,44.45 R29.2@33,44.1
NetR33_2: R33.2 TP2.1 | length 3.9
  Top w0.12: R33.2@43,44.1 TP2.1@43,48
NetR35_2: R35.2 R38.2 U5.E5 | length 11.6
  Top w0.12: U5.E5@38.4,37.65 v1(38.8,38.05) ; v1(43.8,41.75) R38.2@44.65,41.75 R35.2@44.65,42.75
  Bottom w0.12: v1(38.8,38.05) 38.4,38.45 38.4,41.4 38.75,41.75 41.3,41.75 41.4,41.65 43.7,41.65 v1(43.8,41.75)
NetR36_1: R36.1 U4.C3 | length 5.2
  Top w0.12: R36.1@9.3,41.45 v1(10.1,41.45) ; v1(12.7,39.65) U4.C3@13.1,39.25
  Bottom w0.12: v1(10.1,41.45) 11.8,41.45 12.7,40.55 v1(12.7,39.65)
NetR37_1: R37.1 U4.B9 | length 3.5
  Top w0.12: U4.B9@17.9,40.05 18.393,40.543 18.393,40.943 19.5,42.05 R37.1@20.3,42.05
NetR40_1: R40.1 U4.C2 | length 6.6
  Top w0.12: R40.1@6.4,39.55 6.9,39.55 v1(7.25,39.9) ; v1(11.9,38.85) U4.C2@12.3,39.25
  Bottom w0.12: v1(7.25,39.9) 10.85,39.9 v1(11.9,38.85)
NetR41_1: R41.1 U4.C8 | length 3.9
  Top w0.12: U4.C8@17.1,39.25 17.5,39.65 18.093,39.65 19.496,41.053 19.6,41.053 R41.1@20.3,41.05
NetR43_1: R43.1 U4.B1 | length 2.4
  Top w0.12: R43.1@9.3,39.45 10,39.45 10.6,40.05 U4.B1@11.5,40.05
NetR44_2: R44.2 U5.M5 | length 5.6
  Top w0.12: R44.2@27.85,38.75 28.511,38.75 28.636,38.875 28.661,38.85 v1(28.8,38.85) ; v1(32.4,38.05) U5.M5@32.8,37.65
  Bottom w0.12: v1(28.8,38.85) 28.8,38.75 28.825,38.775 29.15,38.45 32,38.45 v1(32.4,38.05)
NetR47_1: R47.1 U20.2 | length 3.4
  Top w0.2: v1(3.1,35.65) R47.1@3.1,37.15
  Bottom w0.2: U20.2@1.95,37.075 1.95,36.8 v1(3.1,35.65)
NetR48_1: R48.1 U4.D3 | length 7.2
  Top w0.12: R48.1@6.4,37.95 v1(7.1,37.95) ; v1(12.7,38.85) U4.D3@13.1,38.45
  Bottom w0.12: v1(7.1,37.95) 11.8,37.95 v1(12.7,38.85)
NetR49_1: R49.1 U4.D2 | length 3.3
  Top w0.12: R49.1@9.3,38.45 10.3,38.45 10.7,38.05 11.9,38.05 U4.D2@12.3,38.45
NetR50_1: R50.1 U4.D8 | length 3.4
  Top w0.12: U4.D8@17.1,38.45 17.5,38.05 19.646,38.05 19.641,38.056 R50.1@20.3,38.05
NetR51_1: R51.1 U4.D7 | length 7.3
  Top w0.12: U4.D7@16.3,38.45 v1(16.7,38.05) ; v1(22.5,37.75) R51.1@23.3,37.75
  Bottom w0.12: v1(16.7,38.05) 18.95,38.05 19.25,37.75 v1(22.5,37.75)
NetR52_1: R52.1 U4.E2 | length 3.5
  Top w0.12: R52.1@9.3,36.45 9.9,36.45 10.7,37.25 11.9,37.25 U4.E2@12.3,37.65
NetR53_1: R53.1 U4.E8 | length 3.4
  Top w0.12: U4.E8@17.1,37.65 17.5,37.25 19.253,37.25 19.45,37.053 R53.1@20.3,37.05
NetR55_2: R55.2 U4.F2 | length 3.6
  Top w0.12: R55.2@9.3,35.45 10.3,35.45 11.3,36.45 11.9,36.45 U4.F2@12.3,36.85
NetR56_2: R56.2 U4.F8 | length 4.3
  Top w0.12: U4.F8@17.1,36.85 17.5,36.45 18.75,36.45 18.9,36.3 18.9,35.9 20.05,34.75 R56.2@20.3,34.75
NetR59_2: R59.2 SB8.1 | length 57.1
  Top w0.3: SB8.1@67.25,20 67.7,20 v1(67.7,21.15) ; v1(115.9,31.75) R59.2@116.9,31.75
  F4 w0.3: v1(67.7,21.15) 68.43,21.15 68.93,20.65 72,20.65 72.63,20.02 79.86,20.02 82.09,22.25 83.85,22.25 84.85,21.25 86.95,21.25 87.85,22.15 93.85,22.15 96.55,24.85 106.95,24.85 113.35,31.75 v1(115.9,31.75)
NetR66_1: R66.1 R67.1 U9.11 | length 5.8
  Top w0.12: R66.1@42.659,24.45 43.625,24.45 43.775,24.3 43.775,23.778 44.028,23.525 45.436,23.525 ; R67.1@45.436,24.586 45.436,23.525 ; U9.11@45.822,22.439 45.822,23.1 45.436,23.486 45.436,23.525
NetR69_1: R69.1 R70.1 U9.8 | length 3.9
  Top w0.12: U9.8@47.322,22.439 47.322,22.772 47.6,23.05 48.15,23.05 48.436,23.336 R69.1@48.436,24.586 R70.1@49.436,24.586
NetR71_1: R71.1 R73.1 U9.7 | length 4.7
  Top w0.12: U9.7@47.822,22.439 49.378,22.439 50.189,23.25 R73.1@50.9,23.25 R71.1@50.9,24.5
NetR72_1: R72.1 U8.8 | length 3.4
  Top w0.3: U8.8@94.405,22.269 95.369,22.269 96,22.9 R72.1@96,24.4
NetR76_2: R76.2 U11.H1 | length 5.5
  Top w0.12: R76.2@14.5,21.05 15.4,21.05 16.6,19.85 16.6,17.9 U11.H1@17.25,17.25
NetR78_2: R78.2 U9.5 | length 2.7
  Top w0.12: U9.5@48.472,21.289 49.511,21.289 50.05,20.75 R78.2@50.9,20.75
NetR79_1: R79.1 U8.5 | length 2.2
  Top w0.3: R79.1@90.1,20.25 90.1,20.85 90.595,21.345 U8.5@90.595,22.269
NetR80_1: R80.1 U11.G2 | length 8.4
  Top w0.15: v2(17.5,17) U11.G2@17.75,16.75
  Top w0.2: v1(12.35,19.85) R80.1@13.3,19.85
  Bottom w0.15: v1(12.35,19.85) 13.1,19.1 16.7,19.1 17.15,18.65 17.15,17.35 v2(17.5,17)
NetR81_1: R81.1 R85.1 U10.7 | length 2.8
  Top w0.3: R85.1@73.6,18.5 R81.1@73.6,19.75 73.6,19.675 U10.7@75.075,19.675
NetR82_1: R82.1 U10.2 | length 1.7
  Top w0.3: U10.2@77.925,19.675 78.575,19.675 78.85,19.4 R82.1@79.5,19.4
NetR83_2: R83.2 U11.F3 | length 6.3
  Top w0.12: U11.F3@18.25,16.25 v2(18.5,16.5)
  Top w0.15: R83.2@14.5,18.6 v1(15.4,18.6)
  Bottom w0.15: v1(15.4,18.6) 16.2,18.6 16.75,18.05 16.75,16.9 17.6,16.05 18.05,16.05 v2(18.5,16.5)
NetR84_1: R84.1 U9.24 | length 3.2
  Top w0.12: U9.24@47.822,18.639 47.822,18.25 R84.1@50.65,18.25
NetR87_1: R87.1 U11.D4 U11.D5 | length 4.6
  Top w0.12: U11.D5@19.25,15.25 19.475,15.475 19.45,15.5 v2(19.5,15.5) U11.D4@19.25,15.75 ; v1(21.75,16.05) 22.2,16.5 R87.1@22.9,16.5
  F6 w0.12: v2(19.5,15.5) 21.2,15.5 v1(21.75,16.05)
NetR100_2: R100.2 U14.3 | length 3.1
  Top w0.12: U14.3@107,8.9 107,9.75 107.65,10.4 107.65,10.424 108.25,10.424 R100.2@108.25,11.15
NetR101_2: R101.2 U14.2 | length 3.9
  Top w0.12: U14.2@107.5,8.9 107.5,9.9 107.7,10.1 109.176,10.1 109.5,10.424 R101.2@109.5,11.15
NetR105_2: R105.2 U14.44 | length 3.5
  Top w0.25: U14.44@109.65,5.25 111.05,5.25 111.2,5.4 111.2,6.15 111.55,6.5 R105.2@112.15,6.5
NetR107_1: R107.1 U15.32 | length 2.1
  Top w0.12: U15.32@71.3,4.5 72,4.5 72.5,5 R107.1@73.15,5
NetR114_2: R114.2 U15.26 | length 1.6
  Top w0.3: U15.26@71.3,1.5 R114.2@72.9,1.5
NetR115_1: R115.1 U15.24 | length 2.3
  Top w0.3: U15.24@70.75,0.45 72.9,0.45 R115.1@72.9,0.25
NetR116_1: R116.1 R117.2 U16.4 | length 3
  Top w0.3: U16.4@88.45,0.325 88.45,0.25 R117.2@90.15,0.25 R116.1@90.15,1.5
NetR118_1: R118.1 R120.1 R129.2 T3.1 | length 4.9
  Top w0.25: R129.2@113.35,-1.75 R129.2@113.35,-1.8 ; R118.1@113.35,1.25 R120.1@113.35,-0.25 R129.2@113.35,-1.8 ; T3.1@115.1,-1.8 R129.2@113.35,-1.8
NetR123_1: R123.1 U15.22 | length 3.6
  Top w0.12: U15.22@69.75,0.45 69.75,0.1 70.3,-0.45 71.05,-0.45 71.984,-1.384 R123.1@71.984,-1.75
NetR124_2: R124.2 R131.1 T1.1 | length 3.3
  Top w0.12: R131.1@75.5,-3.9 R124.2@75.5,-2.35 75.9,-2.35 76.35,-2.8 T1.1@77.1,-2.8
NetR128_2: R128.2 T3.2 | length 9.3
  Top w0.25: R128.2@107.25,-3.1 107.25,-3.95 107.5,-4.2 109.15,-4.2 110.05,-3.3 113.75,-3.3 114.15,-3.7 T3.2@115.1,-3.7
NetR134_1: R134.1 R135.1 T2.1 | length 6.1
  Top w0.3: R134.1@88.25,-4.4 R135.1@89.25,-4.4 91.25,-4.4 92.5,-3.15 T2.1@93.8,-3.15
NetU15_17: U15.17 U17.4 | length 5.6
  Top w0.12: U17.4@64.6,-2.8 66.8,-2.8 67.25,-2.35 U15.17@67.25,0.45
OSC_24M: R3.1 R114.1 X1.3 | length 70.5
  Top w0.2: v1(58.45,56.4) 58.45,56.425 X1.3@57.425,56.425 57.425,57.225 57.65,57.45 58.4,57.45 58.65,57.7 R3.1@58.65,58.5
  Top w0.3: R114.1@74.1,1.5 v1(75,1.5)
  F6 w0.2: v1(58.45,56.4) 58.95,56.4 62.7,52.65 62.7,38.15 61.5,36.95 61.5,22.44 66.09,17.85 70.35,17.85 75,13.2 v1(75,1.5)
OSC_25M: R30.1 R78.1 X2.3 | length 43.2
  Top w0.12: v1(36.95,46.4) 36.95,46.425 X2.3@35.925,46.425 35.925,45.925 36.5,45.35 37.05,45.35 38,44.4 R30.1@38,44.1 ; R78.1@52.1,20.75 v1(52.9,20.75)
  F6 w0.12: v1(36.95,46.4) 42.1,46.4 46.04,42.46 46.04,35.11 46.99,34.16 46.99,33.08 47.95,32.12 47.95,29.19 48.66,28.48 49.67,28.48 51.23,26.92 51.23,24.39 51.29,24.33 51.61,24.33 51.67,24.27 51.67,24.15 51.61,24.09 50.69,24.09 50.63,24.03 50.63,23.91 50.69,23.85 51.17,23.85 51.23,23.79 51.23,22.22 52.7,20.75 v1(52.9,20.75)
OSC_IN: C100.2 U14.5 X4.2 | length 8.2
  Top w0.12: X4.2@106.85,15.5 106.85,13.9 106.4,13.45 106.4,11.15 C100.2@107,11.15
  Top w0.2: U14.5@106,8.9 106,9.9 106.4,10.3 107,10.3 C100.2@107,11.15
OSC_OUT: C99.2 U14.6 X4.1 | length 7.5
  Top w0.12: X4.1@104.65,15.5 104.65,13.75 105.1,13.3 105.1,11.15 C99.2@105.75,11.15
  Top w0.2: U14.6@105.5,8.9 105.5,10.1 105.75,10.35 C99.2@105.75,11.15
OTG_FS_VBUS: C112.2 CN13.1 R58.2 R63.1 R134.2 SB18.2 U16.1 U24.1 | length 87.9
  Top w0.12: R63.1@38.75,25.9 38.8,25.9 v1(38.8,25.05) ; R58.2@45.85,32.25 v1(46.8,32.25) ; v1(80,6.5) 83.75,2.75 83.75,0.65 84,0.4 C112.2@85,0.4 85,-0.55 85.5,-1.05 85.5,-1.8 ; U24.1@82.575,-0.8 82.575,-1.275 83.3,-2 85.3,-2 85.5,-1.8 ; CN13.1@86.55,-8.25 86.5,-8.2 86.5,-6.7 ; SB18.2@87,-5.6 86.25,-5.6 ; R134.2@88.25,-5.6 88.25,-6.31 87.86,-6.7 86.5,-6.7 ; 85.5,-1.8 85.525,-1.825 U16.1@86.55,-1.825 86.55,-2.918 85.7,-3.768 85.7,-4.759 86.25,-5.309 86.25,-5.6 ; 86.25,-5.6 86.25,-6.45 86.5,-6.7
  F5 w0.12: v1(38.8,25.05) 39.95,23.9 40.7,23.9 41.97,22.63 48.46,22.63 v1@49.28,23.45 ; v1(49.25,23.45) v1@49.28,23.45 ; v1(80,6.5) 80.05,6.55 67.5,19.1 57.73,19.1 55.41,21.42 51.31,21.42 v1@49.28,23.45
  F6 w0.12: v1(46.8,32.25) 47,32.05 47,29.19 48.92,27.27 48.92,23.78 v1(49.25,23.45)
PA1: R77.1 U5.N2 U9.14 | length 43.4
  Top w0.12: v1(31.6,40.45) U5.N2@32,40.05 ; R77.1@42.6,21.5 43.4,21.5 v1(43.5,21.4) 43.57,21.47 43.75,21.289 U9.14@44.672,21.289
  F5 w0.12: v1(31.6,40.45) 31.2,40.05 31.2,38.55 31.1,38.45 29.75,38.45 29.55,38.25 29.55,35.35 30.35,34.55 30.35,32.95 30.45,32.85 32.6,32.85 32.8,32.65 32.8,31.5 32.55,31.25 32.1,31.25 32,31.15 32,24.5 33.7,22.8 33.705,22.795 34.722,22.795 34.727,22.8 35.2,22.8 35.67,22.33 35.67,21.8 35.73,21.74 35.85,21.74 35.91,21.8 35.91,22.74 35.97,22.8 36.09,22.8 36.15,22.74 36.15,21.8 36.21,21.74 36.33,21.74 36.39,21.8 36.39,22.74 36.45,22.8 36.57,22.8 36.63,22.74 36.63,21.8 36.69,21.74 36.81,21.74 36.87,21.8 36.87,22.74 36.93,22.8 37.05,22.8 37.11,22.74 37.11,21.64 38.15,20.6 41.95,20.6 42.75,21.4 v1(43.5,21.4)
PA2: R65.1 U5.P2 U9.12 | length 42.9
  Top w0.12: v1(30.8,40.45) U5.P2@31.2,40.05 ; R65.1@42.64,23.23 42.86,23.45 v1(43.5,23.45) 43.75,23.2 45.222,23.2 45.322,23.1 U9.12@45.322,22.439
  F3 w0.12: v1(26.75,23.1) 27.225,23.575 35.525,23.575 36.4,22.7 43.3,22.7 43.5,22.9 v1(43.5,23.45)
  F4 w0.12: v1(26.75,23.1) 26.25,23.6 26.25,38.2 28.1,40.05 30.4,40.05 v1(30.8,40.45)
PA3: U5.R2 U15.3 | length 89
  Top w0.12: v1(30,40.45) U5.R2@30.4,40.05 ; U15.3@69.75,5.05 v1(69.75,5.9)
  F4 w0.12: v1(30,40.45) 27.41,40.45 25,38.04 25,22.9 26.45,21.45 26.45,11.25 32.25,5.45 59.16,5.45 59.22,5.51 59.22,5.79 59.28,5.85 59.4,5.85 59.46,5.79 59.46,5.08 59.52,5.02 59.64,5.02 59.7,5.08 59.7,5.79 59.76,5.85 59.88,5.85 59.94,5.79 59.94,5.08 60,5.02 60.12,5.02 60.18,5.08 60.18,5.79 60.24,5.85 60.36,5.85 60.42,5.79 60.42,5.08 60.48,5.02 60.6,5.02 60.66,5.08 60.66,5.79 60.72,5.85 60.84,5.85 60.9,5.79 60.9,5.08 60.96,5.02 61.08,5.02 61.14,5.08 61.14,5.79 61.2,5.85 61.32,5.85 61.38,5.79 61.38,5.08 61.44,5.02 61.56,5.02 61.62,5.08 61.62,5.79 61.68,5.85 61.8,5.85 61.86,5.79 61.86,5.51 61.92,5.45 69.35,5.45 69.8,5.9 v1(69.75,5.9)
PA4: P1.17 U5.N4 | length 74.9
  Top w0.12: v1(31.6,38.85) U5.N4@32,38.45 ; v1(61.23,63.49) 61.25,63.47 P1.17@61.25,62.175
  F5 w0.12: v1(31.6,38.85) 32,39.25 32,46.12 33.19,47.31 38.79,47.31 38.95,47.15 38.95,46.65 39.01,46.59 39.13,46.59 39.19,46.65 39.19,47.97 39.25,48.03 39.37,48.03 39.43,47.97 39.43,46.65 39.49,46.59 39.61,46.59 39.67,46.65 39.67,47.97 39.73,48.03 39.85,48.03 39.91,47.97 39.91,46.65 39.97,46.59 40.09,46.59 40.15,46.65 40.15,47.25 40.21,47.31 45.56,47.31 47.384,49.134 47.384,49.219 46.96,49.644 46.96,49.728 47.045,49.813 47.13,49.813 48.063,48.88 48.148,48.88 48.233,48.965 48.233,49.05 47.3,49.983 47.3,50.068 47.384,50.153 47.469,50.153 48.403,49.219 48.487,49.219 48.572,49.304 48.572,49.389 47.639,50.322 47.639,50.407 47.724,50.492 47.809,50.492 48.742,49.559 48.827,49.559 48.912,49.644 48.912,49.728 48.487,50.153 48.487,50.237 49.91,51.66 49.91,53.76 49.85,53.82 49.25,53.82 49.19,53.88 49.19,54 49.25,54.06 50.57,54.06 50.63,54.12 50.63,54.24 50.57,54.3 49.25,54.3 49.19,54.36 49.19,54.48 49.25,54.54 50.57,54.54 50.63,54.6 50.63,54.72 50.57,54.78 49.25,54.78 49.19,54.84 49.19,54.96 49.25,55.02 50.57,55.02 50.63,55.08 50.63,55.2 50.57,55.26 49.97,55.26 49.91,55.32 49.91,61.62 52.14,63.85 60.89,63.85 61.25,63.49 v1(61.23,63.49)
PA5: U5.P4 U15.1 | length 89.2
  Top w0.12: v1(30.8,38.85) U5.P4@31.2,38.45 ; v1(70.7,6.4) 70.75,6.35 U15.1@70.75,5.05
  F4 w0.12: v1(30.8,38.85) 30.4,38.45 29.7,38.45 29.2,37.95 28.05,37.95 27.35,37.25 27.35,29.3 27.65,29 27.65,19.95 40.75,6.85 41.26,6.85 41.32,6.79 41.32,6.55 41.38,6.49 41.5,6.49 41.56,6.55 41.56,7.09 41.62,7.15 41.74,7.15 41.8,7.09 41.8,6.55 41.86,6.49 41.98,6.49 42.04,6.55 42.04,7.09 42.1,7.15 42.22,7.15 42.28,7.09 42.28,6.55 42.34,6.49 42.46,6.49 42.52,6.55 42.52,7.09 42.58,7.15 42.7,7.15 42.76,7.09 42.76,6.55 42.82,6.49 42.94,6.49 43,6.55 43,7.09 43.06,7.15 43.18,7.15 43.24,7.09 43.24,6.55 43.3,6.49 43.42,6.49 43.48,6.55 43.48,7.09 43.54,7.15 43.66,7.15 43.72,7.09 43.72,6.55 43.78,6.49 43.9,6.49 43.96,6.55 43.96,7.09 44.02,7.15 44.14,7.15 44.2,7.09 44.2,6.55 44.26,6.49 44.38,6.49 44.44,6.55 44.44,7.09 44.5,7.15 44.62,7.15 44.68,7.09 44.68,6.55 44.74,6.49 44.86,6.49 44.92,6.55 44.92,7.09 44.98,7.15 45.1,7.15 45.16,7.09 45.16,6.55 45.22,6.49 45.34,6.49 45.4,6.55 45.4,7.09 45.46,7.15 45.58,7.15 45.64,7.09 45.64,6.55 45.7,6.49 45.82,6.49 45.88,6.55 45.88,7.09 45.94,7.15 46.06,7.15 46.12,7.09 46.12,6.55 46.18,6.49 46.3,6.49 46.36,6.55 46.36,7.09 46.42,7.15 46.54,7.15 46.6,7.09 46.6,6.55 46.66,6.49 46.78,6.49 46.84,6.55 46.84,7.09 46.9,7.15 47.02,7.15 47.08,7.09 47.08,6.55 47.14,6.49 47.26,6.49 47.32,6.55 47.32,7.09 47.38,7.15 47.5,7.15 47.56,7.09 47.56,6.55 47.62,6.49 47.74,6.49 47.8,6.55 47.8,7.09 47.86,7.15 47.98,7.15 48.04,7.09 48.04,6.55 48.1,6.49 48.22,6.49 48.28,6.55 48.28,6.79 48.29,6.8 64.3,6.8 64.6,6.5 70.6,6.5 v1(70.7,6.4)
PA6: P1.15 U5.P3 | length 75.5
  Top w0.12: v1(30.8,39.65) U5.P3@31.2,39.25 ; v1(62.2,64.15) 62.2,62.175 P1.15@62.25,62.175
  F5 w0.12: v1(30.8,39.65) 30.4,40.05 30.4,40.8 29.9,41.3 29.9,42.95 31.2,44.25 31.2,47.6 33.36,49.76 38.96,49.76 38.97,49.77 38.97,49.1 39.03,49.04 39.15,49.04 39.21,49.1 39.21,50.42 39.27,50.48 39.39,50.48 39.45,50.42 39.45,49.1 39.51,49.04 39.63,49.04 39.69,49.1 39.69,49.7 39.75,49.76 42.27,49.76 42.33,49.7 42.33,49.1 42.39,49.04 42.51,49.04 42.57,49.1 42.57,50.42 42.63,50.48 42.75,50.48 42.81,50.42 42.81,49.1 42.87,49.04 42.99,49.04 43.05,49.1 43.05,50.42 43.11,50.48 43.23,50.48 43.29,50.42 43.29,49.1 43.35,49.04 43.47,49.04 43.53,49.1 43.53,50.42 43.59,50.48 43.71,50.48 43.77,50.42 43.77,49.82 43.83,49.76 44.73,49.76 47.1,52.13 47.1,55.27 47.16,55.33 47.76,55.33 47.82,55.39 47.82,55.51 47.76,55.57 46.44,55.57 46.38,55.63 46.38,55.75 46.44,55.81 47.76,55.81 47.82,55.87 47.82,55.99 47.76,56.05 46.44,56.05 46.38,56.11 46.38,56.23 46.44,56.29 47.76,56.29 47.82,56.35 47.82,56.47 47.76,56.53 46.44,56.53 46.38,56.59 46.38,56.71 46.44,56.77 47.04,56.77 47.1,56.83 47.1,62.05 49.19,64.14 62.19,64.14 v1(62.2,64.15)
PA7: R66.2 U5.R3 | length 34.1
  Top w0.12: v1(30,39.65) U5.R3@30.4,39.25 ; R66.2@42.7,25.825 43.275,25.825 44.191,26.741 44.191,26.936 v1(44.225,26.97)
  F3 w0.12: v1(26.65,29.25) 26.65,29.3 26.8,29.45 28.95,29.45 30.75,27.65 31.5,27.65 32.18,26.97 38.72,26.97 39.02,26.67 42.983,26.67 43.283,26.97 v1(44.225,26.97)
  F4 w0.12: v1(26.65,29.25) 26.7,29.25 26.7,37.5 28.85,39.65 v1(30,39.65)
PA9: R63.2 R64.2 U5.E15 | length 4
  Top w0.12: U5.E15@38.4,29.65 v1(38.8,29.25) R63.2@38.8,27.1 ; R63.2@38.75,27.1 R63.2@38.8,27.1 ; R64.2@40,27.1 R63.2@38.8,27.1
PA10: R133.1 U5.D15 | length 63.7
  Top w0.12: U5.D15@39.2,29.65 v1(39.6,29.25) ; v1(79.42,-4.7) 79.47,-4.75 R133.1@81,-4.75
  F3 w0.12: v1(39.6,29.25) 39.6,28.16 40.61,27.15 42.631,27.15 43.351,27.87 57.88,27.87 78.39,7.36 78.39,-3.67 v1(79.42,-4.7)
PA11: R132.1 U5.C15 U18.5 | length 70.3
  Top w0.15: U5.C15@40,29.65 40.25,29.4 40.25,29.01 40.61,28.65 41.631,28.65 42.491,27.79 50.83,27.79 52.92,25.7 55.911,25.7 57.1,24.511 57.1,17.33 60.82,13.61 62.471,13.61 64.521,11.56 68.291,11.56 73.421,6.43 77.21,6.43 80.09,3.55 80.09,-1.62 79.84,-1.87 79.84,-2.51 80.21,-2.88 v1(80.21,-3.49) 80.85,-3.49 80.91,-3.55 R132.1@81,-3.55 ; U18.5@85.325,-2.7 85.476,-2.7 85.695,-2.919 85.695,-3.281 85.581,-3.395 85.579,-3.395 85.46,-3.514 v1(85.452,-3.514)
  Bottom w0.15: v1(80.21,-3.49) 80.79,-2.91 84.84,-2.91 85.444,-3.514 v1(85.452,-3.514)
PA12: R125.1 U5.B15 U18.6 | length 68.7
  Top w0.15: U5.B15@40.8,29.65 40.53,29.38 40.53,29.119 40.719,28.93 41.74,28.93 42.6,28.07 50.939,28.07 53.009,26 56,26 57.4,24.6 57.4,17.419 60.929,13.89 62.58,13.89 64.63,11.84 68.4,11.84 73.53,6.71 77.319,6.71 80.37,3.659 80.37,-1.72 R125.1@80.93,-2.28 ; v1(80.27,-2.28) R125.1@80.93,-2.28 ; R125.1@81,-2.35 R125.1@80.94,-2.29 ; U18.6@85.45,-2.3 85.955,-2.3 v1(85.98,-2.275) ; R125.1@80.93,-2.28 R125.1@80.94,-2.29 ; R125.1@80.93,-2.28 80.95,-2.28 R125.1@80.94,-2.29
  Bottom w0.15: v1(80.27,-2.28) 80.62,-2.63 83.18,-2.63 83.535,-2.275 v1(85.98,-2.275)
PA13: SB17.2 U5.A15 | length 67.5
  Top w0.12: U5.A15@41.6,29.65 v1(42,29.25) 42.95,29.25 43.5,28.7 49.3,28.7 50.35,29.75 56.31,29.75 57.21,28.85 64.6,28.85 v1(65.1,28.35) ; v1(93.4,1.8) 93.95,1.25 SB17.2@95.4,1.25
  F3 w0.12: v1(65.1,28.35) 65.35,28.1 69,28.1 93.4,3.7 v1(93.4,1.8)
PA14: SB14.2 U5.A14 | length 66.3
  Top w0.12: U5.A14@41.6,30.45 v1(42,30.05) ; v1(94,5.7) 95.4,5.7 SB14.2@95.4,5.75
  F3 w0.12: v1(42,30.05) 42.7,30.05 43.8,31.15 48.05,31.15 49.65,32.75 53.361,32.75 55.511,30.6 67.55,30.6 92.45,5.7 v1(94,5.7)
PB0: U5.R5 U15.4 | length 88.2
  Top w0.12: v1(30,38.05) U5.R5@30.4,37.65 ; U15.4@69.25,5.05 v1(69.25,6.9)
  F4 w0.12: v1(30,38.05) 29.7,38.05 29.35,37.7 28.15,37.7 27.6,37.15 27.6,29.4 27.9,29.1 27.9,20.35 40.5,7.75 50.63,7.75 50.69,7.81 50.69,8.27 50.75,8.33 50.87,8.33 50.93,8.27 50.93,7.37 50.99,7.31 51.11,7.31 51.17,7.37 51.17,8.27 51.23,8.33 51.35,8.33 51.41,8.27 51.41,7.37 51.47,7.31 51.59,7.31 51.65,7.37 51.65,8.27 51.71,8.33 51.83,8.33 51.89,8.27 51.89,7.37 51.95,7.31 52.07,7.31 52.13,7.37 52.13,8.27 52.19,8.33 52.31,8.33 52.37,8.27 52.37,7.37 52.43,7.31 52.55,7.31 52.61,7.37 52.61,8.27 52.67,8.33 52.79,8.33 52.85,8.27 52.85,7.37 52.91,7.31 53.03,7.31 53.09,7.37 53.09,8.27 53.15,8.33 53.27,8.33 53.33,8.27 53.33,7.37 53.39,7.31 53.51,7.31 53.57,7.37 53.57,8.27 53.63,8.33 53.75,8.33 53.81,8.27 53.81,7.37 53.87,7.31 53.99,7.31 54.05,7.37 54.05,8.27 54.11,8.33 54.23,8.33 54.29,8.27 54.29,7.37 54.35,7.31 54.47,7.31 54.53,7.37 54.53,8.27 54.59,8.33 54.71,8.33 54.77,8.27 54.77,7.37 54.83,7.31 54.95,7.31 55.01,7.37 55.01,8.27 55.07,8.33 55.19,8.33 55.25,8.27 55.25,7.37 55.31,7.31 55.43,7.31 55.49,7.37 55.49,7.85 55.56,7.921 63.779,7.921 64.8,6.9 v1(69.25,6.9)
PB1: U5.R4 U15.5 | length 89.1
  Top w0.12: v1(30,38.85) U5.R4@30.4,38.45 ; U15.5@68.75,5.05 v1(68.75,6.1)
  F4 w0.12: v1(30,38.85) 29.6,38.85 28.95,38.2 27.85,38.2 27.1,37.45 27.1,29.15 27.4,28.85 27.4,19.65 41.01,6.04 49.63,6.04 49.69,6.1 49.69,6.34 49.75,6.4 49.87,6.4 49.93,6.34 49.93,5.86 49.99,5.8 50.11,5.8 50.17,5.86 50.17,6.34 50.23,6.4 50.35,6.4 50.41,6.34 50.41,5.86 50.47,5.8 50.59,5.8 50.65,5.86 50.65,6.34 50.71,6.4 50.83,6.4 50.89,6.34 50.89,5.86 50.95,5.8 51.07,5.8 51.13,5.86 51.13,6.34 51.19,6.4 51.31,6.4 51.37,6.34 51.37,5.86 51.43,5.8 51.55,5.8 51.61,5.86 51.61,6.34 51.67,6.4 51.79,6.4 51.85,6.34 51.85,5.86 51.91,5.8 52.03,5.8 52.09,5.86 52.09,6.34 52.15,6.4 52.27,6.4 52.33,6.34 52.33,5.86 52.39,5.8 52.51,5.8 52.57,5.86 52.57,6.34 52.63,6.4 52.75,6.4 52.81,6.34 52.81,5.86 52.87,5.8 52.99,5.8 53.05,5.86 53.05,6.34 53.11,6.4 53.23,6.4 53.29,6.34 53.29,5.86 53.35,5.8 53.47,5.8 53.53,5.86 53.53,6.34 53.59,6.4 53.71,6.4 53.77,6.34 53.77,5.86 53.83,5.8 53.95,5.8 54.01,5.86 54.01,6.34 54.07,6.4 54.19,6.4 54.25,6.34 54.25,5.86 54.31,5.8 54.43,5.8 54.49,5.86 54.49,6.34 54.55,6.4 54.67,6.4 54.73,6.34 54.73,5.86 54.79,5.8 54.91,5.8 54.97,5.86 54.97,6.34 55.03,6.4 55.15,6.4 55.21,6.34 55.21,5.86 55.27,5.8 55.39,5.8 55.45,5.86 55.45,6.34 55.51,6.4 55.63,6.4 55.69,6.34 55.69,5.86 55.75,5.8 55.87,5.8 55.93,5.86 55.93,6.34 55.99,6.4 56.11,6.4 56.17,6.34 56.17,5.86 56.23,5.8 56.35,5.8 56.41,5.86 56.41,6.34 56.47,6.4 56.59,6.4 56.65,6.34 56.65,5.86 56.71,5.8 56.83,5.8 56.89,5.86 56.89,6.34 56.95,6.4 57.07,6.4 57.13,6.34 57.13,5.86 57.19,5.8 57.31,5.8 57.37,5.86 57.37,6.34 57.43,6.4 57.55,6.4 57.61,6.34 57.61,5.86 57.67,5.8 57.79,5.8 57.85,5.86 57.85,6.34 57.91,6.4 58.03,6.4 58.09,6.34 58.09,6.1 58.15,6.04 58.59,6.04 59.05,6.5 59.105,6.555 63.595,6.555 63.65,6.5 64.05,6.1 68.7,6.1 68.75,6.15 v1(68.75,6.1)
PB2: R44.1 U3.6 | length 52.9
  Top w0.12: v1(24.05,42.85) 23.6,42.4 23.6,40.25 25.1,38.75 R44.1@26.65,38.75 ; v1(68.2,40.25) 68.641,39.809 U3.6@69.272,39.809
  Bottom w0.12: v1(24.05,42.85) 24.15,42.75 42.3,42.75 42.8,42.25 66.2,42.25 v1(68.2,40.25)
PB3: SB16.2 U5.A10 | length 67
  Top w0.12: U5.A10@41.6,33.65 42.25,33.65 43.05,32.85 47.6,32.85 48.1,32.35 v1(50.95,32.35) ; v1(94.2,2.75) SB16.2@95.4,2.75
  F3 w0.12: v1(50.95,32.35) 53.422,32.35 55.572,30.2 64.35,30.2 v1(65.85,28.7) 68.85,28.7 94.2,3.35 v1(94.2,2.75)
PB5: U5.A8 U15.13 | length 89.9
  Top w0.12: U5.A8@41.6,35.25 42.35,35.25 43.2,34.4 47.7,34.4 v1(48.4,33.7) ; v1(65.65,2.85) 66,2.5 U15.13@66.7,2.5
  F6 w0.12: v1(48.4,33.7) 49.67,32.43 49.67,29.989 52.53,27.129 52.53,26.22 55.4,23.35 55.4,21.9 58.8,18.5 60.25,18.5 61.482,17.268 61.567,17.268 61.895,17.596 61.98,17.596 62.065,17.511 62.065,17.426 61.426,16.788 61.426,16.703 61.511,16.618 61.596,16.618 62.234,17.256 62.319,17.256 62.404,17.171 62.404,17.087 61.766,16.448 61.766,16.363 61.851,16.278 61.935,16.278 62.574,16.917 62.659,16.917 62.743,16.832 62.743,16.747 62.105,16.109 62.105,16.024 62.19,15.939 62.275,15.939 62.913,16.577 62.998,16.577 63.083,16.493 63.083,16.408 62.445,15.769 62.445,15.684 62.529,15.6 62.614,15.6 62.84,15.825 62.925,15.825 63.97,14.78 63.97,14.32 64.03,14.26 64.39,14.26 64.45,14.2 64.45,14.08 64.39,14.02 63.52,14.02 63.46,13.96 63.46,13.84 63.52,13.78 64.39,13.78 64.45,13.72 64.45,13.6 64.39,13.54 63.52,13.54 63.46,13.48 63.46,13.36 63.52,13.3 64.39,13.3 64.45,13.24 64.45,13.12 64.39,13.06 63.52,13.06 63.46,13 63.46,12.88 63.52,12.82 64.39,12.82 64.45,12.76 64.45,12.64 64.39,12.58 63.52,12.58 63.46,12.52 63.46,12.4 63.52,12.34 64.39,12.34 64.45,12.28 64.45,12.16 64.39,12.1 63.52,12.1 63.46,12.04 63.46,11.92 63.52,11.86 64.39,11.86 64.45,11.8 64.45,11.68 64.39,11.62 63.52,11.62 63.46,11.56 63.46,11.44 63.52,11.38 64.39,11.38 64.45,11.32 64.45,11.2 64.39,11.14 63.52,11.14 63.46,11.08 63.46,10.96 63.52,10.9 64.39,10.9 64.45,10.84 64.45,10.72 64.39,10.66 63.52,10.66 63.46,10.6 63.46,10.48 63.52,10.42 64.39,10.42 64.45,10.36 64.45,10.24 64.39,10.18 63.52,10.18 63.46,10.12 63.46,10 63.52,9.94 64.39,9.94 64.45,9.88 64.45,9.76 64.39,9.7 63.52,9.7 63.46,9.64 63.46,9.52 63.52,9.46 64.39,9.46 64.45,9.4 64.45,9.28 64.39,9.22 63.52,9.22 63.46,9.16 63.46,9.04 63.52,8.98 64.39,8.98 64.45,8.92 64.45,8.8 64.39,8.74 63.52,8.74 63.46,8.68 63.46,8.56 63.52,8.5 64.39,8.5 64.45,8.44 64.45,8.32 64.39,8.26 63.52,8.26 63.46,8.2 63.46,8.08 63.52,8.02 64.39,8.02 64.45,7.96 64.45,7.84 64.39,7.78 63.52,7.78 63.46,7.72 63.46,7.6 63.52,7.54 64.39,7.54 64.45,7.48 64.45,7.36 64.39,7.3 63.52,7.3 63.46,7.24 63.46,7.12 63.52,7.06 64.39,7.06 64.45,7 64.45,6.88 64.39,6.82 63.52,6.82 63.46,6.76 63.46,6.64 63.52,6.58 64.39,6.58 64.45,6.52 64.45,6.4 64.39,6.34 63.52,6.34 63.46,6.28 63.46,6.16 63.52,6.1 64.39,6.1 64.45,6.04 64.45,5.92 64.39,5.86 63.52,5.86 63.46,5.8 63.46,5.68 63.52,5.62 64.39,5.62 64.45,5.56 64.45,5.44 64.39,5.38 63.52,5.38 63.46,5.32 63.46,5.2 63.52,5.14 63.91,5.14 63.97,5.08 63.97,4.53 v1(65.65,2.85)
PB6: R57.1 U3.1 U5.B6 | length 53.2
  Top w0.12: U5.B6@40.8,36.85 v1(41.2,37.25) ; v1(73.85,35.45) R57.1@73.85,34.75 76.55,34.75 77.122,35.322 U3.1@77.122,37.269
  F5 w0.12: v1(41.2,37.25) 42.25,37.25 42.65,37.65 47.3,37.65 47.55,37.4 51.05,37.4 51.7,36.75 56.19,36.75 57.66,38.22 62.9,38.22 63.25,37.87 63.25,36.4 63.5,36.15 64.6,36.15 64.85,36.4 64.85,37.04 65.41,37.6 67.48,37.6 67.8,37.28 67.8,36.66 67.86,36.6 67.99,36.6 68.05,36.66 68.05,37.99 68.11,38.05 68.24,38.05 68.3,37.99 68.3,36.66 68.36,36.6 68.49,36.6 68.55,36.66 68.55,37.99 68.61,38.05 68.74,38.05 68.8,37.99 68.8,36.66 68.86,36.6 68.99,36.6 69.05,36.66 69.05,37.99 69.11,38.05 69.24,38.05 69.3,37.99 69.3,37.4 69.36,37.34 73.51,37.34 73.85,37 v1(73.85,35.45)
PB7: SB12.1 U5.B5 | length 83.1
  Top w0.12: U5.B5@40.8,37.65 v1(41.2,38.05) ; v1(93.3,9) 93.55,8.75 SB12.1@95.5,8.75
  F3 w0.12: v1(41.2,38.05) 42,38.85 46.75,38.85 47.5,39.6 48.25,39.6 50.5,41.85 v1(50.5,42.75)
  Bottom w0.12: v1(50.5,42.75) 52,44.25 71,44.25 80.9,34.35 80.9,16.6 88.5,9 v1(93.3,9)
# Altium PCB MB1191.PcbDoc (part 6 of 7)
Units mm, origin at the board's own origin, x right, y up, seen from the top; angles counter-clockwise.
Board outline 130 x 80 mm, 8 copper layers (Top, F2, F3, F4, F5, F6, F7, Bottom), stack 1.115 mm thick; 360 components, 347 nets, 1451 pads, 1068 vias.

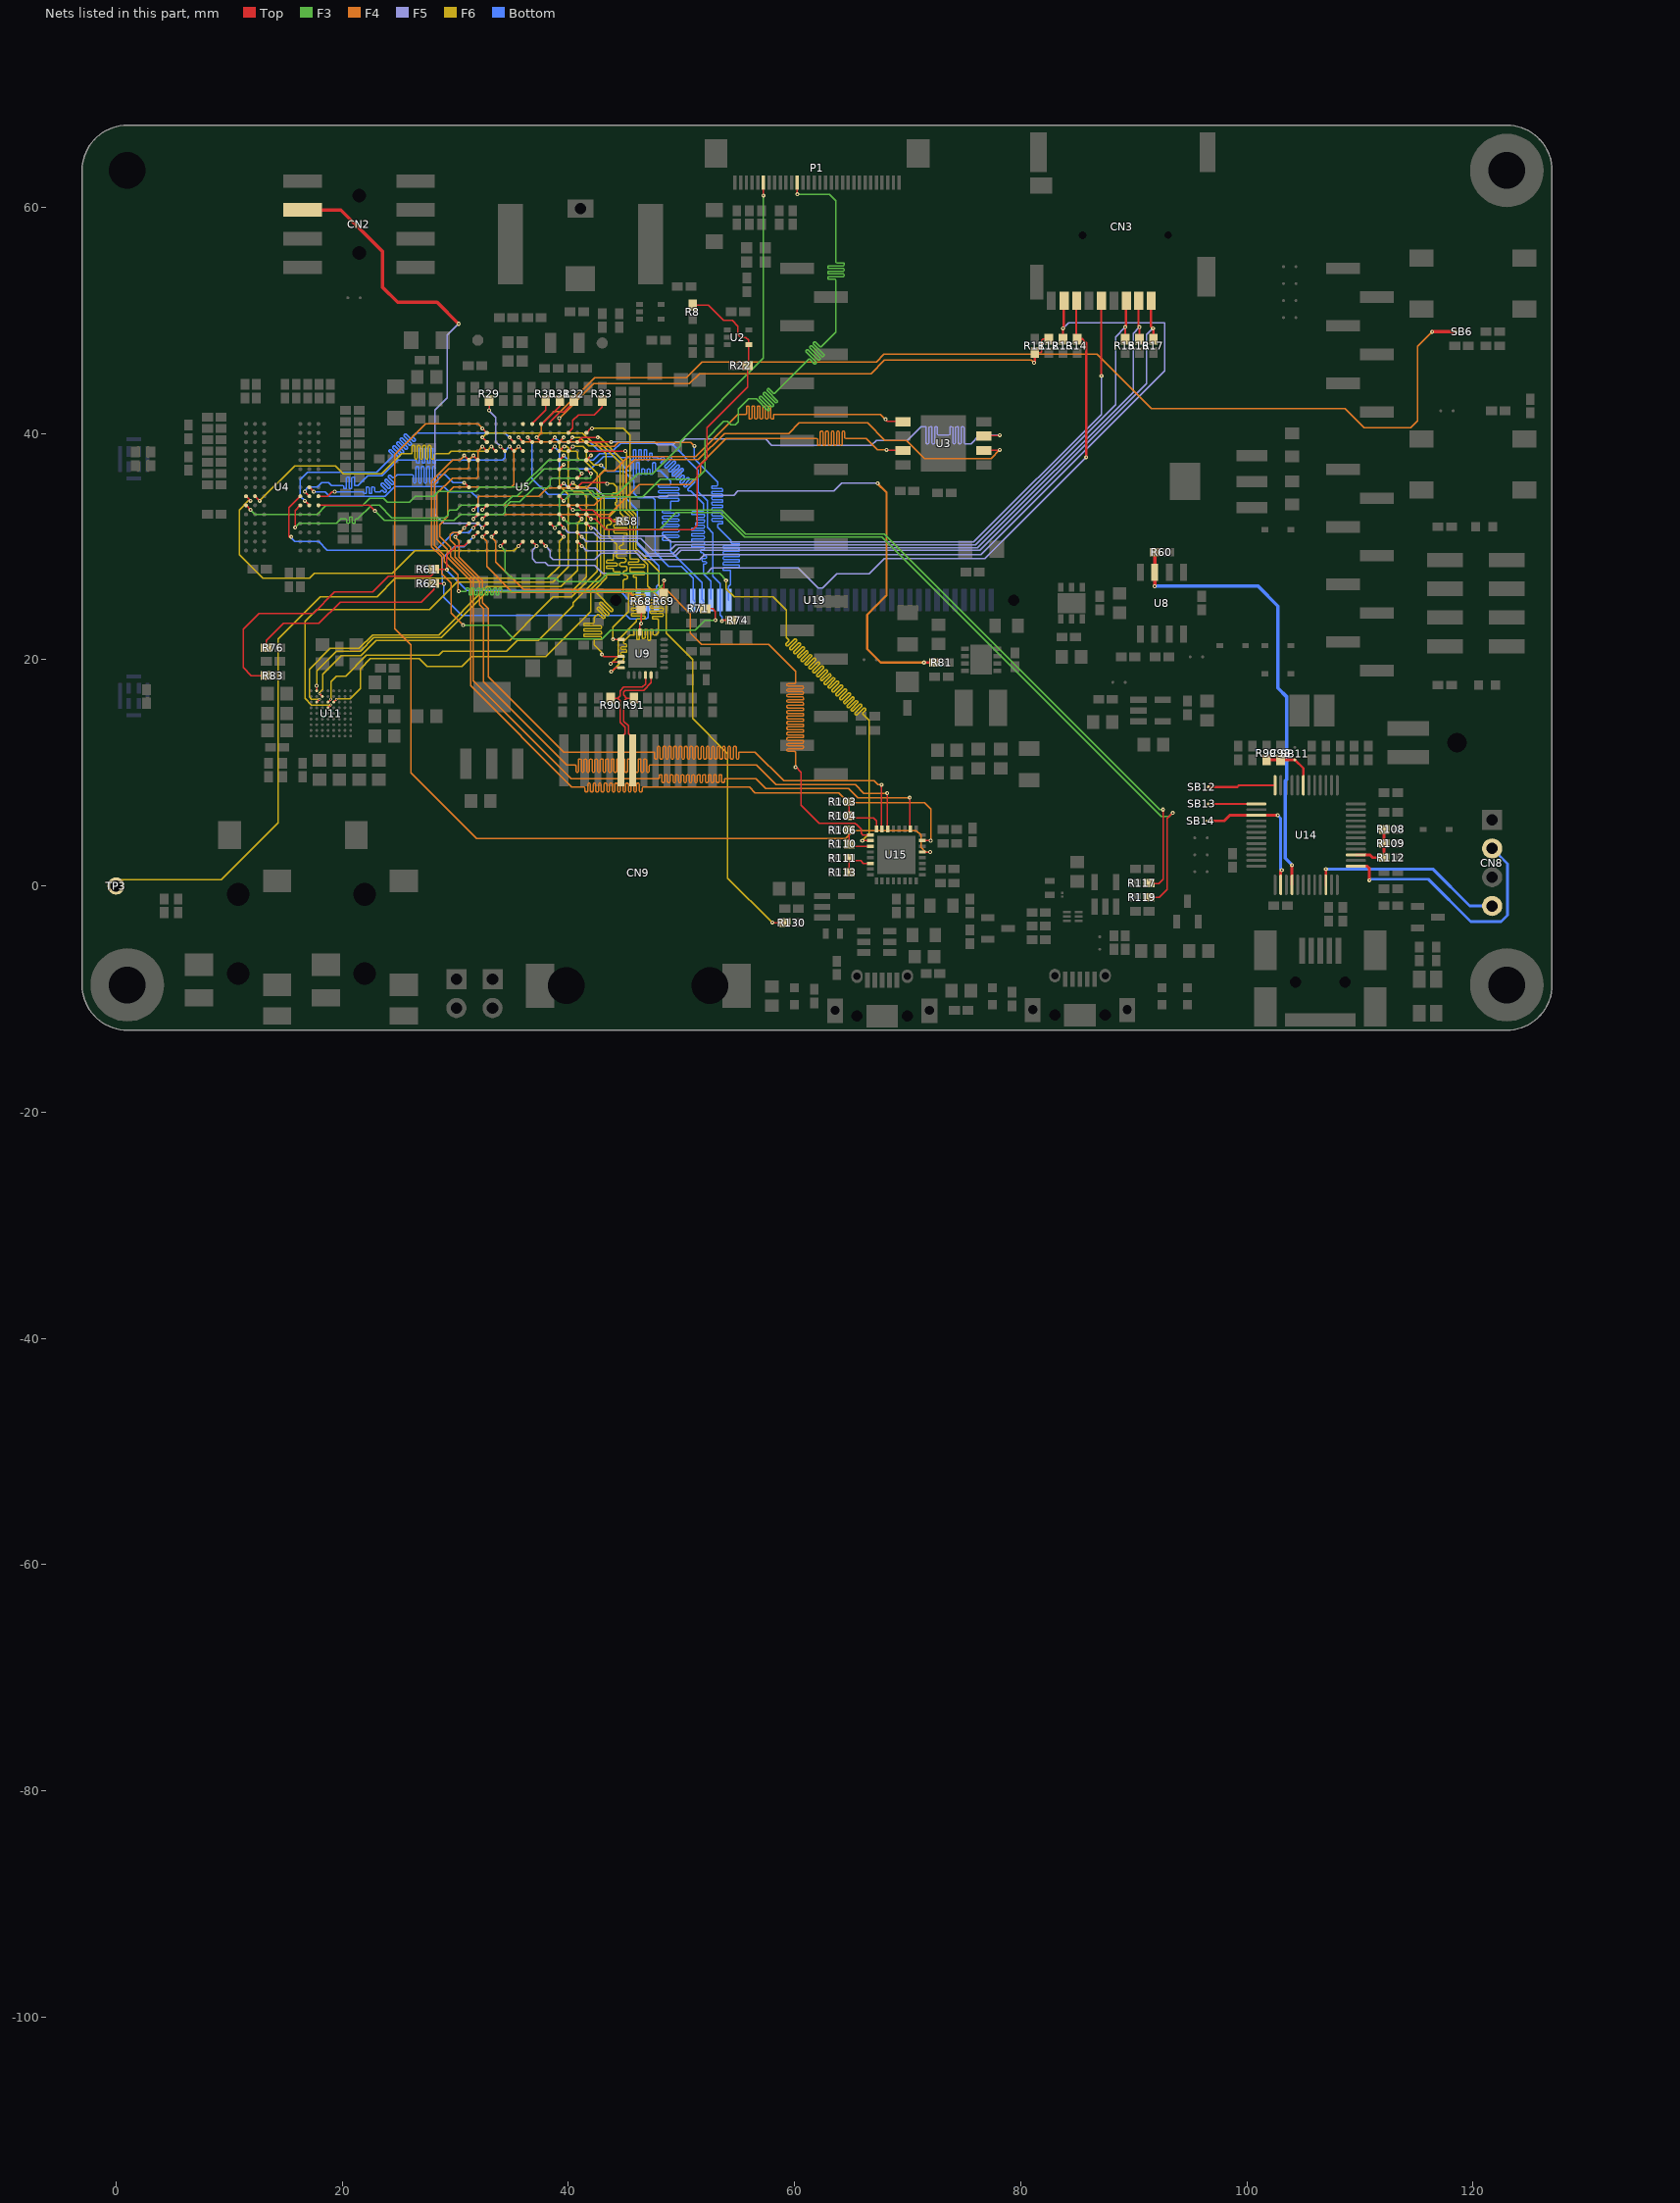
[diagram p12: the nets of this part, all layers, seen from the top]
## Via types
v1: diameter 0.35, hole 0.15, Top to Bottom, tented both sides, 1041 vias
v2: diameter 0.25, hole 0.1, Top to Bottom, tented both sides, 26 vias
v3: diameter 0.3, hole 0.1, Top to Bottom, tented both sides, 1 vias

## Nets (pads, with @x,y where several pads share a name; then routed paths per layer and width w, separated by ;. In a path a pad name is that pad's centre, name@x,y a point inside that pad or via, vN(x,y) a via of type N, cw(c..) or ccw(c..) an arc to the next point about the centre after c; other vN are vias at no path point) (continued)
PB10: U5.P12 U15.6 | length 89.2
  Top w0.12: v1(30.8,31.65) U5.P12@31.2,32.05 ; v1(68.2,8.2) 68.2,5.05 U15.6@68.25,5.05
  F4 w0.12: v1(30.8,31.65) 30.4,31.25 29.75,31.25 29.55,31.05 29.55,30.6 30,30.15 30,29.05 32.15,26.9 32.15,24.85 32.5,24.5 32.5,18.05 39.87,10.68 40.61,10.68 40.67,10.62 40.67,10.11 40.73,10.05 40.85,10.05 40.91,10.11 40.91,11.17 40.97,11.23 41.09,11.23 41.15,11.17 41.15,10.11 41.21,10.05 41.33,10.05 41.39,10.11 41.39,11.17 41.45,11.23 41.57,11.23 41.63,11.17 41.63,10.11 41.69,10.05 41.81,10.05 41.87,10.11 41.87,11.17 41.93,11.23 42.05,11.23 42.11,11.17 42.11,10.11 42.17,10.05 42.29,10.05 42.35,10.11 42.35,11.17 42.41,11.23 42.53,11.23 42.59,11.17 42.59,10.11 42.65,10.05 42.77,10.05 42.83,10.11 42.83,11.17 42.89,11.23 43.01,11.23 43.07,11.17 43.07,10.11 43.13,10.05 43.25,10.05 43.31,10.11 43.31,11.17 43.37,11.23 43.49,11.23 43.55,11.17 43.55,10.11 43.61,10.05 43.73,10.05 43.79,10.11 43.79,11.17 43.85,11.23 43.97,11.23 44.03,11.17 44.03,10.11 44.09,10.05 44.21,10.05 44.27,10.11 44.27,11.17 44.33,11.23 44.45,11.23 44.51,11.17 44.51,10.11 44.57,10.05 44.69,10.05 44.75,10.11 44.75,11.17 44.81,11.23 44.93,11.23 44.99,11.17 44.99,10.11 45.05,10.05 45.17,10.05 45.23,10.11 45.23,11.17 45.29,11.23 45.41,11.23 45.47,11.17 45.47,10.11 45.53,10.05 45.65,10.05 45.71,10.11 45.71,11.17 45.77,11.23 45.89,11.23 45.95,11.17 45.95,10.11 46.01,10.05 46.13,10.05 46.19,10.11 46.19,11.17 46.25,11.23 46.37,11.23 46.43,11.17 46.43,10.11 46.49,10.05 46.61,10.05 46.67,10.11 46.67,11.17 46.73,11.23 46.85,11.23 46.91,11.17 46.91,10.11 46.97,10.05 47.09,10.05 47.15,10.11 47.15,10.62 47.21,10.68 56.64,10.68 58.36,8.96 65.39,8.96 66.15,8.2 v1(68.2,8.2)
PB11: U5.R13 U15.7 | length 89.1
  Top w0.12: v1(30,30.85) U5.R13@30.4,31.25 ; v1(67.7,8.95) 67.7,5.05 U15.7@67.75,5.05
  F4 w0.12: v1(30,30.85) 30.35,30.5 30.35,29.05 32.4,27 32.4,25.05 32.95,24.5 32.95,18.5 39.62,11.83 47.58,11.83 47.64,11.77 47.64,11.28 47.7,11.22 47.82,11.22 47.88,11.28 47.88,12.27 47.94,12.33 48.06,12.33 48.12,12.27 48.12,11.28 48.18,11.22 48.3,11.22 48.36,11.28 48.36,12.27 48.42,12.33 48.54,12.33 48.6,12.27 48.6,11.28 48.66,11.22 48.78,11.22 48.84,11.28 48.84,12.27 48.9,12.33 49.02,12.33 49.08,12.27 49.08,11.28 49.14,11.22 49.26,11.22 49.32,11.28 49.32,12.27 49.38,12.33 49.5,12.33 49.56,12.27 49.56,11.28 49.62,11.22 49.74,11.22 49.8,11.28 49.8,12.27 49.86,12.33 49.98,12.33 50.04,12.27 50.04,11.28 50.1,11.22 50.22,11.22 50.28,11.28 50.28,12.27 50.34,12.33 50.46,12.33 50.52,12.27 50.52,11.28 50.58,11.22 50.7,11.22 50.76,11.28 50.76,12.27 50.82,12.33 50.94,12.33 51,12.27 51,11.28 51.06,11.22 51.18,11.22 51.24,11.28 51.24,12.27 51.3,12.33 51.42,12.33 51.48,12.27 51.48,11.28 51.54,11.22 51.66,11.22 51.72,11.28 51.72,12.27 51.78,12.33 51.9,12.33 51.96,12.27 51.96,11.28 52.02,11.22 52.14,11.22 52.2,11.28 52.2,12.27 52.26,12.33 52.38,12.33 52.44,12.27 52.44,11.28 52.5,11.22 52.62,11.22 52.68,11.28 52.68,12.27 52.74,12.33 52.86,12.33 52.92,12.27 52.92,11.28 52.98,11.22 53.1,11.22 53.16,11.28 53.16,12.27 53.22,12.33 53.34,12.33 53.4,12.27 53.4,11.28 53.46,11.22 53.58,11.22 53.64,11.28 53.64,12.27 53.7,12.33 53.82,12.33 53.88,12.27 53.88,11.28 53.94,11.22 54.06,11.22 54.12,11.28 54.12,12.27 54.18,12.33 54.3,12.33 54.36,12.27 54.36,11.28 54.42,11.22 54.54,11.22 54.6,11.28 54.6,12.27 54.66,12.33 54.78,12.33 54.84,12.27 54.84,11.28 54.9,11.22 55.02,11.22 55.08,11.28 55.08,11.77 55.14,11.83 56.52,11.83 59.06,9.29 67.06,9.29 67.4,8.95 v1(67.7,8.95)
PB12: U5.L13 U15.9 | length 89.2
  Top w0.12: v1(33.2,30.85) U5.L13@33.6,31.25 ; v1(60.1,10.5) 60.1,10.55 60.6,10.05 60.6,7.15 62.2,5.55 65.367,5.55 65.511,5.406 65.511,5.389 65.9,5 65.9,4.65 66.05,4.5 U15.9@66.7,4.5
  F4 w0.12: v1(33.2,30.85) 33.6,30.45 33.6,28.65 36.06,26.19 48.66,26.19 50.8,24.05 50.8,22.35 51.8,21.35 57.74,21.35 60.1,18.99 60.1,17.96 60.04,17.9 59.4,17.9 59.34,17.84 59.34,17.72 59.4,17.66 60.76,17.66 60.82,17.6 60.82,17.48 60.76,17.42 59.4,17.42 59.34,17.36 59.34,17.24 59.4,17.18 60.76,17.18 60.82,17.12 60.82,17 60.76,16.94 59.4,16.94 59.34,16.88 59.34,16.76 59.4,16.7 60.76,16.7 60.82,16.64 60.82,16.52 60.76,16.46 59.4,16.46 59.34,16.4 59.34,16.28 59.4,16.22 60.76,16.22 60.82,16.16 60.82,16.04 60.76,15.98 59.4,15.98 59.34,15.92 59.34,15.8 59.4,15.74 60.76,15.74 60.82,15.68 60.82,15.56 60.76,15.5 59.4,15.5 59.34,15.44 59.34,15.32 59.4,15.26 60.76,15.26 60.82,15.2 60.82,15.08 60.76,15.02 59.4,15.02 59.34,14.96 59.34,14.84 59.4,14.78 60.76,14.78 60.82,14.72 60.82,14.6 60.76,14.54 59.4,14.54 59.34,14.48 59.34,14.36 59.4,14.3 60.76,14.3 60.82,14.24 60.82,14.12 60.76,14.06 59.4,14.06 59.34,14 59.34,13.88 59.4,13.82 60.76,13.82 60.82,13.76 60.82,13.64 60.76,13.58 59.4,13.58 59.34,13.52 59.34,13.4 59.4,13.34 60.76,13.34 60.82,13.28 60.82,13.16 60.76,13.1 59.4,13.1 59.34,13.04 59.34,12.92 59.4,12.86 60.76,12.86 60.82,12.8 60.82,12.68 60.76,12.62 59.4,12.62 59.34,12.56 59.34,12.44 59.4,12.38 60.76,12.38 60.82,12.32 60.82,12.2 60.76,12.14 59.4,12.14 59.34,12.08 59.34,11.96 59.4,11.9 60.04,11.9 60.1,11.84 v1(60.1,10.5)
PB13: U5.K14 U15.10 | length 89.4
  Top w0.12: v1(34,30.05) U5.K14@34.4,30.45 ; v1(66,4) U15.10@66.7,4
  F3 w0.12: v1(34,30.05) 34.4,29.65 34.4,27.8 34.99,27.21 38.87,27.21 39.17,26.91 42.73,26.91 43.45,27.63 53.37,27.63 54,27 v1(53.95,27)
  F6 w0.12: v1(53.95,27) 53.95,26.26 54.67,25.54 58.11,25.54 59.27,24.38 59.27,21.98 59.512,21.738 59.512,21.653 59.241,21.382 59.241,21.297 59.326,21.212 59.411,21.212 60.021,21.823 60.106,21.823 60.191,21.738 60.191,21.653 59.581,21.043 59.581,20.958 59.665,20.873 59.75,20.873 60.36,21.483 60.445,21.483 60.53,21.398 60.53,21.314 59.92,20.703 59.92,20.618 60.005,20.534 60.09,20.534 60.7,21.144 60.785,21.144 60.87,21.059 60.87,20.974 60.259,20.364 60.259,20.279 60.344,20.194 60.429,20.194 61.039,20.804 61.124,20.804 61.209,20.72 61.209,20.635 60.599,20.024 60.599,19.94 60.684,19.855 60.769,19.855 61.379,20.465 61.464,20.465 61.548,20.38 61.548,20.295 60.938,19.685 60.938,19.6 61.023,19.515 61.108,19.515 61.718,20.126 61.803,20.126 61.888,20.041 61.888,19.956 61.278,19.346 61.278,19.261 61.363,19.176 61.447,19.176 62.058,19.786 62.142,19.786 62.227,19.701 62.227,19.616 61.617,19.006 61.617,18.921 61.702,18.837 61.787,18.837 62.397,19.447 62.482,19.447 62.567,19.362 62.567,19.277 61.956,18.667 61.956,18.582 62.041,18.497 62.126,18.497 62.736,19.107 62.821,19.107 62.906,19.022 62.906,18.938 62.296,18.327 62.296,18.243 62.381,18.158 62.466,18.158 63.076,18.768 63.161,18.768 63.246,18.683 63.246,18.598 62.635,17.988 62.635,17.903 62.72,17.818 62.805,17.818 63.415,18.428 63.5,18.428 63.585,18.344 63.585,18.259 62.975,17.649 62.975,17.564 63.06,17.479 63.144,17.479 63.755,18.089 63.839,18.089 63.924,18.004 63.924,17.919 63.314,17.309 63.314,17.224 63.399,17.139 63.484,17.139 64.094,17.75 64.179,17.75 64.264,17.665 64.264,17.58 63.654,16.97 63.654,16.885 63.738,16.8 63.823,16.8 64.434,17.41 64.518,17.41 64.603,17.325 64.603,17.24 63.993,16.63 63.993,16.545 64.078,16.461 64.163,16.461 64.773,17.071 64.858,17.071 64.943,16.986 64.943,16.901 64.332,16.291 64.332,16.206 64.417,16.121 64.502,16.121 65.112,16.731 65.197,16.731 65.282,16.646 65.282,16.562 64.672,15.951 64.672,15.867 64.757,15.782 64.842,15.782 65.452,16.392 65.537,16.392 65.621,16.307 65.621,16.222 65.011,15.612 65.011,15.527 65.096,15.442 65.181,15.442 65.791,16.053 65.876,16.053 65.961,15.968 65.961,15.883 65.351,15.273 65.351,15.188 65.436,15.103 65.52,15.103 66.131,15.713 66.215,15.713 66.3,15.628 66.3,15.543 66.046,15.289 66.046,15.204 66.62,14.63 66.62,4.64 66,4.02 v1(66,4)
PC0: U5.M2 U15.29 | length 89
  Top w0.12: v1(32.4,40.45) U5.M2@32.8,40.05 ; U15.29@71.3,3 v1(72,3)
  F4 w0.12: v1(32.4,40.45) 32,40.85 27.4,40.85 24.67,38.12 24.67,22.73 26.1,21.3 26.1,9.99 31.9,4.19 64.54,4.19 65.25,4.9 70.77,4.9 71.18,4.49 71.18,3.42 71.6,3 v1(72,3)
PC1: U5.M3 U9.13 | length 42.6
  Top w0.12: v1(32.4,39.65) U5.M3@32.8,39.25 ; v1(43.95,21.8) 43.95,21.789 U9.13@44.672,21.789
  F6 w0.12: v1(32.4,39.65) 32.8,40.05 41.25,40.05 42.15,39.15 42.8,39.15 44.57,37.38 44.57,32.99 44.91,32.65 45.142,32.65 45.21,32.582 45.21,32.47 45.15,32.41 44.09,32.41 44.03,32.35 44.03,32.23 44.09,32.17 45.15,32.17 45.21,32.11 45.21,31.99 45.15,31.93 44.09,31.93 44.03,31.87 44.03,31.75 44.09,31.69 45.15,31.69 45.21,31.63 45.21,31.51 45.15,31.45 44.09,31.45 44.03,31.39 44.03,31.27 44.09,31.21 45.15,31.21 45.21,31.15 45.21,31.03 45.15,30.97 44.91,30.97 44.85,30.91 44.85,30.525 44.85,30.477 44.85,30.215 44.738,30.103 44.632,30.103 44.52,29.991 44.52,29.841 44.632,29.729 44.85,29.729 45.098,29.729 45.21,29.617 45.21,29.467 45.098,29.355 44.85,29.355 44.364,29.355 44.252,29.243 44.252,29.093 44.364,28.981 44.85,28.981 44.996,28.981 45.108,28.869 45.108,28.719 44.996,28.607 44.85,28.607 44.662,28.607 44.55,28.495 44.55,28.345 44.662,28.233 44.85,28.233 45.098,28.233 45.21,28.121 45.21,27.971 45.098,27.859 44.962,27.859 44.85,27.747 44.85,27.597 44.962,27.485 45.112,27.485 45.224,27.373 45.224,27.223 45.112,27.111 44.962,27.111 44.85,26.999 44.85,26.737 44.85,26.55 44.85,25.99 44.91,25.93 45.27,25.93 45.33,25.87 45.33,24.25 44.85,23.77 43.95,22.87 v1(43.95,21.8)
PC2: U5.M4 U15.31 | length 89.1
  Top w0.12: v1(32.4,38.85) U5.M4@32.8,38.45 ; U15.31@71.3,4 v1(72.05,4)
  F4 w0.12: v1(32.4,38.85) 32,38.45 32,36.15 31.9,36.05 29.75,36.05 28.4,34.7 28.4,30.65 29.3,29.75 29.3,29.05 31.35,27 31.35,17.7 40.32,8.73 41.42,8.73 41.48,8.67 41.48,8.38 41.54,8.32 41.66,8.32 41.72,8.38 41.72,9.02 41.78,9.08 41.9,9.08 41.96,9.02 41.96,8.38 42.02,8.32 42.14,8.32 42.2,8.38 42.2,9.02 42.26,9.08 42.38,9.08 42.44,9.02 42.44,8.38 42.5,8.32 42.62,8.32 42.68,8.38 42.68,9.02 42.74,9.08 42.86,9.08 42.92,9.02 42.92,8.38 42.98,8.32 43.1,8.32 43.16,8.38 43.16,9.02 43.22,9.08 43.34,9.08 43.4,9.02 43.4,8.38 43.46,8.32 43.58,8.32 43.64,8.38 43.64,9.02 43.7,9.08 43.82,9.08 43.88,9.02 43.88,8.38 43.94,8.32 44.06,8.32 44.12,8.38 44.12,9.02 44.18,9.08 44.3,9.08 44.36,9.02 44.36,8.38 44.42,8.32 44.54,8.32 44.6,8.38 44.6,9.02 44.66,9.08 44.78,9.08 44.84,9.02 44.84,8.38 44.9,8.32 45.02,8.32 45.08,8.38 45.08,9.02 45.14,9.08 45.26,9.08 45.32,9.02 45.32,8.38 45.38,8.32 45.5,8.32 45.56,8.38 45.56,9.02 45.62,9.08 45.74,9.08 45.8,9.02 45.8,8.38 45.86,8.32 45.98,8.32 46.04,8.38 46.04,9.02 46.1,9.08 46.22,9.08 46.28,9.02 46.28,8.38 46.34,8.32 46.46,8.32 46.52,8.38 46.52,8.67 46.58,8.73 56.03,8.73 56.52,8.24 63.91,8.24 64.8,7.35 71.5,7.35 72.05,6.8 v1(72.05,4)
PC3: U4.J2 U5.L4 | length 33.1
  Top w0.12: U4.J2@12.3,34.45 v1(12.7,34.05) ; v1(33.2,38.85) U5.L4@33.6,38.45
  F6 w0.12: v1(12.7,34.05) 15.8,37.15 19.4,37.15 20.1,36.45 23.5,36.45 25.25,38.2 26.12,38.2 26.18,38.26 26.18,38.88 26.24,38.94 26.36,38.94 26.42,38.88 26.42,37.81 26.48,37.75 26.6,37.75 26.66,37.81 26.66,38.88 26.72,38.94 26.84,38.94 26.9,38.88 26.9,37.81 26.96,37.75 27.08,37.75 27.14,37.81 27.14,38.88 27.2,38.94 27.32,38.94 27.38,38.88 27.38,37.81 27.44,37.75 27.56,37.75 27.62,37.81 27.62,38.88 27.68,38.94 27.8,38.94 27.86,38.88 27.86,37.81 27.92,37.75 28.04,37.75 28.1,37.81 28.1,38.14 28.16,38.2 29.4,38.2 29.65,38.45 32.8,38.45 v1(33.2,38.85)
PC4: R69.2 U5.N5 | length 43.1
  Top w0.12: v1(31.6,38.05) U5.N5@32,37.65 ; R69.2@48.436,25.786 48.45,25.786 v1(48.45,27)
  F3 w0.12: v1(30.3,26.05) 30.92,26.05 30.98,26.11 30.98,26.3 31.04,26.36 31.16,26.36 31.22,26.3 31.22,25.78 31.28,25.72 31.4,25.72 31.46,25.78 31.46,26.3 31.52,26.36 31.64,26.36 31.7,26.3 31.7,25.78 31.76,25.72 31.88,25.72 31.94,25.78 31.94,26.3 32,26.36 32.12,26.36 32.18,26.3 32.18,25.78 32.24,25.72 32.36,25.72 32.42,25.78 32.42,26.3 32.48,26.36 32.6,26.36 32.66,26.3 32.66,25.78 32.72,25.72 32.84,25.72 32.9,25.78 32.9,26.3 32.96,26.36 33.08,26.36 33.14,26.3 33.14,25.78 33.2,25.72 33.32,25.72 33.38,25.78 33.38,26.3 33.44,26.36 33.56,26.36 33.62,26.3 33.62,25.78 33.68,25.72 33.8,25.72 33.86,25.78 33.86,26.3 33.92,26.36 34.04,26.36 34.1,26.3 34.1,26.11 34.16,26.05 47.75,26.05 48.45,26.75 v1(48.45,27)
  F4 w0.12: v1(30.3,26.05) 30.25,26.1 30.25,27.5 29.05,28.7 29.05,29.2 28.15,30.1 28.15,35.6 29.4,36.85 31.1,36.85 31.2,36.95 31.2,37.65 v1(31.6,38.05)
PC5: R71.2 U5.P5 | length 43.5
  Top w0.12: v1(30.8,38.05) U5.P5@31.2,37.65 ; R71.2@52.1,24.5 52.761,24.5 53,24.261 v1(53,23.5)
  F3 w0.12: v1(30.7,23.05) 34,23.05 35.2,21.85 43,21.85 43.75,22.6 51.2,22.6 52.1,23.5 v1(53,23.5)
  F4 w0.12: v1(30.7,23.05) 29.62,24.13 29.62,26.78 28.8,27.6 28.8,29.1 27.9,30 27.9,35.8 29.75,37.65 30.4,37.65 v1(30.8,38.05)
PC8: CN3.7 R14.1 U5.G14 | length 71.6
  Top w0.12: U5.G14@36.8,30.45 v1(37.2,30.05)
  Top w0.2: CN3.7@84.925,51.725 84.925,48.35 R14.1@85,48.35 85.45,48.35 85.8,48 v1(85.8,37.9)
  F5 w0.12: v1(37.2,30.05) 36.82,29.67 36.82,28.93 37.15,28.6 37.95,28.6 38.2,28.35 42.35,28.35 43.05,27.65 52.24,27.65 52.7,28.11 60.34,28.11 62.1,26.35 62.5,26.35 63.75,27.6 66.6,27.6 67.95,28.95 76.85,28.95 v1(85.8,37.9)
PC9: CN3.8 R13.1 U5.F14 | length 80.3
  Top w0.12: U5.F14@37.6,30.45 v1(38,30.05)
  Top w0.2: R13.1@83.75,48.35 v1@83.75,49.2 ; v1(83.75,49.3) v1@83.75,49.2 ; CN3.8@83.825,51.55 83.825,49.275 83.8,49.25 v1@83.75,49.2
  F5 w0.12: v1(38,30.05) 38.4,29.65 38.4,29.1 38.65,28.85 42.32,28.85 42.88,29.41 46.06,29.41 46.6,28.87 51.61,28.87 52.04,29.3 76.5,29.3 92.75,45.55 92.75,49.8 84.25,49.8 v1(83.75,49.3)
PC10: CN3.1 R17.1 U5.B14 | length 65.5
  Top w0.12: U5.B14@40.8,30.45 v1(41.2,30.05)
  Top w0.2: CN3.1@91.525,51.425 91.525,49.475 v1(91.7,49.3) 91.75,49.25 R17.1@91.75,48.35
  F5 w0.12: v1(41.2,30.05) 41.6,29.65 46.21,29.65 46.71,29.15 49.44,29.15 49.95,29.66 76.41,29.66 91.15,44.4 91.15,48.75 v1(91.7,49.3)
PC11: CN3.2 R16.1 U5.B13 | length 65.2
  Top w0.12: U5.B13@40.8,31.25 v1(41.2,30.85)
  Top w0.2: CN3.2@90.425,51.725 90.425,49.475 v1(90.5,49.4) R16.1@90.5,48.35
  F5 w0.12: v1(41.2,30.85) 41.6,30.45 46.03,30.45 47.09,29.39 49.26,29.39 49.77,29.9 76.2,29.9 89.95,43.65 89.95,48.85 v1(90.5,49.4)
PC12: CN3.5 U5.A12 | length 60.7
  Top w0.12: U5.A12@41.6,32.05 v1(42,31.65)
  Top w0.2: CN3.5@87.125,51.45 87.125,45.1 v1(87.15,45.1)
  F5 w0.12: v1(42,31.65) 42.25,31.65 42.95,30.95 48.5,30.95 49.05,30.4 75.85,30.4 87.15,41.7 v1(87.15,45.1)
PC13: R11.1 R12.1 U5.D1 | length 48
  Top w0.12: U5.D1@39.2,40.85 v1(39.2,41.35) ; R11.1@81.25,47.15 81.76,47.15 81.85,47.24 81.85,48.21 81.99,48.35 R12.1@82.5,48.35
  Top w0.2: v1(81.2,46.25) 81.25,46.25 R11.1@81.25,47.15
  F4 w0.12: v1(39.2,41.35) 42.25,44.4 50.7,44.4 51.59,45.29 66.76,45.29 67.97,46.5 80.95,46.5 v1(81.2,46.25)
PC14: R32.2 U5.E1 | length 3.1
  Top w0.12: U5.E1@38.4,40.85 38.4,41.052 39.248,41.9 39.6,41.9 40.5,42.8 R32.2@40.5,42.9
PC15: R31.2 U5.F1 | length 2.8
  Top w0.12: U5.F1@37.6,40.85 37.7,40.85 39.25,42.4 R31.2@39.25,42.9
PD2: CN3.3 R15.1 U5.D12 | length 66.1
  Top w0.12: U5.D12@39.2,32.05 v1(39.6,31.65) ; v1(89.25,49.4) v1@89.25,49.45
  Top w0.2: R15.1@89.25,48.35 v1(89.25,49.4) ; v1@89.25,49.45 89.325,49.525 CN3.3@89.325,51.725
  F5 w0.12: v1(39.6,31.65) 40,31.25 42.25,31.25 42.8,30.7 46.41,30.7 47.45,29.66 48.99,29.66 49.48,30.15 76,30.15 88.4,42.55 88.4,48.55 v1(89.25,49.4)
PD4: R119.2 U5.D11 | length 75.5
  Top w0.12: U5.D11@39.2,32.85 v1(39.6,32.45) ; R119.2@91.35,-1 92.25,-1 92.95,-0.3 92.95,5.95 v1(93.45,6.45)
  F3 w0.12: v1(39.6,32.45) 40,32.05 42.75,32.05 43.25,31.55 48.1,31.55 49.55,33 53.451,33 55.591,30.86 67.74,30.86 92.45,6.15 93.15,6.15 v1(93.45,6.45)
PD5: R117.1 U5.C10 | length 71.4
  Top w0.12: U5.C10@40,33.65 v1(40.4,33.25) ; R117.1@91.35,0.25 91.35,0.2 92.2,0.2 92.6,0.6 v1(92.6,6.75)
  F3 w0.12: v1(40.4,33.25) 53.54,33.25 55.69,31.1 67.95,31.1 92.3,6.75 v1(92.6,6.75)
PD6: U5.B11 U11.G3 | length 36.4
  Top w0.12: U11.G3@17.75,16.25 v2(18,16.5) ; U5.B11@40.8,32.85 v1(41.2,32.45)
  F6 w0.12: v2(18,16.5) 17.3,16.5 17.1,16.7 17.1,19.15 18.95,21 21.5,21 22.7,22.2 28.55,22.2 32.8,26.45 39.35,26.45 40.8,27.9 40.8,32.05 v1(41.2,32.45)
PD7: R8.2 R22.2 U2.4 U5.A11 | length 35.7
  Top w0.12: U5.A11@41.6,32.85 v1(42,32.45) 42.4,32.45 43.35,31.5 51,31.5 51.4,31.9 51.4,36.95 52.25,37.8 52.25,40.5 55.85,44.1 R22.2@55.85,45.75 ; R8.2@51,51.35 52.4,51.35 53.75,50 54.5,50 55,49.5 55,48.75 55.25,48.5 55.7,48.5 55.95,48.25 U2.4@55.95,47.85 55.95,45.85 R22.2@55.85,45.75 ; R22.2@55.85,46 R22.2@55.85,45.75
PD11: U3.5 U5.N10 | length 53.1
  Top w0.12: v1(31.6,33.25) U5.N10@32,33.65 ; v1(68.05,41.25) 68.221,41.079 U3.5@69.272,41.079
  F4 w0.12: v1(31.6,33.25) 32,33.65 32,34.35 32.1,34.45 37.4,34.45 38.15,35.2 41.65,35.2 43.15,36.7 44.05,36.7 45.3,37.95 51.25,37.95 55,41.7 55.69,41.7 55.75,41.76 55.75,42.36 55.81,42.42 55.93,42.42 55.99,42.36 55.99,41.33 56.05,41.27 56.17,41.27 56.23,41.33 56.23,42.36 56.29,42.42 56.41,42.42 56.47,42.36 56.47,41.33 56.53,41.27 56.65,41.27 56.71,41.33 56.71,42.36 56.77,42.42 56.89,42.42 56.95,42.36 56.95,41.33 57.01,41.27 57.13,41.27 57.19,41.33 57.19,42.36 57.25,42.42 57.37,42.42 57.43,42.36 57.43,41.33 57.49,41.27 57.61,41.27 57.67,41.33 57.67,42.36 57.73,42.42 57.85,42.42 57.91,42.36 57.91,41.33 57.97,41.27 58.09,41.27 58.15,41.33 58.15,41.64 58.21,41.7 67.6,41.7 v1(68.05,41.25)
PD12: U3.2 U5.M10 | length 53.1
  Top w0.12: v1(32.4,33.25) U5.M10@32.8,33.65 ; U3.2@77.122,38.539 78.15,38.539 v1(78.15,38.55)
  F4 w0.12: v1(32.4,33.25) 32.8,33.65 42.3,33.65 43.1,34.45 44.25,34.45 45.1,35.3 45.1,36.9 45.9,37.7 51.5,37.7 53.81,40.01 59.49,40.01 60.41,40.93 66.47,40.93 68,39.4 69.9,39.4 71.5,37.8 77.4,37.8 v1(78.15,38.55)
PD13: U3.7 U5.M11 | length 53
  Top w0.12: v1(32.4,32.45) U5.M11@32.8,32.85 ; v1(68.15,38.55) 68.15,38.539 U3.7@69.272,38.539
  F4 w0.12: v1(32.4,32.45) 32.8,32.85 43.65,32.85 46.3,35.5 50.75,35.5 51.7,36.45 51.7,37.3 53.96,39.56 61.99,39.56 62.05,39.5 62.05,39 62.11,38.94 62.23,38.94 62.29,39 62.29,40.13 62.35,40.19 62.47,40.19 62.53,40.13 62.53,39 62.59,38.94 62.71,38.94 62.77,39 62.77,40.13 62.83,40.19 62.95,40.19 63.01,40.13 63.01,39 63.07,38.94 63.19,38.94 63.25,39 63.25,40.13 63.31,40.19 63.43,40.19 63.49,40.13 63.49,39 63.55,38.94 63.67,38.94 63.73,39 63.73,40.13 63.79,40.19 63.91,40.19 63.97,40.13 63.97,39 64.03,38.94 64.15,38.94 64.21,39 64.21,40.13 64.27,40.19 64.39,40.19 64.45,40.13 64.45,39.62 64.51,39.56 66.35,39.56 67.36,38.55 v1(68.15,38.55)
PE0: U4.K9 U5.A6 | length 27.7
  Top w0.12: U4.K9@17.9,33.65 22.4,33.65 v1(22.9,33.15) ; U5.A6@41.6,36.85 v1(42,36.45)
  F3 w0.12: v1(22.9,33.15) 23.75,32.3 29.9,32.3 30.45,32.85 34.25,32.85 34.4,33 34.4,33.45 34.9,33.95 35.7,33.95 36.95,35.2 38.15,35.2 38.4,35.45 38.4,35.9 38.55,36.05 41.95,36.05 42,36.1 v1(42,36.45)
PE1: U4.K1 U5.A5 | length 33.8
  Top w0.12: U4.K1@11.5,33.65 v1(11.9,33.25) ; U5.A5@41.6,37.65 v1(42,38.05)
  F3 w0.12: v1(11.9,33.25) 12.3,32.85 17.8,32.85 18.55,33.6 21.8,33.6 22.46,34.26 23.67,34.26 24,33.93 25.97,33.93 26.48,34.44 28.09,34.44 28.53,34.88 31.81,34.88 32.18,35.25 35.85,35.25 38.25,37.65 41.6,37.65 v1(42,38.05)
PE2: U3.3 U5.A3 | length 53.4
  Top w0.12: U5.A3@41.6,39.25 v1(43.8,39.25) ; U3.3@77.122,39.809 78.15,39.809 v1(78.15,39.85)
  F5 w0.12: v1(43.8,39.25) 47.62,39.25 47.87,39 49.25,39 49.5,39.25 50.05,39.25 50.3,39.5 57.45,39.5 58,38.95 66.8,38.95 67.25,39.4 70,39.4 71.2,40.6 71.59,40.6 71.65,40.54 71.65,39.16 71.71,39.1 71.84,39.1 71.9,39.16 71.9,40.54 71.96,40.6 72.09,40.6 72.15,40.54 72.15,39.16 72.21,39.1 72.34,39.1 72.4,39.16 72.4,40.54 72.46,40.6 72.59,40.6 72.65,40.54 72.65,39.91 72.71,39.85 73.69,39.85 73.75,39.91 73.75,40.54 73.81,40.6 73.94,40.6 74,40.54 74,39.16 74.06,39.1 74.19,39.1 74.25,39.16 74.25,40.54 74.31,40.6 74.44,40.6 74.5,40.54 74.5,39.16 74.56,39.1 74.69,39.1 74.75,39.16 74.75,40.54 74.81,40.6 74.94,40.6 75,40.54 75,39.16 75.06,39.1 75.6,39.1 76.35,39.85 v1(78.15,39.85)
PE3: R130.2 U5.A2 | length 53.7
  Top w0.12: U5.A2@41.6,40.05 42,40.45 v1(42.1,40.45) ; v1(58.05,-3.225) 58.075,-3.25 R130.2@59.15,-3.25
  F6 w0.12: v1(42.1,40.45) 44.85,40.45 45.45,39.85 45.45,33.36 45.98,32.83 45.98,29.871 48.02,27.831 48.02,26.55 48.65,25.92 48.65,22.35 51,20 51,14.8 54.1,11.7 54.1,0.7 58.025,-3.225 v1(58.05,-3.225)
PF11: U4.J9 U5.P8 | length 33
  Top w0.12: U4.J9@17.9,34.45 18.7,34.45 19.1,34.85 v1(19.35,34.85) ; v1(30.8,35.65) U5.P8@31.2,35.25
  Bottom w0.12: v1(19.35,34.85) 21.84,34.85 21.9,34.79 21.9,34.75 21.96,34.69 22.08,34.69 22.14,34.75 22.14,35.21 22.2,35.27 22.32,35.27 22.38,35.21 22.38,34.75 22.44,34.69 22.56,34.69 22.62,34.75 22.62,35.21 22.68,35.27 22.8,35.27 22.86,35.21 22.86,34.91 22.92,34.85 23.35,34.85 23.477,34.977 23.562,34.977 23.733,34.807 23.817,34.807 23.902,34.892 23.902,34.977 23.428,35.45 23.428,35.535 23.513,35.62 23.598,35.62 24.072,35.146 24.157,35.146 24.242,35.231 24.242,35.316 23.768,35.79 23.768,35.875 23.853,35.959 23.938,35.959 24.411,35.486 24.496,35.486 24.581,35.571 24.581,35.655 24.107,36.129 24.107,36.214 24.192,36.299 24.277,36.299 24.496,36.08 24.58,36.08 24.85,36.35 26.23,36.35 26.29,36.29 26.29,35.69 26.35,35.63 26.47,35.63 26.53,35.69 26.53,37.01 26.59,37.07 26.71,37.07 26.77,37.01 26.77,35.69 26.83,35.63 26.95,35.63 27.01,35.69 27.01,37.01 27.07,37.07 27.19,37.07 27.25,37.01 27.25,35.69 27.31,35.63 27.43,35.63 27.49,35.69 27.49,37.01 27.55,37.07 27.67,37.07 27.73,37.01 27.73,35.69 27.79,35.63 27.91,35.63 27.97,35.69 27.97,37.01 28.03,37.07 28.15,37.07 28.21,37.01 28.21,35.69 28.27,35.63 28.39,35.63 28.45,35.69 28.45,36.29 28.51,36.35 29.1,36.35 29.8,35.65 v1(30.8,35.65)
PG2: R68.2 U5.M13 U9.10 | length 22.4
  Top w0.12: v1(32.4,30.85) U5.M13@32.8,31.25 ; U9.10@46.322,22.439 46.322,23.2 v1(46.45,23.2) 46.45,24.586 R68.2@46.436,24.586
  F4 w0.12: v1(32.4,30.85) 32.8,30.45 32.8,28.225 35.075,25.95 45.394,25.95 46.45,24.894 v1(46.45,23.2)
PG3: CN2.4 U5.M12 | length 42.8
  Top w0.12: v1(32.4,31.65) U5.M12@32.8,32.05
  Top w0.3: CN2.4@16.5,59.77 19.9,59.77 23.55,56.12 23.55,52.95 24.9,51.6 28.4,51.6 v1(30.3,49.7)
  F5 w0.12: v1(30.3,49.7) 29.3,48.7 29.3,43.15 28.2,42.05 28.2,32.84 28.99,32.05 32,32.05 v1(32.4,31.65)
PG4: U4.J7 U5.N12 | length 22.2
  Top w0.12: v1(15.5,30.85) 15.3,30.85 15.3,33.45 U4.J7@16.3,34.45 ; v1(31.6,31.65) U5.N12@32,32.05
  Bottom w0.12: v1(15.5,30.85) 15.5,30.75 15.8,30.45 17.93,30.45 18.69,29.69 28.29,29.69 29.85,31.25 31.2,31.25 v1(31.6,31.65)
PG5: U4.H8 U5.N11 | length 18.5
  Top w0.12: U4.H8@17.1,35.25 v1(17.5,34.85) ; v1(31.6,32.45) U5.N11@32,32.85
  Bottom w0.12: v1(17.5,34.85) 18.5,34.85 18.9,34.45 23.8,34.45 24.65,35.3 29,35.3 29.45,34.85 31.4,34.85 32,34.25 32,32.85 v1(31.6,32.45)
PG8: U4.J1 U5.H14 | length 33.2
  Top w0.12: U4.J1@11.5,34.45 v1(11.9,34.05) ; v1(35.6,30.05) U5.H14@36,30.45
  F6 w0.12: v1(11.9,34.05) 11.71,34.05 10.9,33.24 10.9,29.3 13,27.2 17.11,27.2 17.55,27.64 24.44,27.64 26.45,29.65 35.2,29.65 v1(35.6,30.05)
PG9: P1.19 U5.D9 | length 74.7
  Top w0.12: U5.D9@39.2,34.45 v1(39.6,34.05) ; v1(60.25,61.15) P1.19@60.25,62.175
  F3 w0.12: v1(39.6,34.05) 40.15,34.6 42.05,34.6 42.25,34.4 46.6,34.4 48.15,35.95 51.3,35.95 52.07,36.72 52.07,39.39 53.74,41.06 54.08,41.06 54.38,40.76 54.77,40.76 55.05,41.04 55.05,42.17 55.93,43.05 56.627,43.05 57.655,42.022 57.74,42.022 57.825,42.107 57.825,42.192 56.892,43.125 56.892,43.21 56.976,43.295 57.061,43.295 57.995,42.361 58.08,42.361 58.164,42.446 58.164,42.531 57.231,43.464 57.231,43.549 57.316,43.634 57.401,43.634 58.334,42.701 58.419,42.701 58.504,42.786 58.504,42.87 57.57,43.804 57.57,43.889 57.655,43.974 57.74,43.974 58.164,43.549 58.249,43.549 61.262,46.562 61.346,46.562 61.771,46.137 61.856,46.137 61.94,46.222 61.94,46.307 61.007,47.24 61.007,47.325 61.092,47.41 61.177,47.41 62.11,46.477 62.195,46.477 62.28,46.562 62.28,46.646 61.346,47.58 61.346,47.665 61.431,47.75 61.516,47.75 62.45,46.816 62.534,46.816 62.619,46.901 62.619,46.986 61.686,47.919 61.686,48.004 61.771,48.089 61.856,48.089 62.28,47.665 62.365,47.665 63.68,48.98 63.68,53.57 63.62,53.63 63.02,53.63 62.96,53.69 62.96,53.81 63.02,53.87 64.34,53.87 64.4,53.93 64.4,54.05 64.34,54.11 63.02,54.11 62.96,54.17 62.96,54.29 63.02,54.35 64.34,54.35 64.4,54.41 64.4,54.53 64.34,54.59 63.02,54.59 62.96,54.65 62.96,54.77 63.02,54.83 64.34,54.83 64.4,54.89 64.4,55.01 64.34,55.07 63.74,55.07 63.68,55.13 63.68,60.58 63.11,61.15 v1(60.25,61.15)
PG10: U5.C8 U11.F2 | length 39.9
  Top w0.12: v2(18,17) U11.F2@18.25,16.75 ; U5.C8@40,35.25 v1(40.4,35.65)
  F6 w0.12: v2(18,17) 18,17.05 18.3,17.35 18.3,18.7 19.95,20.35 21.65,20.35 23.02,21.72 34.82,21.72 37.621,24.521 37.621,24.524 38.648,25.55 40.3,25.55 42.55,27.8 42.55,34.15 41.45,35.25 40.8,35.25 v1(40.4,35.65)
PG11: U5.B8 U9.16 | length 43
  Top w0.12: U5.B8@40.8,35.25 41.2,35.65 43.45,35.65 v1(43.45,35.55) ; v1(42.975,20.45) 43,20.45 43.16,20.289 U9.16@44.672,20.289
  F6 w0.12: v1(42.975,20.45) 42.932,20.493 42.932,20.67 42.29,21.312 42.29,21.73 42.35,21.79 42.88,21.79 42.94,21.85 42.94,21.97 42.88,22.03 41.44,22.03 41.38,22.09 41.38,22.21 41.44,22.27 42.88,22.27 42.94,22.33 42.94,22.45 42.88,22.51 41.44,22.51 41.38,22.57 41.38,22.69 41.44,22.75 42.88,22.75 42.94,22.81 42.94,22.93 42.88,22.99 41.44,22.99 41.38,23.05 41.38,23.17 41.44,23.23 42.23,23.23 42.29,23.29 42.29,23.72 42.587,24.017 42.672,24.017 43.058,23.631 43.143,23.631 43.228,23.715 43.228,23.8 42.551,24.477 42.551,24.562 42.636,24.647 42.721,24.647 43.436,23.932 43.52,23.932 43.605,24.017 43.605,24.102 42.782,24.925 42.782,25.01 42.867,25.094 42.952,25.094 43.775,24.272 43.86,24.272 43.945,24.356 43.945,24.441 42.45,25.936 42.45,26.3 43.38,27.23 43.38,27.47 43.44,27.53 44.55,27.53 44.61,27.59 44.61,27.71 44.55,27.77 44.06,27.77 44,27.83 44,28.01 43.94,28.07 43.44,28.07 43.38,28.13 43.38,28.25 43.44,28.31 44.25,28.31 44.31,28.37 44.31,28.49 44.25,28.55 43.44,28.55 43.38,28.61 43.38,28.73 43.44,28.79 43.94,28.79 44,28.85 44,29.33 44.28,29.61 44.28,30.21 43.61,30.88 43.61,31.372 43.61,31.446 43.498,31.559 43.492,31.559 43.38,31.671 43.38,31.82 43.492,31.933 43.61,31.933 43.68,31.933 43.793,32.045 43.793,32.194 43.68,32.307 43.61,32.377 43.61,32.64 44.28,33.31 44.28,33.425 44.28,33.599 44.267,33.612 44.155,33.724 44.155,33.874 44.267,33.986 44.28,33.999 44.28,34.248 44.168,34.36 43.962,34.36 43.849,34.472 43.849,34.622 43.962,34.734 44.168,34.734 44.28,34.846 44.28,35.025 44.28,35.25 43.98,35.55 v1(43.45,35.55)
PG13: U5.B3 U9.17 | length 43.2
  Top w0.12: U5.B3@40.8,39.25 41.2,39.65 v1(42.6,39.65) ; v1(43.75,19.65) 43.889,19.789 U9.17@44.672,19.789
  F6 w0.12: v1(42.6,39.65) 42.8,39.65 44.87,37.58 44.87,33.261 45.45,32.681 45.45,28.95 45.51,28.89 46.16,28.89 46.22,28.83 46.22,28.71 46.16,28.65 45.37,28.65 45.31,28.59 45.31,28.47 45.37,28.41 46.69,28.41 46.75,28.35 46.75,28.23 46.69,28.17 45.51,28.17 45.45,28.11 45.45,27.77 46.69,27.77 46.75,27.71 46.75,27.59 46.69,27.53 45.81,27.53 45.75,27.47 45.75,27.35 45.81,27.29 45.97,27.29 46.03,27.23 46.03,26.08 45.97,26.02 45.63,26.02 45.57,25.96 45.57,25.84 45.63,25.78 46.73,25.78 46.79,25.72 46.79,25.6 46.73,25.54 45.63,25.54 45.57,25.48 45.57,25.36 45.63,25.3 46.73,25.3 46.79,25.24 46.79,25.12 46.73,25.06 45.63,25.06 45.57,25 45.57,24.88 45.63,24.82 46.73,24.82 46.79,24.76 46.79,24.64 46.73,24.58 45.63,24.58 45.57,24.52 45.57,24.4 45.63,24.34 46.73,24.34 46.79,24.28 46.79,24.16 46.73,24.1 45.63,24.1 45.57,24.04 45.57,23.92 45.63,23.86 46.73,23.86 46.79,23.8 46.79,23.68 46.73,23.62 46.09,23.62 46.03,23.56 46.03,23.38 44.4,21.75 44.4,20.3 v1(43.75,19.65)
PG14: U5.A4 U9.18 | length 43.1
  Top w0.12: U5.A4@41.6,38.45 v1(45.05,38.45) ; v1(43.8,18.95) 43.805,18.945 44.15,19.289 U9.18@44.672,19.289
  F6 w0.12: v1(43.8,18.95) 43.85,18.95 44.9,20 44.9,20.36 44.84,20.42 44.7,20.42 44.64,20.48 44.64,20.6 44.7,20.66 45.09,20.66 45.15,20.72 45.15,20.84 45.09,20.9 44.7,20.9 44.64,20.96 44.64,21.08 44.7,21.14 45.09,21.14 45.15,21.2 45.15,21.32 45.09,21.38 44.96,21.38 44.9,21.44 44.9,21.62 45.46,22.18 45.76,22.18 45.82,22.24 45.82,22.6 45.88,22.66 46,22.66 46.06,22.6 46.06,21.85 46.12,21.79 46.24,21.79 46.3,21.85 46.3,22.6 46.36,22.66 46.48,22.66 46.54,22.6 46.54,21.94 46.6,21.88 46.72,21.88 46.78,21.94 46.78,22.6 46.84,22.66 46.96,22.66 47.02,22.6 47.02,21.78 47.08,21.72 47.2,21.72 47.26,21.78 47.26,22.6 47.32,22.66 47.44,22.66 47.5,22.6 47.5,22.24 47.56,22.18 47.74,22.18 47.96,22.4 47.96,23.54 47.9,23.6 47.5,23.6 47.44,23.66 47.44,23.78 47.5,23.84 48.35,23.84 48.41,23.9 48.41,24.02 48.35,24.08 47.3,24.08 47.24,24.14 47.24,24.26 47.3,24.32 48.35,24.32 48.41,24.38 48.41,24.5 48.35,24.56 47.3,24.56 47.24,24.62 47.24,24.74 47.3,24.8 48.35,24.8 48.41,24.86 48.41,24.98 48.35,25.04 47.3,25.04 47.24,25.1 47.24,25.22 47.3,25.28 47.9,25.28 47.96,25.34 47.96,25.57 47.01,26.52 47.01,28.44 45.74,29.71 45.74,32.731 45.14,33.331 45.14,38.31 45,38.45 v1(45.05,38.45)
PG15: U4.K7 U5.B7 | length 33.1
  Top w0.12: v1(15.85,31.7) 15.85,33.2 U4.K7@16.3,33.65 ; U5.B7@40.8,36.05 v1(41.2,36.45)
  F3 w0.12: v1(15.85,31.7) 16.2,32.05 19.49,32.05 19.87,32.43 20.36,32.43 20.42,32.37 20.42,32.12 20.48,32.06 20.6,32.06 20.66,32.12 20.66,32.58 20.72,32.64 20.84,32.64 20.9,32.58 20.9,32.12 20.96,32.06 21.08,32.06 21.14,32.12 21.14,32.37 21.2,32.43 21.38,32.43 22.6,33.65 23.29,33.65 24.4,32.54 29.09,32.54 29.36,32.81 29.36,33.1 29.51,33.25 30.1,33.25 30.5,33.65 34.25,33.65 35.05,34.45 35.45,34.45 37.85,36.85 40.8,36.85 v1(41.2,36.45)
PH0: R30.2 U5.G1 | length 2.5
  Top w0.12: U5.G1@36.8,40.85 38,42.05 R30.2@38,42.9
PH1: U5.H1
PH2: R29.1 U5.K4 | length 5.1
  Top w0.12: v1(33,42.05) R29.1@33,42.9 ; v1(34,38.85) 34,38.8 34.025,38.825 U5.K4@34.4,38.45
  F5 w0.12: v1(33,42.05) 33,42 33.6,41.4 33.6,39.25 v1(34,38.85)
PH3: U4.J8 U5.J4 | length 33.1
  Top w0.12: v1(16.7,34.85) U4.J8@17.1,34.45 ; v1(34.8,38.85) U5.J4@35.2,38.45
  Bottom w0.12: v1(16.7,34.85) 16.7,34.95 17,35.25 17.8,35.25 18.2,35.65 18.8,35.65 19.05,35.4 20.08,35.4 20.14,35.34 20.14,35.19 20.2,35.13 20.32,35.13 20.38,35.19 20.38,36.07 20.44,36.13 20.56,36.13 20.62,36.07 20.62,35.19 20.68,35.13 20.8,35.13 20.86,35.19 20.86,36.07 20.92,36.13 21.04,36.13 21.1,36.07 21.1,35.46 21.16,35.4 21.4,35.4 22.25,36.25 23.52,36.25 24.92,37.65 26.52,37.65 26.58,37.59 26.58,37.43 26.64,37.37 26.76,37.37 26.82,37.43 26.82,38.63 26.88,38.69 27,38.69 27.06,38.63 27.06,37.43 27.12,37.37 27.24,37.37 27.3,37.43 27.3,38.63 27.36,38.69 27.48,38.69 27.54,38.63 27.54,37.43 27.6,37.37 27.72,37.37 27.78,37.43 27.78,38.63 27.84,38.69 27.96,38.69 28.02,38.63 28.02,37.43 28.08,37.37 28.2,37.37 28.26,37.43 28.26,37.59 28.32,37.65 34.2,37.65 34.4,37.85 34.4,38.45 v1(34.8,38.85)
PH4: U5.H4 U15.2 | length 89.1
  Top w0.12: v1(35.6,38.85) U5.H4@36,38.45 ; v1(70.2,7.8) 70.2,5.05 U15.2@70.25,5.05
  F4 w0.12: v1(35.6,38.85) 35.2,38.45 35.2,35.5 34.95,35.25 29.85,35.25 29.35,34.75 29.35,32.65 28.65,31.95 28.65,30.9 29.6,29.95 29.6,29.1 31.6,27.1 31.6,18.15 40.26,9.49 47.99,9.49 48.05,9.55 48.05,9.78 48.11,9.84 48.23,9.84 48.29,9.78 48.29,9.2 48.35,9.14 48.47,9.14 48.53,9.2 48.53,9.78 48.59,9.84 48.71,9.84 48.77,9.78 48.77,9.2 48.83,9.14 48.95,9.14 49.01,9.2 49.01,9.78 49.07,9.84 49.19,9.84 49.25,9.78 49.25,9.2 49.31,9.14 49.43,9.14 49.49,9.2 49.49,9.78 49.55,9.84 49.67,9.84 49.73,9.78 49.73,9.2 49.79,9.14 49.91,9.14 49.97,9.2 49.97,9.78 50.03,9.84 50.15,9.84 50.21,9.78 50.21,9.2 50.27,9.14 50.39,9.14 50.45,9.2 50.45,9.78 50.51,9.84 50.63,9.84 50.69,9.78 50.69,9.2 50.75,9.14 50.87,9.14 50.93,9.2 50.93,9.78 50.99,9.84 51.11,9.84 51.17,9.78 51.17,9.2 51.23,9.14 51.35,9.14 51.41,9.2 51.41,9.78 51.47,9.84 51.59,9.84 51.65,9.78 51.65,9.2 51.71,9.14 51.83,9.14 51.89,9.2 51.89,9.78 51.95,9.84 52.07,9.84 52.13,9.78 52.13,9.2 52.19,9.14 52.31,9.14 52.37,9.2 52.37,9.78 52.43,9.84 52.55,9.84 52.61,9.78 52.61,9.2 52.67,9.14 52.79,9.14 52.85,9.2 52.85,9.78 52.91,9.84 53.03,9.84 53.09,9.78 53.09,9.2 53.15,9.14 53.27,9.14 53.33,9.2 53.33,9.78 53.39,9.84 53.51,9.84 53.57,9.78 53.57,9.2 53.63,9.14 53.75,9.14 53.81,9.2 53.81,9.43 53.87,9.49 56.58,9.49 57.44,8.63 64.77,8.63 65.6,7.8 v1(70.2,7.8)
PH5: U4.K8 U5.J3 | length 33
  Top w0.12: v1(16.7,34.05) U4.K8@17.1,33.65 ; v1(34.8,39.65) U5.J3@35.2,39.25
  Bottom w0.12: v1(16.7,34.05) 16.3,34.45 16.3,35.9 16.95,36.55 23.05,36.55 24.478,37.978 24.478,38.063 24.131,38.41 24.131,38.495 24.215,38.58 24.3,38.58 24.941,37.939 25.026,37.939 25.111,38.024 25.111,38.109 24.47,38.75 24.47,38.835 24.555,38.919 24.64,38.919 25.281,38.279 25.365,38.279 25.45,38.363 25.45,38.448 24.809,39.089 24.809,39.174 24.894,39.259 24.979,39.259 25.62,38.618 25.705,38.618 25.79,38.703 25.79,38.788 25.149,39.429 25.149,39.513 25.234,39.598 25.318,39.598 25.959,38.957 26.044,38.957 26.129,39.042 26.129,39.127 25.488,39.768 25.488,39.853 25.573,39.938 25.658,39.938 26.299,39.297 26.384,39.297 26.469,39.382 26.469,39.467 26.26,39.675 26.26,39.76 26.55,40.05 34.4,40.05 v1(34.8,39.65)
PH7: R62.1 R76.1 U5.N13 U19.39 | length 46.6
  Top w0.12: R76.1@13.3,21.05 13.31,21.05 13.31,21.71 14.8,23.2 17.95,23.2 19.85,25.1 27,25.1 28.1,26.2 R62.1@28.1,26.75 29,26.75 v1(29,26.7) ; v1(31.6,30.85) U5.N13@32,31.25
  Bottom w0.12: v1(31.6,30.85) 30.75,30 29.9,30 28.85,28.95 28.85,26.85 v1(29,26.7) 29,25.5 30.6,23.9 45.15,23.9 45.45,23.6 46.9,23.6 47.05,23.75 U19.39@47.05,24.989
PH8: R61.1 R83.1 U5.P14 U19.40 | length 48
  Top w0.12: R83.1@13.3,18.6 11.96,18.6 11.25,19.31 11.25,22.7 12.65,24.1 17.44,24.1 19.34,26 22.7,26 24.1,27.4 27.8,27.4 28.1,27.7 R61.1@28.1,28 v1@29.25,28 ; v1(29.25,27.95) v1@29.25,28 ; U5.P14@31.2,30.45 30.8,30.05 30.05,30.05 29.25,29.25 v1@29.25,28
  Bottom w0.12: v1(29.25,27.95) 29.25,27.9 31.025,26.125 44.525,26.125 45.506,25.144 U19.40@46.2,25.144
PH13: P1.25 U5.E12 | length 42.6
  Top w0.12: U5.E12@38.4,32.05 v1(38.8,31.65) ; v1(57.25,61.05) P1.25@57.25,62.175
  F3 w0.12: v1(38.8,31.65) 39.2,32.05 39.2,34.5 39.6,34.9 42.1,34.9 42.35,34.65 44.35,34.65 46.15,36.45 47.45,36.45 49.9,38.9 49.9,39.3 57.25,46.65 v1(57.25,61.05)
PH15: TP3.1 U5.D13 | length 63.8
  Top w0.12: U5.D13@39.2,31.25 v1(39.6,30.85)
  F6 w0.12: TP3.1@0,0 0.55,0.55 9.3,0.55 14.35,5.6 14.35,21.85 18.08,25.58 23.08,25.58 24.7,27.2 38.15,27.2 39.2,28.25 39.2,30.45 v1(39.6,30.85)
PI4: U5.C3 U11.D3 | length 46.7
  Top w0.12: U11.D3@19.25,16.25 v2(19.5,16.5) ; U5.C3@40,39.25 40.325,39.575 40.35,39.55 v1(40.35,39.65)
  F6 w0.12: v2(19.5,16.5) 19.55,16.55 20.7,16.55 21.6,17.45 21.6,19.2 22.5,20.1 26.8,20.1 27.5,19.4 30.6,19.4 31.45,20.25 38,20.25 42,24.25 42,26.2 43.14,27.34 43.14,34.44 42.79,34.79 42.79,36.35 43.35,36.91 43.35,38.2 42.65,38.9 41.8,38.9 41.05,39.65 v1(40.35,39.65)
PI5: U5.D3 U11.G1 | length 43.7
  Top w0.12: U11.G1@17.75,17.25 v1(17.75,17.7) ; U5.D3@39.2,39.25 v1(39.6,39.65)
  F6 w0.12: v1(17.75,17.7) 17.75,19 19.5,20.75 21.6,20.75 22.81,21.96 28.75,21.96 32.79,26 40.25,26 41.6,27.35 41.6,34.45 41.2,34.85 40.5,34.85 40,35.35 40,38.25 39.81,38.44 39.51,38.44 39.2,38.75 39.2,39.25 v1(39.6,39.65)
PI6: U5.D6 U11.E4 | length 45.1
  Top w0.12: U11.E4@18.75,15.75 v2(19,16) ; U5.D6@39.2,36.85 v1(39.6,37.25)
  F6 w0.12: v2(19,16) 17.3,16 16.73,16.57 16.73,23.39 17.76,24.42 27.72,24.42 30.15,26.85 38.663,26.85 40,28.187 40,34.6 39.2,35.4 39.2,36.85 v1(39.6,37.25)
PI7: U5.D4 U11.E3 | length 43.8
  Top w0.12: U11.E3@18.75,16.25 v2(19,16.5) ; U5.D4@39.2,38.45 39.65,38.9 v1(39.65,38.85)
  F6 w0.12: v2(19,16.5) 19,18.05 19.5,18.55 20.3,18.55 22.15,20.4 28.55,20.4 28.9,20.75 34.55,20.75 35.5,21.7 37.35,21.7 40.45,24.8 40.45,25.05 42.85,27.45 42.85,34.3 42.55,34.6 42.55,36.5 41.4,37.65 41,37.65 40.8,37.85 40.8,38.35 40.7,38.45 40.25,38.45 39.85,38.85 v1(39.65,38.85)
PI8: R33.1 U5.C2 | length 4.9
  Top w0.12: U5.C2@40,40.05 40.4,40.45 40.4,41.15 40.9,41.65 42.3,41.65 43,42.35 R33.1@43,42.9
PI9: U5.E4 U19.33 | length 58.3
  Top w0.12: U5.E4@38.4,38.45 v1(38.8,38.85)
  Bottom w0.12: v1(38.8,38.85) 38.85,38.85 38.8,38.8 39.2,38.4 39.2,37.05 39.4,36.85 42,36.85 43.1,37.95 44.05,37.95 45.3,36.7 45.48,36.7 45.54,36.76 45.54,37.36 45.6,37.42 45.72,37.42 45.78,37.36 45.78,36.22 45.84,36.16 45.96,36.16 46.02,36.22 46.02,37.36 46.08,37.42 46.2,37.42 46.26,37.36 46.26,36.44 46.32,36.38 46.44,36.38 46.5,36.44 46.5,36.81 46.56,36.87 46.68,36.87 46.74,36.81 46.74,36.44 46.8,36.38 46.92,36.38 46.98,36.44 46.98,36.83 47.04,36.89 47.16,36.89 47.22,36.83 47.22,36.44 47.28,36.38 47.4,36.38 47.46,36.44 47.46,37.36 47.52,37.42 47.64,37.42 47.7,37.36 47.7,36.76 47.76,36.7 48.14,36.7 49.05,35.79 49.05,35.52 48.99,35.46 48.05,35.46 47.99,35.4 47.99,35.28 48.05,35.22 49.71,35.22 49.77,35.16 49.77,35.04 49.71,34.98 48.05,34.98 47.99,34.92 47.99,34.8 48.05,34.74 49.71,34.74 49.77,34.68 49.77,34.56 49.71,34.5 48.05,34.5 47.99,34.44 47.99,34.32 48.05,34.26 49.71,34.26 49.77,34.2 49.77,34.08 49.71,34.02 49.11,34.02 49.05,33.96 49.05,33.25 48.99,33.19 48.39,33.19 48.33,33.13 48.33,33.01 48.39,32.95 49.71,32.95 49.77,32.89 49.77,32.77 49.71,32.71 48.39,32.71 48.33,32.65 48.33,32.53 48.39,32.47 49.71,32.47 49.77,32.41 49.77,32.29 49.71,32.23 48.39,32.23 48.33,32.17 48.33,32.05 48.39,31.99 49.71,31.99 49.77,31.93 49.77,31.81 49.71,31.75 48.39,31.75 48.33,31.69 48.33,31.57 48.39,31.51 49.71,31.51 49.77,31.45 49.77,31.33 49.71,31.27 48.39,31.27 48.33,31.21 48.33,31.09 48.39,31.03 49.71,31.03 49.77,30.97 49.77,30.85 49.71,30.79 48.39,30.79 48.33,30.73 48.33,30.61 48.39,30.55 48.99,30.55 49.05,30.49 49.05,29.6 51.825,26.825 51.825,25.323 U19.33@52.004,25.144
PI10: U5.D5 U19.32 | length 57.8
  Top w0.12: U5.D5@39.2,37.65 v1(39.6,38.05)
  Bottom w0.12: v1(39.6,38.05) 40,37.65 42.2,37.65 42.75,38.2 44.25,38.2 44.6,37.85 45.44,37.85 45.5,37.79 45.5,37.72 45.56,37.66 45.68,37.66 45.74,37.72 45.74,38.51 45.8,38.57 45.92,38.57 45.98,38.51 45.98,37.72 46.04,37.66 46.16,37.66 46.22,37.72 46.22,38.51 46.28,38.57 46.4,38.57 46.46,38.51 46.46,37.69 46.52,37.63 46.64,37.63 46.7,37.69 46.7,38.51 46.76,38.57 46.88,38.57 46.94,38.51 46.94,37.65 47,37.59 47.12,37.59 47.18,37.65 47.18,38.21 47.24,38.27 47.36,38.27 47.42,38.21 47.42,37.91 47.48,37.85 47.9,37.85 48.027,37.723 48.112,37.723 48.307,37.918 48.392,37.918 48.477,37.833 48.477,37.748 48.184,37.455 48.184,37.37 48.269,37.285 48.354,37.285 48.981,37.913 49.066,37.913 49.151,37.828 49.151,37.743 48.523,37.116 48.523,37.031 48.608,36.946 48.693,36.946 49.321,37.573 49.405,37.573 49.49,37.489 49.49,37.404 48.863,36.776 48.863,36.691 48.948,36.606 49.032,36.606 49.66,37.234 49.745,37.234 49.83,37.149 49.83,37.064 49.202,36.437 49.202,36.352 49.287,36.267 49.372,36.267 49.999,36.895 50.084,36.895 50.169,36.81 50.169,36.725 49.542,36.097 49.542,36.012 49.626,35.928 49.711,35.928 50.081,36.297 50.166,36.297 50.25,36.212 50.25,36.127 49.881,35.758 49.881,35.673 49.966,35.588 50.051,35.588 50.54,36.078 50.625,36.078 50.71,35.993 50.71,35.908 50.22,35.418 50.22,35.334 50.305,35.249 50.39,35.249 51.018,35.876 51.103,35.876 51.187,35.791 51.187,35.707 50.56,35.079 50.56,34.994 50.645,34.909 50.729,34.909 50.743,34.923 50.827,34.923 51.95,33.8 51.95,33.14 51.89,33.08 50.98,33.08 50.92,33.02 50.92,32.9 50.98,32.84 52,32.84 52.06,32.78 52.06,32.66 52,32.6 51.39,32.6 51.33,32.54 51.33,32.42 51.39,32.36 52,32.36 52.06,32.3 52.06,32.18 52,32.12 51.32,32.12 51.26,32.06 51.26,31.94 51.32,31.88 52,31.88 52.06,31.82 52.06,31.7 52,31.64 50.98,31.64 50.92,31.58 50.92,31.46 50.98,31.4 52,31.4 52.06,31.34 52.06,31.22 52,31.16 50.98,31.16 50.92,31.1 50.92,30.98 50.98,30.92 52,30.92 52.06,30.86 52.06,30.74 52,30.68 50.98,30.68 50.92,30.62 50.92,30.5 50.98,30.44 52,30.44 52.06,30.38 52.06,30.26 52,30.2 50.98,30.2 50.92,30.14 50.92,30.02 50.98,29.96 52,29.96 52.06,29.9 52.06,29.78 52,29.72 51.77,29.72 51.71,29.66 51.71,29.54 51.77,29.48 51.89,29.48 51.95,29.42 51.95,29.24 52.01,29.18 52.15,29.18 52.21,29.12 52.21,29 52.15,28.94 51.89,28.94 51.83,28.88 51.83,28.76 51.89,28.7 52.15,28.7 52.21,28.64 52.21,28.52 52.15,28.46 52.01,28.46 51.95,28.4 51.95,27.6 52.625,26.925 U19.32@52.625,25.323
PI11: SB6.1 U5.F3 | length 95.5
  Top w0.12: v1(37.2,39.65) U5.F3@37.6,39.25
  Top w0.3: v1(116.4,49) SB6.1@118.5,49
  F4 w0.12: v1(37.2,39.65) 37.6,40.05 37.6,40.8 38.65,41.85 38.65,41.92 39.3,41.92 42.32,44.94 50.42,44.94 51.82,46.34 67.25,46.34 67.91,47 86.75,47 91.55,42.2 108.7,42.2 110.4,40.5 114.5,40.5 115.1,41.1 115.1,47.7 v1(116.4,49)
PI12: R74.1 U5.E3 U19.31 | length 30.1
  Top w0.12: U5.E3@38.4,39.25 v1(38.8,39.65) ; R74.1@54.3,23.5 R74.1@54.4,23.5
  Top w0.2: v1(53.6,23.4) 53.7,23.5 R74.1@54.3,23.5
  Bottom w0.12: v1(38.8,39.65) 39.2,39.25 41.9,39.25 42.65,38.5 44,38.5 44.63,39.13 49.13,39.13 51.5,36.76 51.5,34.85 52.3,34.05 52.3,31.7 52.794,31.206 52.794,27.36 53.425,26.729 53.425,23.975 53.604,23.796 53.604,23.4 v1(53.6,23.4)
PI13: U5.G3 U19.38 | length 23.7
  Top w0.12: v1(36.4,39.65) U5.G3@36.8,39.25
  Bottom w0.12: v1(36.4,39.65) 36.8,39.25 36.8,36 38.2,34.6 42.1,34.6 42.45,34.25 45.1,34.25 46.1,33.25 46.1,30.2 48.004,28.296 48.004,26.675 47.8,26.471 U19.38@47.8,25.25
PI14: U5.H3 U19.30 | length 57.8
  Top w0.12: v1(35.6,39.65) U5.H3@36,39.25
  F4 w0.12: v1(35.6,39.65) 36,39.25 42.3,39.25 42.7,38.85 44.05,38.85 44.4,39.2 50.85,39.2 v1(51.15,38.9)
  Bottom w0.12: v1(51.15,38.9) 51.15,37.79 53.22,35.72 53.22,35.42 53.16,35.36 52.75,35.36 52.69,35.3 52.69,35.18 52.75,35.12 53.6,35.12 53.66,35.06 53.66,34.94 53.6,34.88 52.75,34.88 52.69,34.82 52.69,34.7 52.75,34.64 53.6,34.64 53.66,34.58 53.66,34.46 53.6,34.4 52.75,34.4 52.69,34.34 52.69,34.22 52.75,34.16 53.6,34.16 53.66,34.1 53.66,33.98 53.6,33.92 52.75,33.92 52.69,33.86 52.69,33.74 52.75,33.68 53.6,33.68 53.66,33.62 53.66,33.5 53.6,33.44 52.75,33.44 52.69,33.38 52.69,33.26 52.75,33.2 53.6,33.2 53.66,33.14 53.66,33.02 53.6,32.96 52.75,32.96 52.69,32.9 52.69,32.78 52.75,32.72 53.6,32.72 53.66,32.66 53.66,32.54 53.6,32.48 52.75,32.48 52.69,32.42 52.69,32.3 52.75,32.24 53.6,32.24 53.66,32.18 53.66,32.06 53.6,32 53.28,32 53.22,31.94 53.22,31.73 54.404,30.546 54.404,30.36 54.464,30.3 55.06,30.3 55.12,30.24 55.12,30.12 55.06,30.06 53.75,30.06 53.69,30 53.69,29.88 53.75,29.82 55.06,29.82 55.12,29.76 55.12,29.64 55.06,29.58 53.75,29.58 53.69,29.52 53.69,29.4 53.75,29.34 55.06,29.34 55.12,29.28 55.12,29.16 55.06,29.1 53.75,29.1 53.69,29.04 53.69,28.92 53.75,28.86 55.06,28.86 55.12,28.8 55.12,28.68 55.06,28.62 53.75,28.62 53.69,28.56 53.69,28.44 53.75,28.38 55.06,28.38 55.12,28.32 55.12,28.2 55.06,28.14 53.75,28.14 53.69,28.08 53.69,27.96 53.75,27.9 54.344,27.9 54.344,26.644 54.175,26.475 54.175,25.275 U19.30@54.2,25.25
PJ12: R58.1 U5.B10 | length 4.4
  Top w0.12: U5.B10@40.8,33.65 41.2,33.25 42.15,33.25 42.85,32.55 43.7,32.55 44,32.25 R58.1@44.65,32.25
PK3: R81.2 U5.D8 | length 51.5
  Top w0.12: U5.D8@39.2,35.25 39.55,35.6 v1(39.6,35.6)
  Top w0.2: v1(71.46,19.75) R81.2@72.4,19.75
  F4 w0.2: v1(67.35,35.6) 67.33,35.6 68.14,34.79 68.14,25.68 66.42,23.96 66.42,20.96 67.63,19.75 v1(71.46,19.75)
  F5 w0.12: v1(39.6,35.6) 40,35.2 42.4,35.2 43.2,34.4 48.7,34.4 48.85,34.55 54.65,34.55 55,34.9 63.5,34.9 64.2,35.6 v1(67.35,35.6)
PK7: U5.C4 U19.34 | length 21.9
  Top w0.12: U5.C4@40,38.45 v1(40.4,38.85)
  F6 w0.12: v1(40.4,38.85) 41.3,38.85 41.6,38.55 41.6,37.85 42.25,37.2 v1(42.9,37.2)
  Bottom w0.12: v1(42.9,37.2) 43.45,36.65 44.95,36.65 45.8,35.8 45.8,34.7 46.2,34.3 47.5,34.3 47.65,34.15 47.65,29.5 48.9,28.25 50,28.25 51.05,27.2 51.05,25.298 U19.34@51.204,25.144
PWR_ENN: R60.1 U8.3 U14.28 | length 40
  Top w0.25: U14.28@104,0.1 v1(104,1.85)
  Top w0.3: v1(91.85,26.5) 91.865,26.5 U8.3@91.865,27.73 91.865,29.5 R60.1@91.9,29.5
  Bottom w0.3: v1(91.85,26.5) 101,26.5 102.75,24.75 102.75,17.5 103.55,16.7 103.55,9.45 103.4,9.3 103.4,2.45 v1(104,1.85)
PWR_EXT: R108.1 R109.1 R112.2 U14.39 | length 5.1
  Top w0.25: U14.39@109.65,2.75 110.9,2.75 111.15,2.5 R112.2@112.15,2.5 R109.1@112.15,3.75 R108.1@112.15,5
RD_N: CN9.8 R90.2 U9.22 | length 10.6
  Top w0.125: R90.2@43.75,16.6 44.37,16.6 44.375,16.595 ; CN9.8@44.662,11.099 44.662,13.112 45.02,13.47 45.02,14.031 44.6,14.451 44.6,16.37 44.375,16.595 ; U9.22@46.822,18.639 46.822,17.862 46.54,17.58 44.911,17.58 44.59,17.259 44.59,16.81 44.375,16.595
RD_P: CN9.7 R91.2 U9.23 | length 10.7
  Top w0.125: CN9.7@45.678,11.099 45.678,13.1 45.31,13.468 45.31,14.15 44.89,14.57 44.89,16.34 45.15,16.6 ; R91.2@45.8,16.6 45.15,16.6 ; U9.23@47.322,18.639 47.322,17.953 46.659,17.29 45.03,17.29 44.88,17.14 44.88,16.87 45.15,16.6
REFSEL0: R103.2 R104.1 U15.8 | length 4.5
  Top w0.12: R104.1@64.85,6 67,6 67.25,5.75 U15.8@67.25,5.05 ; R104.1@64.85,6.2 R103.2@64.85,7.45
REFSEL1: R106.2 R110.1 U15.11 | length 3.1
  Top w0.12: R110.1@64.85,3.5 U15.11@66.7,3.5 ; R110.1@64.85,3.7 R106.2@64.85,4.95
REFSEL2: R111.2 R113.1 U15.14 | length 3.2
  Top w0.12: R113.1@64.85,1.2 R111.2@64.85,2.45 ; R111.2@64.85,2.25 65.85,2.25 66.1,2 U15.14@66.7,2
STLINK_RX: SB13.2 U14.13 | length 4.2
  Top w0.2: SB13.2@96.6,7.25 U14.13@100.85,7.25
STLINK_TX: SB12.2 U14.12 | length 6
  Top w0.2: SB12.2@96.6,8.75 99.15,8.75 99.3,8.9 U14.12@102.5,8.9
STM_JTCK: CN8.2 U14.37 | length 22.9
  Top w0.25: U14.37@109.65,1.75 110.65,1.75 110.85,1.55 v1(110.85,0.5)
  Bottom w0.25: v1(110.85,0.5) 110.85,0.6 116.05,0.6 119.8,-3.15 122.5,-3.15 123.05,-2.6 123.05,1.96 CN8.2@121.7,3.31
STM_JTMS: CN8.4 U14.34 | length 17.5
  Top w0.25: U14.34@107,0.1 v1(107,1.5)
  Bottom w0.25: v1(107,1.5) 116.45,1.5 119.72,-1.77 CN8.4@121.7,-1.77
STM_RST: C98.2 R99.1 SB11.2 U14.7 | length 5.1
  Top w0.2: SB11.2@104.25,11.15 105,10.4 U14.7@105,8.9
  Top w0.25: R99.1@101.75,11.15 C98.2@103,11.15 SB11.2@104.25,11.15
T_JTCK: SB14.1 U14.15 U14.26 | length 12.8
  Top w0.25: SB14.1@96.5,5.75 98,5.75 98.5,6.25 U14.15@100.85,6.25 v1(102.75,6.25) ; U14.26@103,0.1 103,1.3 v1(103.1,1.4)
  Bottom w0.25: v1(102.75,6.25) 103,6 103,1.5 v1(103.1,1.4)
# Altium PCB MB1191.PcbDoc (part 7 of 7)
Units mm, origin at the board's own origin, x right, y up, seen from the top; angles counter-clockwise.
Board outline 130 x 80 mm, 8 copper layers (Top, F2, F3, F4, F5, F6, F7, Bottom), stack 1.115 mm thick; 360 components, 347 nets, 1451 pads, 1068 vias.

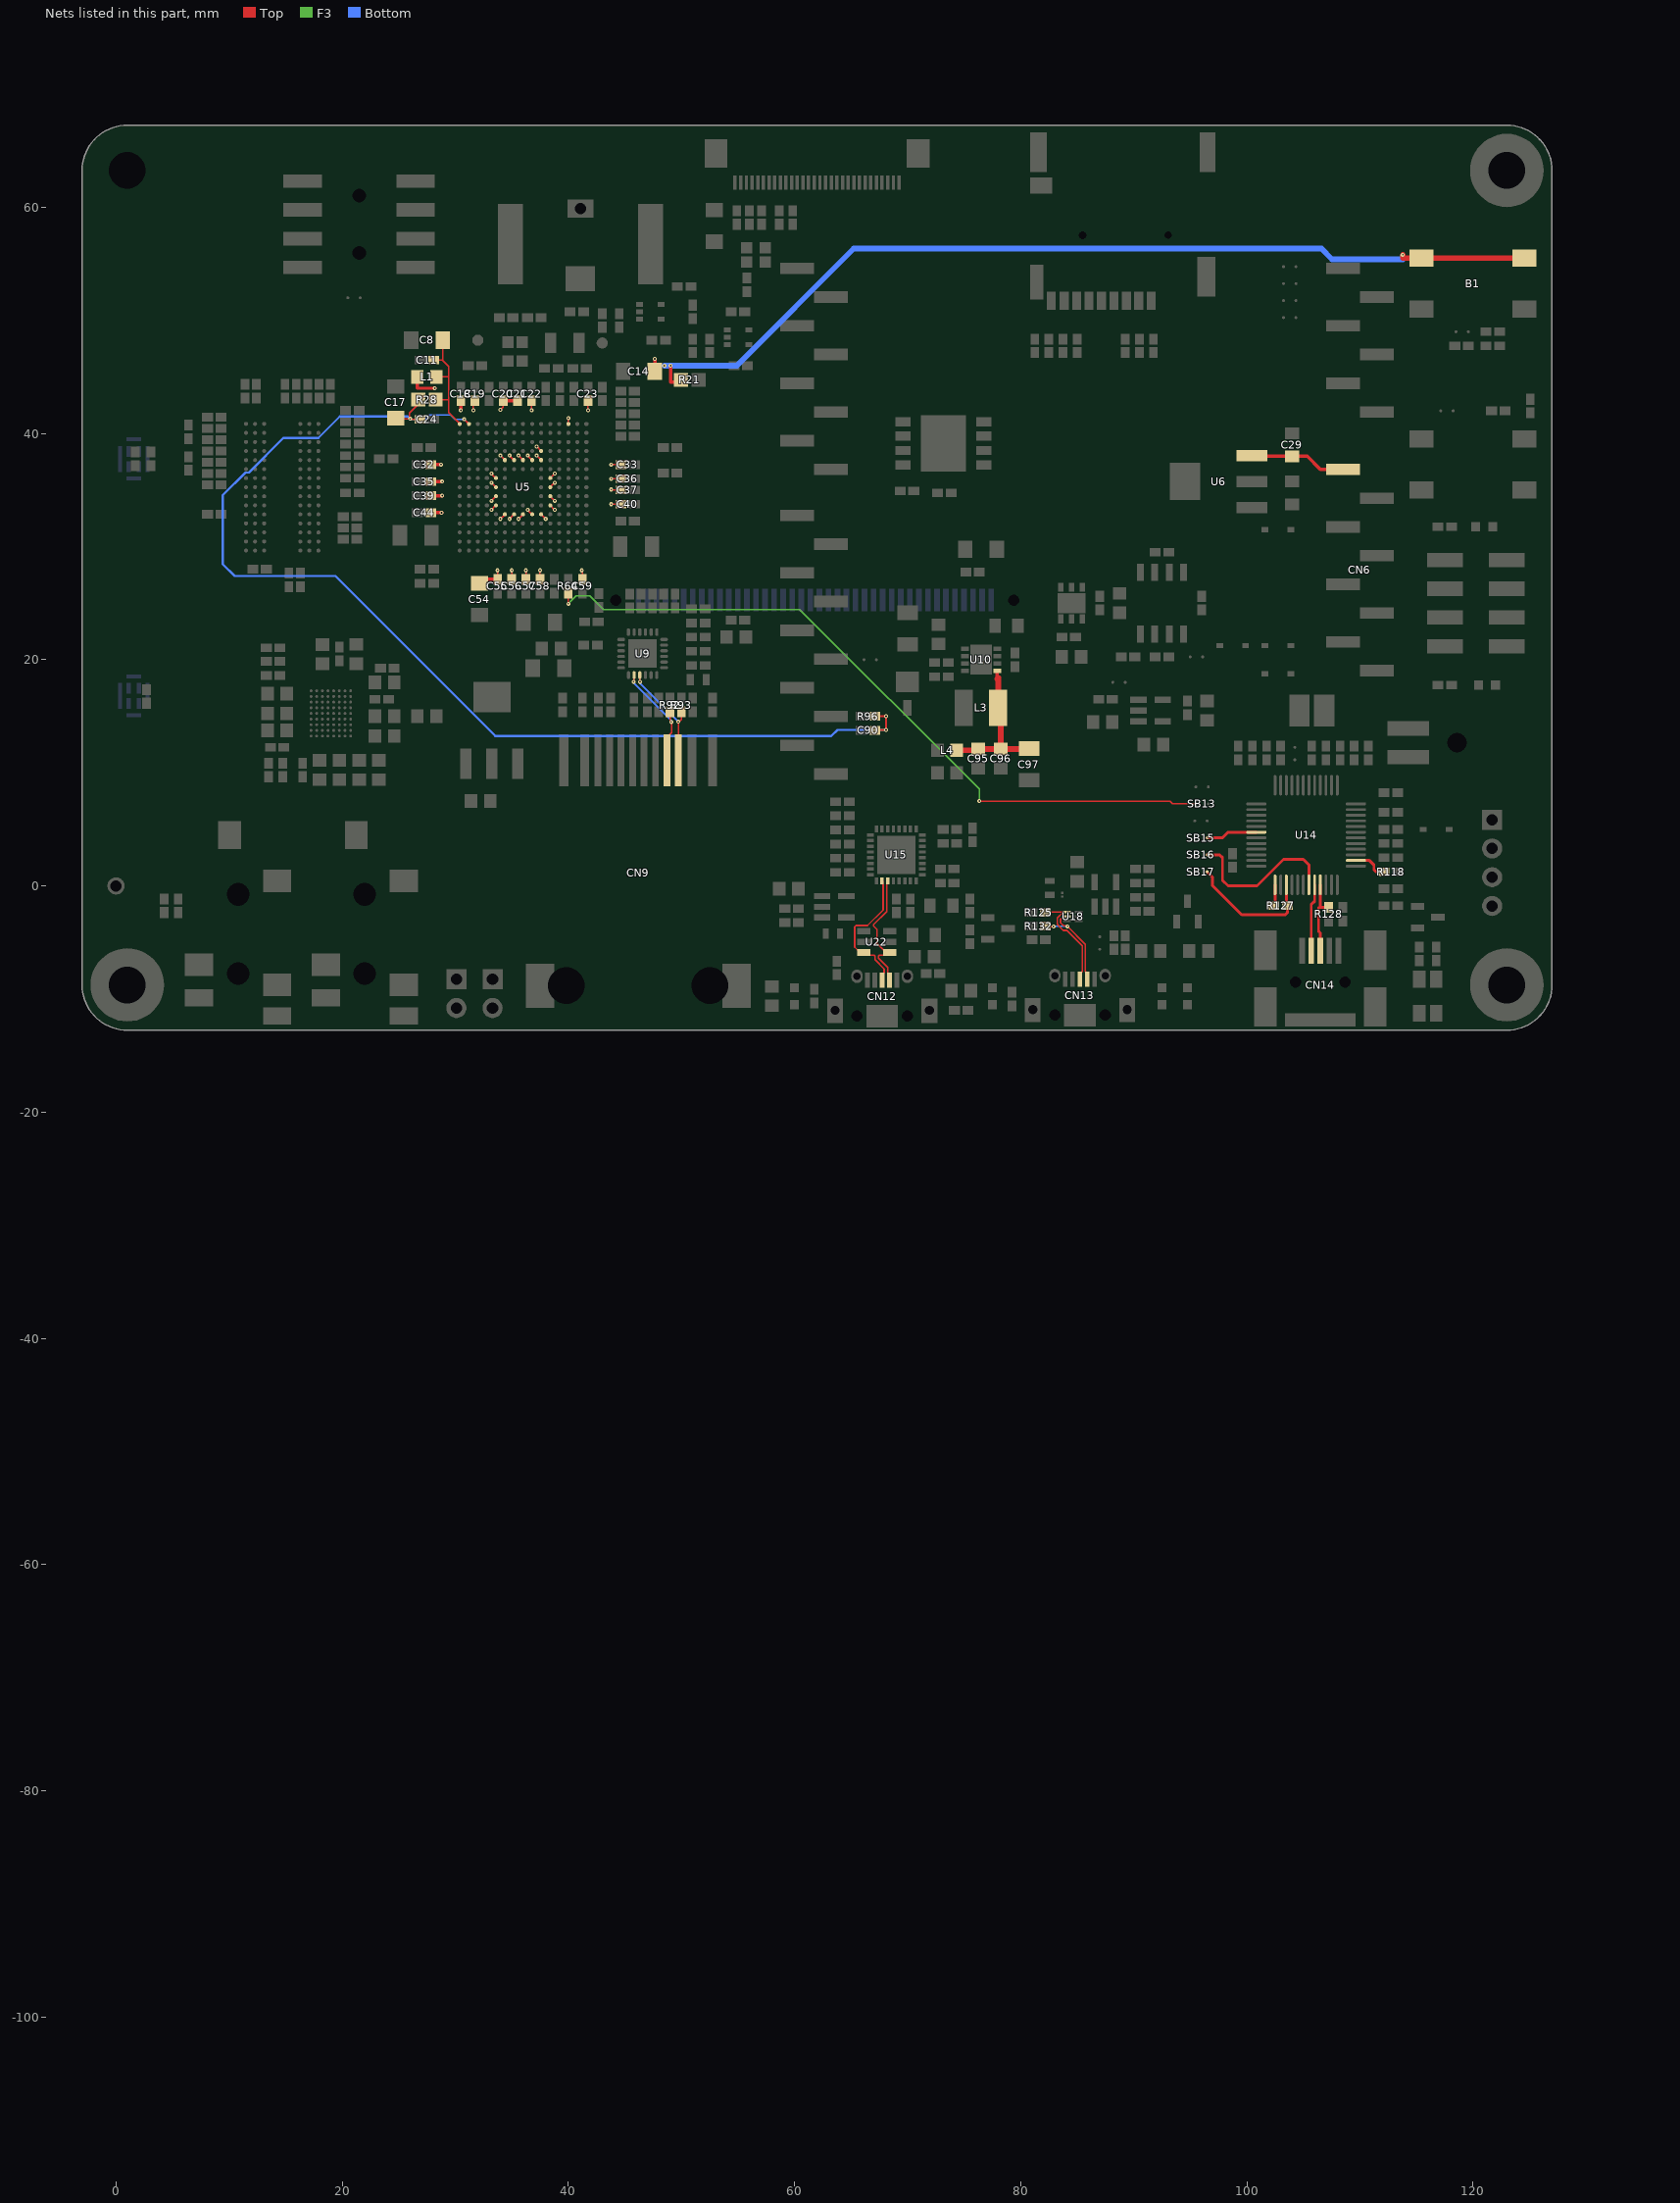
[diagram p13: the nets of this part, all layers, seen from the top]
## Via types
v1: diameter 0.35, hole 0.15, Top to Bottom, tented both sides, 1041 vias
v2: diameter 0.25, hole 0.1, Top to Bottom, tented both sides, 26 vias
v3: diameter 0.3, hole 0.1, Top to Bottom, tented both sides, 1 vias

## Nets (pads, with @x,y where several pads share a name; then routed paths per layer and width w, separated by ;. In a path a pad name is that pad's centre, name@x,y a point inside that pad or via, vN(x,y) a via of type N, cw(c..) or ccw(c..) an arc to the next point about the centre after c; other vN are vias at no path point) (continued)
T_JTMS: R127.1 SB17.1 U14.27 | length 11.7
  Top w0.25: SB17.1@96.5,1.25 96.95,0.8 96.95,0.05 99.55,-2.55 103.4,-2.55 103.6,-2.35 R127.1@103.6,-1.75 103.5,-1.75 U14.27@103.5,0.1
T_NRST: SB15.1 U14.18 | length 4.6
  Top w0.25: SB15.1@96.5,4.25 97.85,4.25 98.35,4.75 U14.18@100.85,4.75
T_SWDIO_IN: R127.2 U14.25 | length 2
  Top w0.25: R127.2@102.4,-1.75 102.5,-1.75 U14.25@102.5,0.1
T_SWO: SB16.1 U14.31 | length 14.2
  Top w0.25: SB16.1@96.5,2.75 97.6,2.75 97.85,2.5 97.85,0.5 98.35,0 100.9,0 103.25,2.35 105,2.35 105.5,1.85 U14.31@105.5,0.1
TD_N: CN9.4 R92.2 U9.20 | length 10.2
  Top w0.125: v1(45.77,18.05) 45.822,18.05 U9.20@45.822,18.639 ; CN9.4@48.726,11.099 48.726,13.12 49.15,13.544 49.15,14.5 v1(49.1,14.5) 49,14.5 R92.2@49,15.4
  Bottom w0.125: v1(45.77,18.05) 45.8,18.05 45.8,17.941 49.11,14.631 49.11,14.5 v1(49.1,14.5)
TD_P: CN9.3 R93.2 U9.21 | length 10
  Top w0.125: U9.21@46.322,18.639 46.322,18.05 v1(46.34,18.05) ; CN9.3@49.742,11.099 49.742,14.468 49.71,14.5 v1(49.72,14.51) 49.8,14.51 50,14.71 R93.2@50,15.4
  Bottom w0.125: v1(46.34,18.05) 46.34,17.91 49.72,14.53 v1(49.72,14.51)
USB_DM: CN14.2 U14.32 | length 6
  Top w0.25: CN14.2@105.703,-5.75 105.703,-1.647 106,-1.35 U14.32@106,0.1
USB_DP: CN14.3 R128.1 U14.33 | length 6.8
  Top w0.25: U14.33@106.5,0.1 106.5,-1.8 106.4,-1.9 ; CN14.3@106.503,-5.75 106.503,-4.153 106.35,-4 106.35,-1.95 106.4,-1.9 ; R128.1@107.25,-1.9 106.4,-1.9
USB_FS1_N: CN13.2 R132.2 U18.2 | length 9
  Top w0.15: R132.2@82.2,-3.55 82.232,-3.582 v1(82.906,-3.582) ; v1@84.093,-3.532 83.806,-3.532 83.53,-3.255 83.53,-2.945 83.749,-2.725 84.075,-2.725 U18.2@84.1,-2.7 ; v1(84.15,-3.57) 84.15,-3.592 85.73,-5.172 85.73,-7.56 85.9,-7.73 CN13.2@85.9,-8.25
  Bottom w0.15: v1(82.906,-3.582) 82.918,-3.57 v1(84.15,-3.57)
USB_FS1_P: CN13.3 R125.2 U18.1 | length 9.3
  Top w0.15: R125.2@82.2,-2.35 82.25,-2.3 U18.1@83.85,-2.3 ; U18.1@84.1,-2.3 83.925,-2.3 U18.1@83.85,-2.3 ; CN13.3@85.25,-8.25 85.25,-7.75 85.45,-7.55 85.45,-5.288 84.102,-3.94 83.787,-3.94 83.25,-3.402 83.25,-2.825 83.749,-2.325 83.825,-2.325 U18.1@83.85,-2.3
USB_HS_N: CN12.2 U15.19 U22.1 | length 11.3
  Top w0.15: U22.1@67.95,-6.05 U22.1@67.95,-5.725 ; U22.1@68.2,-6.125 67.523,-6.125 67.435,-6.213 67.435,-6.392 68.242,-7.199 68.242,-7.678 68.407,-7.843 CN12.2@68.407,-8.318 ; U15.19@68.25,0.45 68.175,0.375 68.175,0.102 68.16,0.087 68.16,-2.253 66.998,-3.415 66.998,-3.539 67.31,-3.851 67.31,-5.085 U22.1@67.95,-5.725 ; U22.1@68.425,-5.9 68.125,-5.9 U22.1@67.95,-5.725
USB_HS_P: CN12.3 U15.18 U22.6 | length 12.2
  Top w0.15: U15.18@67.75,0.45 67.825,0.375 67.825,0.102 67.84,0.087 67.84,-2.121 66.456,-3.505 65.444,-3.505 65.33,-3.619 65.33,-5.405 65.825,-5.9 U22.6@66.125,-5.9 66.35,-6.125 67.027,-6.125 67.115,-6.213 67.115,-6.524 67.922,-7.332 67.922,-7.678 67.757,-7.843 CN12.3@67.757,-8.318 CN12.3@67.755,-8.315
USB_RENUMN: R118.2 U14.38 | length 3.1
  Top w0.25: U14.38@109.65,2.25 110.85,2.25 111.25,1.85 111.25,1.45 111.45,1.25 R118.2@112.15,1.25
VCP_TX: R64.1 SB13.1 | length 65
  Top w0.12: v1(40,24.95) R64.1@40,25.9 ; v1(76.35,7.5) 93.2,7.5 93.45,7.25 SB13.1@95.5,7.25
  F3 w0.12: v1(40,24.95) 40.7,25.65 41.9,25.65 43.1,24.45 60.45,24.45 76.35,8.55 v1(76.35,7.5)
VDD: B1.1 B1.4 C14.1 C18.2 C19.2 C20.2 C21.2 C22.2 C23.2 C32.2 C33.2 C35.2 C36.2 C37.2 C39.2 C40.2 C44.2 C54.1 C55.2 C56.2 C57.2 C58.2 C59.2 L1.1 R21.1 U5.C1 U5.E7 U5.E8 U5.E9 U5.E10 U5.F4 U5.F5 U5.F11 U5.G5 U5.G11 U5.H5 U5.H11 U5.J5 U5.J11 U5.K5 U5.K11 U5.L7 U5.L8 U5.L9 U5.L10 | length 118.4
  Top w0.12: v1(31.6,42.05) 31.6,42.9 C19.2@31.75,42.9 ; v1(33.2,33.25) U5.L10@33.6,33.65 ; v1(33.2,34.05) U5.L9@33.6,34.45 ; v1(33.2,35.65) U5.L8@33.6,35.25 ; v1(33.2,36.45) U5.L7@33.6,36.05 ; C55.2@33.75,27.1 v1(33.75,27.9) ; v1(34,32.45) U5.K11@34.4,32.85 ; v1(34,38.05) U5.K5@34.4,37.65 ; v1(34,42.1) 34.25,42.35 C20.2@34.25,42.9 ; v1(34.8,32.45) U5.J11@35.2,32.85 ; v1(34.8,38.05) U5.J5@35.2,37.65 ; C56.2@35,27.1 v1(35,27.9) ; v1(35.6,32.45) U5.H11@36,32.85 ; v1(35.6,38.05) U5.H5@36,37.65 ; C57.2@36.25,27.1 v1(36.25,27.9) ; v1(36.4,33.25) U5.G11@36.8,32.85 ; v1(36.4,38.05) U5.G5@36.8,37.65 ; v1(36.75,42.05) C22.2@36.75,42.9 ; v1(37.2,38.05) U5.F5@37.6,37.65 ; v1(37.2,38.85) U5.F4@37.6,38.45 ; C58.2@37.5,27.1 v1(37.5,27.9) ; U5.F11@37.6,32.85 v1(38,32.45) ; U5.E10@38.4,33.65 v1(38.8,33.25) ; U5.E9@38.4,34.45 v1(38.8,34.05) ; U5.E8@38.4,35.25 v1(38.8,35.65) ; U5.E7@38.4,36.05 v1(38.8,36.45) ; U5.C1@40,40.85 v1(40,41.35) ; v1(41.2,27.9) 41.25,27.85 C59.2@41.25,27.1 ; v1(41.75,42.05) C23.2@41.75,42.9 ; v1(43.8,33.75) C40.2@44.65,33.75 ; v1(43.8,35.05) 43.8,35 C37.2@44.65,35 ; v1(43.8,36) C36.2@44.65,36 ; v1(43.8,37.25) C33.2@44.65,37.25 ; v1@47.647,46.6 v1(47.65,46.6)
  Top w0.3: L1.1@26.65,45.35 26.65,44 v1(28.2,44) ; C44.2@27.85,33 v1(28.8,33) ; C39.2@27.85,34.5 v1(28.85,34.5) ; C35.2@27.85,35.75 v1(28.85,35.75) ; C32.2@27.85,37.25 v1(28.75,37.25) ; v1(30.5,42.05) C18.2@30.5,42.9 ; C54.1@32,26.647 32,27.1 C55.2@33.75,27.1 ; C20.2@34.25,42.9 C21.2@35.5,42.9 ; C14.1@47.647,45.5 v1@47.647,46.6 ; v1(49.05,46) 49.05,44.55 49.975,44.55 R21.1@49.975,44.75
  Top w0.5: v1(113.8,55.8) 113.8,55.5 B1.4@124.55,55.5
  Bottom w0.5: v1(48.5,46) v1(49.05,46) 54.9,46 65.25,56.35 106.6,56.35 107.55,55.4 113.8,55.4 v1@113.8,55.725
VDDA: C8.1 C11.2 L1.2 R28.1 U5.R1 | length 11
  Top w0.12: C11.2@28.1,46.5 28.85,46.5 ; R28.1@28.275,43 29.4,43 ; L1.2@28.35,45 29.4,45 ; C8.1@28.897,48.25 28.897,46.503 28.9,46.5 28.85,46.5 ; U5.R1@30.4,40.85 29.4,41.85 29.4,43 ; 28.85,46.5 29.4,45.95 29.4,45 ; 29.4,43 29.4,45
VIN: C29.2 CN6.8 U6.3 | length 8.6
  Top w0.3: U6.3@100.45,38.05 100.45,37.984 C29.2@104,37.984 105.336,37.984 106.5,36.82 CN6.8@108.5,36.82
VL: C95.2 C96.2 C97.1 L3.1 L4.2 U10.1 | length 14.5
  Top w0.3: L3.1@77.925,16 77.925,15.75 L3.1@78.024,15.75 ; 77.925,18.3 U10.1@77.925,19.025 ; C97.1@80.75,12.1 C97.1@80.75,12.147
  Top w0.5: L4.2@74.35,12 76.32,12 C95.2@76.32,12.1 ; C95.2@76.25,12.1 C95.2@76.32,12.1 ; L3.1@77.925,16 78.25,15.675 C96.2@78.25,12.1 ; 77.925,18.3 78.024,18.399 L3.1@78.024,15.75 ; C97.1@80.75,12.1 C96.2@78.25,12.1 ; C95.2@76.32,12.1 C96.2@78.25,12.1
VREF+: C17.1 C24.2 C90.2 R28.2 R96.2 U5.P1 | length 104
  Top w0.12: C17.1@24.75,41.353 24.75,41.3 v1@25.95,41.3 ; v1(26,41.3) v1@25.95,41.3 ; R28.2@26.725,43 26.65,42.5 25.95,41.8 v1@25.95,41.3 ; C24.2@26.9,41.25 26,41.25 v1@25.95,41.3 ; v1(30.8,41.25) U5.P1@31.2,40.85
  Top w0.2: C90.2@67.1,13.75 67.1,13.8 v1(68.1,13.8) v1(68.1,15) R96.2@67.1,15
  Bottom w0.12: v1(26,41.3) 26,41.25 27.34,41.25 27.73,41.64 29.58,41.64 29.97,41.25 v1(30.8,41.25)
  Bottom w0.2: v1(26,41.3) 25.8,41.5 19.8,41.5 17.9,39.6 14.8,39.6 11.75,36.55 11.45,36.55 9.45,34.55 9.45,28.45 10.5,27.4 19.4,27.4 33.55,13.25 63.25,13.25 63.8,13.8 v1(68.1,13.8)
pads on no net: CN2.2 CN2.6 CN2.9 CN2.10 CN3.NPTH1 CN3.NPTH2 CN6.1 CN9.9 CN9.15 CN9.16 CN10.1 CN10.5 CN10.7 CN10.8 CN11.1 CN11.5 CN11.7 CN11.8 CN12.11 CN12.12 CN13.11 CN13.12 CN14.11 CN14.12 FX4.1 JP2.0 P1.2 P1.3 P1.12 P1.13 P1.18 P1.22 P1.24 P1.31 P1.32 U1.1 U2.1 U3.9 U4.E3 U4.E7 U4.H3 U4.H7 U4.K2 U4.K3 U7.3 U7.5 U9.4 U10.5 U11.A6 U11.A8 U11.B4 U11.B5 U11.B6 U11.B8 U11.B9 U11.C4 U11.C5 U11.C7 U11.C8 U11.E1 U11.E5 U11.F4 U11.F5 U11.F6 U11.F8 U11.F9 U11.G4 U11.H2 U11.H3 U11.H4 U11.H5 U14.4 U14.11 U14.14 U14.16 U14.17 U14.19 U14.21 U14.22 U14.29 U14.40 U14.41 U14.42 U14.43 U14.45 U14.46 U15.12 U15.15 U15.16 U15.25 U19.NPTH1 U19.NPTH2 U22.3 U22.5
copper on no net: | length 288
  Top w0.21: 99.8,60.55 99.8,66.55 111.8,66.55 111.8,60.55 99.8,60.55
  F2 w0.21: 99.8,60.55 111.8,60.55 111.8,66.55 99.8,66.55 99.8,60.55
  F3 w0.21: 99.8,60.55 111.8,60.55 111.8,66.55 99.8,66.55 99.8,60.55
  F4 w0.21: 99.8,60.55 111.8,60.55 111.8,66.55 99.8,66.55 99.8,60.55
  F5 w0.21: 99.8,60.55 111.8,60.55 111.8,66.55 99.8,66.55 99.8,60.55
  F6 w0.21: 99.8,60.55 111.8,60.55 111.8,66.55 99.8,66.55 99.8,60.55
  F7 w0.21: 99.8,60.55 111.8,60.55 111.8,66.55 99.8,66.55 99.8,60.55
  Bottom w0.21: 99.725,60.475 111.725,60.475 111.725,66.475 99.725,66.475 99.725,60.475

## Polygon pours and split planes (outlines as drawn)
GND on Top "TEMPLATE22" (solid, remove dead copper, pour order 126): -3,-8.75 -3,63.25 cw(c1,63.25) 1,67.25 123,67.25 cw(c123,63.25) 127,63.25 127,-8.75 cw(c123,-8.75) 123,-12.75 75.7,-12.75 75.7,-7.65 74.9,-6.85 61.2,-6.85 60.4,-7.65 60.4,-12.783 23.495,-12.75 5.08,-12.75 0.985,-12.743 cw(c0.993,-8.75)
NetC120_2 on Top "TEMPLATE 1" (solid, remove dead copper, pour order 125): 61,-12.75 61,-7.95 61.7,-7.25 74.2,-7.25 74.8,-7.85 74.8,-12.75
5V_ST_LINK on Top "tpl6" (solid, remove dead copper, pour order 116): 114.55,25.1 117.7,25.1 117.7,27.39 114.55,27.39
5V_USB_HS on Top "TEMPLATE5" (solid, remove dead copper, pour order 118): 114.55,19.99 117.68,19.99 117.68,22.37 114.55,22.37
3V3 on Top "TEMPLATE15" (solid, remove dead copper, pour order 113): 34.9,12.25 34.9,8.65 35.1,8.45 36,8.45 36.2,8.65 36.2,12.25
E5V on Top "TEMPLATE9" (solid, remove dead copper, pour order 122): 105.75,36.25 96.4,36.25 96.1,36.55 96.1,37.55 93,37.55 93,33.95 96.1,33.95 96.1,35.05 96.3,35.25 106.75,35.25
1V8 on Top "TEMPLATE16" (solid, remove dead copper, pour order 123): 31.5,18.15 31.5,14.95 32.7,13.75 32.7,9.35 32.5,9.15 32.5,6.75 34.3,6.75 34.5,6.95 34.5,8.66 33.8,9.36 33.8,13.65 35,14.85 35,18.15
VIN on Top "TEMPLATE18" (solid, remove dead copper, pour order 121): 98.9,38.65 98.9,37.45 105.3,37.45 106.5,36.25 110.1,36.25 110.1,37.45 106.8,37.45 105.6,38.65
GND on Top "TEMPLATE19" (solid, remove dead copper, pour order 120): 99,34.05 102.7,34.05 103,34.35 104.8,34.35 104.9,34.25 104.9,32.55 104.8,32.45 103,32.45 102.6,32.85 99,32.85
5V on Top "TEMPLATE14" (solid, remove dead copper, pour order 119): 85.2,23.92 86.4,23.92 86.4,24.89 89.5,24.89 89.5,23.15 89.2,22.85 85.2,22.85
5V_USB_FS on Top "TEMPLATE7" (solid, remove dead copper, pour order 115): 114.55,22.57 117.67,22.57 117.67,24.86 114.55,24.86
3V3 on Top "TEMPLATE12" (solid, remove dead copper, pour order 114): 83.29,24.01 83.29,23.19 82.9,22.8 82.9,18.85 83.1,18.65 84.1,18.65 84.34,18.89 84.34,21.11 84.16,21.29 84.16,22.81 83.81,23.16 83.81,24.01
5V on Top "tpl8" (solid, remove dead copper, pour order 124): 119.4,18.75 123.15,18.75 123.15,29.94 120.25,29.94 120.25,29.95 119.4,29.95
E5V on Top "tpl7" (solid, remove dead copper, pour order 117): 114.55,27.65 117.7,27.65 117.7,29.94 114.55,29.94
GND on F5 "tpl3" (solid, remove dead copper, pour order 135): -3,-8.75 -3,63.25 cw(c1,63.25) 1,67.25 123,67.25 cw(c123,63.25) 127,63.25 127,-8.75 cw(c123,-8.75) 123,-12.75 75.7,-12.75 60.4,-12.75 60.4,-12.783 23.495,-12.75 5.08,-12.75 0.985,-12.743 cw(c0.993,-8.75)
5V_USB_HS on F5 "TEMPLATE6" (solid, remove dead copper, pour order 133): 115.3,22.3 113,20 104.75,20 92.75,8 92.75,1.05 87.2,-4.5 66.3,-4.5 66.3,-6.98 66.57,-7.25 91.5,-7.25 117.5,18.75 117.5,22.3
5V on F5 "TEMPLATE13" (solid, remove dead copper, pour order 134): 124.5,32.05 83.25,32.05 83.25,5 79,0.75 60,0.75 57.9,2.85 30.9,2.85 26.5,7.25 12.3,7.25 9.2,10.35 9.2,46.75 11.6,49.15 21.5,49.15 23.5,51.15 23.5,52.55 23.1,52.95 22.2,52.95 20.3,51.05 10.8,51.05 7.6,47.85 7.6,8.75 13.35,3 26.5,3 31.25,-1.75 83.75,-1.75 87.8,2.3 87.8,21.05 94.75,28 118.4,28 118.4,18.15 116.75,16.5 116.75,4.75 118.249,4.75 124.5,10.997
5V_USB_FS on F5 "tpl5" (solid, remove dead copper, pour order 131): 115.8,24.75 115.8,22.55 114.8,22.55 112.7,20.45 104.75,20.45 92.5,8.2 92.5,1.2 87.05,-4.25 85.95,-4.25 85.95,-0.7 88.4,1.75 88.4,13.25 99.9,24.75
5V_ST_LINK on F5 "tpl4" (solid, remove dead copper, pour order 130): 92.25,19.25 93.9,19.25 99.9,25.25 115.75,25.25 115.75,27.25 95,27.25 92.25,24.5
1V8 on F5 "TEMPLATE17" (solid, remove dead copper, pour order 132): 33.15,9.5 33,9.65 30.46,9.65 26.43,13.68 26.43,20.3 25.45,21.28 14.68,21.28 13.98,20.58 13.98,11.38 15.23,10.13 25.02,10.13 29.65,5.5 70.25,5.5 72.8,2.95 72.8,2.85 73,2.65 73.4,2.65 73.6,2.85 73.6,6.65 70.75,9.5
GND on F6 "tpl2" (solid, remove dead copper, pour order 138): -3,-8.75 -3,63.25 cw(c1,63.25) 1,67.25 123,67.25 cw(c123,63.25) 127,63.25 127,-8.75 cw(c123,-8.75) 123,-12.75 75.7,-12.75 60.4,-12.75 60.4,-12.783 23.495,-12.75 5.08,-12.75 0.985,-12.743 cw(c0.993,-8.75)
E5V on F6 "TEMPLATE10" (solid, remove dead copper, pour order 137): 103,37 103,31.029 113.953,31.029 113.953,27.4 116.25,27.4 116.25,10.5 124,10.5 124,37
3V3_ST_LINK on F6 "TEMPLATE0" (solid, remove dead copper, pour order 136): 122.75,6.9 120.85,6.9 117.75,10 113.25,10 111.5,11.75 111.5,16.5 110.72,17.28 96.99,17.28 96.99,15.6 98,14.59 98,-2 99,-3 113.5,-3 114.75,-4.25 114.75,-11.75 115.25,-12.25 117.5,-12.25 118.25,-11.5 118.25,3.75 119.25,4.75 122.75,4.75
GND on Bottom "tpl1" (solid, remove dead copper, pour order 144): -3,-8.75 -3,63.25 cw(c1,63.25) 1,67.25 123,67.25 cw(c123,63.25) 127,63.25 127,-8.75 cw(c123,-8.75) 123,-12.75 75.7,-12.75 60.4,-12.75 60.4,-12.783 23.495,-12.75 5.08,-12.75 0.985,-12.743 cw(c0.993,-8.75)
3V3_ST_LINK on Bottom "TEMPLATE11" (solid, remove dead copper, pour order 143): 91.7,16.85 91.7,16.05 94.1,16.05 94.4,15.75 97.8,15.75 97.9,15.85 97.9,16.95 97.8,17.05 94.3,17.05 94.1,16.85
GND on F7 "TEMPLATE20" (solid, remove dead copper, pour order 140): 80.3,-13.65 90.17,-13.65 90.17,-1.6 79.52,-1.6 79.52,-4.577 80.3,-4.577
3V3 on F7 "TEMPLATE3" (solid, remove dead copper, pour order 142): -3,-8.75 -3,63.25 cw(c1,63.25) 1,67.25 123,67.25 cw(c123,63.25) 127,63.25 127,-8.75 cw(c123,-8.75) 123,-12.75 75.7,-12.75 60.4,-12.75 60.4,-12.783 23.495,-12.75 5.08,-12.75 0.985,-12.743 cw(c0.993,-8.75)
GND on F7 "TEMPLATE21" (solid, remove dead copper, pour order 139): 48.198,13.65 48.198,14.918 45.198,17.85 45.198,21.95 48.1,21.95 48.1,17.85 51,14.95 51,13.65
VDD on F7 "TEMPLATE4" (solid, remove dead copper, pour order 141): 27.5,29.25 29,29.25 29,26.75 42,26.75 42,28.25 45,28.25 45,44.25 49.5,44.25 49.5,47.25 27.5,47.25
GND on F2 "TEMPLATE2" (solid, remove dead copper, pour order 127): -3,-8.75 -3,63.25 cw(c1,63.25) 1,67.25 123,67.25 cw(c123,63.25) 127,63.25 127,-8.75 cw(c123,-8.75) 123,-12.75 75.7,-12.75 60.4,-12.75 60.4,-12.783 23.495,-12.75 5.08,-12.75 0.985,-12.743 cw(c0.993,-8.75)
GND on F3 "TEMPLATE24" (solid, remove dead copper, pour order 128): -3,-8.75 -3,63.25 cw(c1,63.25) 1,67.25 123,67.25 cw(c123,63.25) 127,63.25 127,-8.75 cw(c123,-8.75) 123,-12.75 75.7,-12.75 60.4,-12.75 60.4,-12.783 23.495,-12.75 5.08,-12.75 0.985,-12.743 cw(c0.993,-8.75)
GND on F4 "tpl0" (solid, remove dead copper, pour order 129): -3,-8.75 -3,63.25 cw(c1,63.25) 1,67.25 123,67.25 cw(c123,63.25) 127,63.25 127,-8.75 cw(c123,-8.75) 123,-12.75 75.7,-12.75 60.4,-12.75 60.4,-12.783 23.495,-12.75 5.08,-12.75 0.985,-12.743 cw(c0.993,-8.75)

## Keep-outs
Keep-Out Layer:
  the board outline again, w0.25

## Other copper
Top:
  pour cut-out: 13.97,67.209 13.97,50.927 -2.885,50.927 -3,63.25 cw(c0.953,63.287) 0.963,67.24
  pour cut-out: 94.62,7.036 94.62,1.75 94.846,1.75 94.846,7.036
  pour cut-out: 36.325,29.488 36.475,29.488 36.475,29.675 36.325,29.675
  pour cut-out: 18.062,33.975 18.062,34.125 17.875,34.125 17.875,33.975
  pour cut-out: 16.625,29.488 16.775,29.488 16.775,29.675 16.625,29.675
  pour cut-out: 11.338,30.925 11.338,30.775 11.525,30.775 11.525,30.925
  pour cut-out: 11.338,31.725 11.338,31.575 11.525,31.575 11.525,31.725
  pour cut-out: 11.338,32.525 11.338,32.375 11.525,32.375 11.525,32.525
  pour cut-out: 13.262,33.325 13.262,33.175 13.075,33.175 13.075,33.325
  pour cut-out: 12.625,41.012 12.637,41 12.95,41 12.95,40.7 13.125,40.525 13.25,40.525 13.25,40.375 13.025,40.375
  pour cut-out: 16.137,38.925 16.138,38.925 16.275,38.925 16.275,38.775 16.138,38.775
  pour cut-out: 13.262,36.525 13.262,36.375 13.175,36.375 13.175,36.525
  pour cut-out: 13.263,38.125 13.263,37.975 13.262,37.975 13.175,37.975 13.175,38.125
  pour cut-out: 16.15,35.725 16.15,35.575 16.225,35.575 16.225,35.725
  pour cut-out: 16.138,36.525 16.138,36.375 16.2,36.375 16.2,36.525
  pour cut-out: 99.45,67.157 99.45,60.2 112.15,60.2 112.15,67.207
  text "1" at 100.911,64.25 h1.5
  text ".Layer_Name" at 197.65,-112.032 h4
  text ".GTL" at 261.6,-112.075 h4
F2:
  pour cut-out: 41.325,60.45 cw(c41.307,59.807) 41.325,59.164 40.696,59.164 cw(c40.696,59.812) 40.575,60.45
  pour cut-out: 13.97,67.209 13.97,50.927 -2.885,50.927 -3,63.25 cw(c0.953,63.287) 0.963,67.24
  pour cut-out: 99.45,67.157 99.45,60.2 112.15,60.2 112.15,67.207
  text "2" at 103.7,64.417 h1.33
  text ".Layer_Name" at 197.65,-112.032 h4
  text ".G1" at 261.6,-112.075 h4
F3:
  pour cut-out: 41.325,60.45 cw(c41.307,59.807) 41.325,59.164 40.696,59.164 cw(c40.696,59.812) 40.575,60.45
  pour cut-out: 13.97,67.209 13.97,50.927 -2.885,50.927 -3,63.25 cw(c0.953,63.287) 0.963,67.24
  pour cut-out: 99.45,67.157 99.45,60.2 112.15,60.2 112.15,67.207
  text "3" at 106.8,64.417 h1.33
  text ".Layer_Name" at 197.65,-112.032 h4
  text ".G2" at 261.6,-112.075 h4
F4:
  pour cut-out: 41.325,60.45 cw(c41.307,59.807) 41.325,59.164 40.696,59.164 cw(c40.696,59.812) 40.575,60.45
  pour cut-out: 13.97,67.209 13.97,50.927 -2.885,50.927 -3,63.25 cw(c0.953,63.287) 0.963,67.24
  pour cut-out: 4.399,-8.655 4.398,-8.845 4.075,-8.845 4.075,-8.655
  pour cut-out: 1.095,-12.15 0.905,-12.149 0.905,-11.875 1.095,-11.875
  pour cut-out: -2.4,-8.845 -2.4,-8.655 -2.125,-8.655 -2.125,-8.845
  pour cut-out: 0.88,-5.351 1.07,-5.352 1.07,-5.65 0.88,-5.65
  pour cut-out: 122.905,66.649 123.095,66.648 123.095,66.35 122.905,66.35
  pour cut-out: 119.601,63.155 119.602,63.345 119.9,63.345 119.9,63.155
  pour cut-out: 123.12,59.85 122.93,59.851 122.93,60.125 123.12,60.125
  pour cut-out: 126.399,63.345 126.398,63.155 126.1,63.155 126.1,63.345
  pour cut-out: 126.399,-8.655 126.398,-8.845 126.1,-8.845 126.1,-8.655
  pour cut-out: 123.12,-12.15 122.93,-12.149 122.93,-11.875 123.12,-11.875
  pour cut-out: 119.601,-8.845 119.602,-8.655 119.9,-8.655 119.9,-8.845
  pour cut-out: 122.905,-5.351 123.095,-5.352 123.095,-5.65 122.905,-5.65
  pour cut-out: 121.8,-0.367 121.609,-0.366 121.609,-0.06 121.8,-0.06
  pour cut-out: 122.837,0.87 122.836,0.679 122.53,0.679 122.53,0.87
  pour cut-out: 120.563,0.67 120.564,0.861 120.87,0.861 120.87,0.67
  pour cut-out: 121.6,1.907 121.791,1.906 121.791,1.6 121.6,1.6
  pour cut-out: 99.45,67.157 99.45,60.2 112.15,60.2 112.15,67.207
  text "4" at 109.8,64.417 h1.33
  text ".Layer_Name" at 197.65,-112.032 h4
  text ".G3" at 261.6,-112.075 h4
F5:
  pour cut-out: 41.325,60.45 cw(c41.307,59.807) 41.325,59.164 40.696,59.164 cw(c40.696,59.812) 40.575,60.45
  pour cut-out: 13.97,67.209 13.97,50.927 -2.885,50.927 -3,63.25 cw(c0.953,63.287) 0.963,67.24
  pour cut-out: 99.45,67.157 99.45,60.2 112.15,60.2 112.15,67.207
  text "5" at 110.9,61.491 h1.33
  text ".Layer_Name" at 197.625,-112.032 h4
  text ".G4" at 261.575,-112.075 h4
F6:
  pour cut-out: 41.325,60.45 cw(c41.307,59.807) 41.325,59.164 40.696,59.164 cw(c40.696,59.812) 40.575,60.45
  pour cut-out: 13.97,67.209 13.97,50.927 -2.885,50.927 -3,63.25 cw(c0.953,63.287) 0.963,67.24
  pour cut-out: 99.45,67.157 99.45,60.2 112.15,60.2 112.15,67.207
  text "6" at 107.9,61.491 h1.33
  text ".Layer_Name" at 197.65,-112.007 h4
  text ".G5" at 261.6,-112.05 h4
F7:
  pour cut-out: 13.97,67.209 13.97,50.927 -2.885,50.927 -3,63.25 cw(c0.953,63.287) 0.963,67.24
  pour cut-out: 99.45,67.157 99.45,60.2 112.15,60.2 112.15,67.207
  text "7" at 104.8,61.491 h1.33
  text ".Layer_Name" at 197.65,-112.032 h4
  text ".G6" at 261.6,-112.075 h4
Bottom:
  pour cut-out: 41.325,60.45 cw(c41.307,59.807) 41.325,59.164 40.696,59.164 cw(c40.696,59.812) 40.575,60.45
  pour cut-out: 14,50.803 14,67.265 -2.974,67.265 -3,50.803
  pour cut-out: 19.1,15.75 19.25,15.6 19.75,15.625 19.875,15.75 19.85,16.225 19.7,16.375
  pour cut-out: 99.45,67.157 99.45,60.2 112.15,60.2 112.15,67.207
  pour cut-out: 46.2,27.5 47.721,27.5 47.79,27.569 47.79,26.669 46.222,26.669 46.216,26.675
  text "8" at 101.748,61.325 h1.5
  text ".Layer_Name" at 197.65,-112.032 h4
  text ".GBL" at 261.6,-112.075 h4

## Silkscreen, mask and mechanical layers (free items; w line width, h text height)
Top Silk:
  lines w0.2: 7.6,43.05 9.7,43.05 ; 8.7,42.35 8.7,42.95 ; 19.8,28.85 21.5,28.85 ; 20.1,43.85 22,43.85 ; 20.7,28.85 20.7,29.65 ; 21,42.95 21,43.85 ; 22.5,50.75 30.25,50.75 ; 25,21.95 23,21.95 22.8,22.15 22.8,31.65 24.2,33.05 25.2,33.05 25.5,33.35 25.5,39.25 25.7,39.45 ; 30.25,3.75 37.25,3.75 37.5,4 37.5,13 38.5,14 39.5,14 ; 30.25,45 30.25,50.75 ; 33,50.75 30.25,50.75 ; 39.5,14.55 39.5,14 ; 44.85,26.737 44.85,27.45 49.7,27.45 50.1,27.85 56.8,27.85 ; 47,14.55 47,14 39.5,14 ; 48.1,14.45 48.1,14.05 53.6,14.05 54.2,14.65 56.7,14.65 ; 58.9,14.95 58.9,15.85 ; 62.5,-5.458 64.7,-5.458 64.7,-7.45 ; 72.1,6.45 72.375,6.45 72.375,2.825 ; 74,21.25 74,22.65 74.2,22.85 ; 74.2,25.05 74.2,22.85 ; 74.8,22.85 74.2,22.85 ; 76,-6.25 76.4,-6.25 76.4,-5.55 ; 76.4,-2.15 76.4,-1.425 78.375,-1.425 78.375,3.9 ; -1,41 -1,61 5,61 5,41 -1,41
  lines w0.203: 22.5,37 22.5,34 22.75,33.75 ; 25.5,13.25 26,13.25 ; 25.5,15 25.5,12.25 25.75,12 ; 26,23.5 25.75,23.75 25.75,27.75 26,28 ; 26.163,21.39 26.522,21.75 33.645,21.75 ; 33.45,24.75 34.2,24.75 ; 33.7,21.75 33.7,24.725 34.2,24.75 ; 41.25,24.75 34.2,24.75 ; 98.5,13.5 103.25,13.5 103.5,13.25 104.25,13.25 ; 105.75,10.25 106,10 119.25,10 119.75,9.5 ; 114.25,5 114.75,4.5 114.75,-0.5
  text "EXT/RF" at 19.615,64.604 h1.6
  text "SPDIF" at 33.025,64.575 h1.6
  text "µSD" at 77.875,63.275 h1.6
  text "IN" at 33.1,63.075 h1.6
  text "CAMERA" at 68,59.575 h1.6
  text "User" at 119.425,57.175 h1.6
  text "D0" at 63.625,54.225 h1.5
  text "A5" at 111.8,54.175 h1.6
  text "D1" at 58.525,51.6 h1.5
  text "A4" at 106.7,51.575 h1.6
  text "SN" at 2.65,49.425 h2 r90
  text "D2" at 63.725,49.2 h1.5
  text "A3" at 111.7,49.175 h1.6
  text "D3" at 58.55,46.7 h1.5
  text "A2" at 106.7,46.375 h1.6
  text "D4" at 63.625,44.1 h1.5
  text "A1" at 111.7,44.075 h1.6
  text "D5" at 58.625,41.7 h1.5
  text "A0" at 106.8,41.475 h1.6
  text "D6" at 63.625,39 h1.5
  text "D7" at 58.625,36.5 h1.5
  text "Vin" at 111.725,36.375 h1.6
  text "Micro Right" at -1.15,34.525 h1.6 r90
  text "GND" at 105.925,33.775 h1.6
  text "Reset" at 119.575,32.825 h1.6
  text "D8" at 63.85,32.3 h1.5
  text "GND" at 112.925,30.525 h1.6 r90
  text "D9" at 58.625,29.8 h1.5
  text "5V" at 113.3,29.075 h1.6
  text "5V" at 106.95,28.675 h1.6
  text "5V" at 125.05,28.325 h1.6
  text "ext" at 113.3,28.075 h1.6
  text "D10" at 63.725,27.2 h1.5
  text "5V" at 113.3,26.575 h1.6
  text "5V" at 125.05,25.825 h1.6
  text "3V3" at 112.675,25.8 h1.6 r90
  text "link" at 113.3,25.325 h1.6
  text "D11" at 58.125,24.8 h1.5
  text "usb" at 113.3,24.325 h1.6
  text "NRST" at 105.825,23.825 h1.6
  text "5V" at 125.05,23.325 h1.6
  text "_fs" at 113.3,23.075 h1.6
  text "D12" at 63.55,22.3 h1.5
  text "usb" at 113.05,21.575 h1.6
  text "5V" at 125.05,20.825 h1.6
  text "_hs" at 113.05,20.325 h1.6
  text "IOref" at 112.675,20.3 h1.6 r90
  text "D13" at 58.125,19.7 h1.5
  text "nc" at 107.075,18.575 h1.6
  text "PWR" at 123.575,17.325 h1.6
  text "GND" at 63.35,17.175 h1.6
  text "GND" at 122.05,14.6 h1.6
  text "Micro Left" at -0.925,13.875 h1.6 r90
  text "AVDD" at 57.025,13.775 h1.6
  text "D14" at 63.65,12 h1.5
  text "5V" at 122.35,9.575 h1.6
  text "D15" at 58.05,9.5 h1.5
  text "3V3" at 123.55,5.375 h1.6
  text "IN" at 23.4,3.8 h1.6
  text "OUT" at 11.95,3.775 h1.6
  text "CLK" at 123.55,2.975 h1.6
  text "GND" at 123.45,0.375 h1.6
  text "ETHERNET" at 32.1,-1.525 h1.6
  text "DIO" at 123.55,-2.325 h1.6
  text "U18" at 83.377,-4.257 h1.5
  text "spk L" at 32.225,-6.025 h1.6
  text "spk R" at 28.6,-6.125 h1.6
  text "USB_HS" at 58.025,-6.225 h1.6
  text "U22" at 66.425,-7.439 h1.5
  text "USB ST-LINK" at 100.375,-11.575 h1.6 r90
  text "USB_FS" at 91.075,-12.35 h1.6 r90
  text ".GTO" at 261.6,-111.975 h4
  text "Silkscreen Top" at 197.8,-112.075 h4
Bottom Overlay:
  text "CAMERA" at 60.675,64.275 h1.6
  text "µSD" at 88.8,63.5 h1.6
  text "IN" at 40.6,63.375 h1.6
  text "SPDIF" at 44.25,63.375 h1.6
  text "C" at 81.65,62.975 h6
  text "E" at 30.101,62.425 h8
  text "F" at 96.2,62.25 h8
  text "EXT/RF" at 23.15,62.05 h1.6
  text "I" at 0.975,53.025 h10
  text "H" at 7.2,44.725 h15
  text "MB1191D" at 120.625,38 h3 r270
  text "Micro Right" at 4.325,33.875 h1.6
  text "J" at -2.075,22.725 h15 r270
  text "Micro Left" at 4.15,12.8 h1.6
  text "www.st.com/stm32f7-discovery" at 5.475,9.9 h3.2 r270
  text "G" at 4,6.575 h8
  text "ETHERNET" at 49.4,-9.725 h1.6
  text "spk R" at 28.475,-10.3 h1.6
  text "spk L" at 37.675,-10.325 h1.6
  text "USB_HS" at 69.975,-10.925 h1.6
  text "USB_FS" at 87.25,-10.925 h1.6
  text "IN" at 22.6,-11.325 h1.6
  text "OUT" at 12.075,-11.625 h1.6
  text "USB ST-LINK" at 109.775,-12 h1.6
  text ".GBO" at 261.525,-112.075 h4
  text "Silkscreen Bottom" at 197.725,-112.175 h4
Top Paste:
  text ".Layer_Name" at 197.65,-112.032 h4
  text ".GTP" at 261.6,-112.075 h4
Bottom Paste:
  text ".Layer_Name" at 197.775,-112.132 h4
  text ".GB+P" at 261.725,-112.175 h4
Top Mask:
  text "Top Solder" at 197.65,-112.075 h4
  text ".GTS" at 261.6,-112.075 h4
Bottom Solder:
  text ".Layer_Name" at 197.65,-112.075 h4
  text ".GBS" at 261.6,-112.075 h4
Mechanical Drawing:
  circle w0.254: c123,63.25 r1.625
  circle w0.254: c123,-8.75 r1.625
  circle w0.254: c1,-8.75 r1.625
  text "'.Layer_Name'" at 197.65,-112.007 h4
Board:
  the board outline again, w0.25
Assembly Top:
  circle w0.2: c1,-8.75 r4
  circle w0.2: c123,-8.75 r4
  circle w0.2: c123,63.25 r4
  lines w0.2: 59.2,-8.9 59.2,55.616 60.724,57.14 72.154,57.14 74.694,59.68 107.46,59.68 110,57.14 112.54,57.14 112.54,-8.9 59.2,-8.9
  text "'.Layer_Name'" at 197.75,-112.1 h4
Assembly Bottom:
  circle w0.254: c-0.067,-111.299 r1.3
  region: 0.407,-104.063 15.935,-104.063 16.629,-105.838 17.84,-107.063 19.237,-105.203 19.237,-103.552 18.094,-102.155 16.658,-101.777 0.407,-101.777
  region: 14.411,-112.392 25.167,-112.392 24.173,-109.9 16.316,-109.9 15.867,-109.14 13.658,-111.689
  lines w0.2: -124.2,-119.125 65.8,-119.125 ; -124.191,-114.125 38.808,-114.125 ; -124.192,-105.125 -14.242,-105.125 ; -124.191,-97.125 38.808,-97.125 ; -124.191,-93.668 38.808,-93.668 ; -124.191,-89.125 38.808,-89.125 38.808,-119.125 ; -112.092,-119.125 -112.092,-114.125 ; -106.192,-97.039 -106.192,-89.125 ; -104.192,-119.125 -104.192,-114.125 ; -91.192,-97.039 -91.192,-89.125 ; -74.192,-97.125 -74.192,-89.125 ; -54.192,-97.039 -54.192,-89.125 ; -44.192,-114.125 -44.192,-105.125 ; -14.192,-114.125 -14.192,-97.125
  lines w0.254: -0.106,-101.777 0.656,-104.063 ; 0.148,-101.777 0.91,-104.063 ; 0.314,-101.774 1.076,-104.06 ; 0.402,-104.063 -0.36,-101.777 16.404,-101.777 cw(c16.644,-104.418) 18.448,-106.362 15.381,-109.9 24.173,-109.9 ; 0.407,-104.063 4.1,-104.063 ; 3.046,-110.678 ccw(c5.595,-109.658) 5.844,-112.392 25.167,-112.392 20.82,-101.497 ; 3.045,-110.675 -1.254,-99.898 18.196,-99.898 ; 4.1,-103.809 6.989,-112.188 ; 4.328,-103.818 7.198,-112.138 ; 4.582,-103.818 7.452,-112.138 ; 4.836,-103.818 7.706,-112.138 ; 5.09,-103.818 7.96,-112.138 ; 5.344,-103.818 8.214,-112.138 ; 5.598,-103.818 8.468,-112.138 ; 5.736,-104.063 18.729,-104.063 ; 5.852,-103.818 8.722,-112.138 ; 6.106,-103.818 8.976,-112.138 ; 6.233,-103.818 9.103,-112.138 ; 6.436,-103.809 9.325,-112.188 ; 12.76,-110.029 18.065,-103.908 ; 12.76,-109.648 18.065,-103.527 ; 12.887,-110.41 18.192,-104.289 ; 12.887,-110.156 18.192,-104.035 ; 12.887,-109.267 18.192,-103.146 ; 12.941,-110.601 18.192,-104.543 ; 12.959,-108.839 18.264,-102.718 ; 13.014,-110.791 18.319,-104.67 ; 13.141,-110.918 18.446,-104.797 ; 13.268,-111.045 18.573,-104.924 ; 13.395,-111.172 18.7,-105.051 ; 13.522,-111.553 18.827,-105.432 ; 13.522,-111.299 18.827,-105.178 ; 13.658,-111.689 19.081,-105.432 ; 14.669,-112.3 cw(c15.402,-109.751) 13.598,-107.808 15.963,-105.079 ccw(c15.632,-104.617) 15.606,-104.05 ; 16.29,-108.921 ccw(c16.588,-109.378) 16.693,-109.913 ; 18.197,-99.898 cw(c18.433,-102.5) 20.86,-101.53
  lines w0.3: -129.2,-80.625 -124.2,-80.625 ; -129.2,-30.625 -124.2,-30.625 ; -129.2,19.375 -119.2,19.375 ; -129.2,69.375 -124.2,69.375 ; -129.2,119.375 -124.2,119.375 ; -74.2,-124.125 -74.2,-119.125 ; -74.2,157.875 -74.2,162.875 ; -24.2,-124.125 -24.2,-119.125 ; -24.2,157.875 -24.2,162.875 ; 6.989,-112.188 9.325,-112.188 ; 25.8,157.875 25.8,162.875 ; 65.8,-119.125 -124.2,-119.125 ; 75.8,-124.125 75.8,-114.125 ; 75.8,157.875 75.8,162.875 ; 125.8,-124.125 125.8,-119.125 ; 125.8,157.875 125.8,162.875 ; 175.8,-124.125 175.8,-119.125 ; 175.8,157.875 175.8,162.875 ; 225.8,-124.125 225.8,-119.125 ; 225.8,157.875 225.8,162.875 ; 275.8,-80.625 280.8,-80.625 ; 275.8,-30.625 280.8,-30.625 ; 275.8,69.375 280.8,69.375 ; 275.8,119.375 280.8,119.375 ; -124.2,-119.125 275.8,-119.125 275.8,157.875 -124.2,157.875 -124.2,-119.125 ; -129.2,-124.125 280.8,-124.125 280.8,162.875 -129.2,162.875 -129.2,-124.125 ; 25.8,-124.125 25.8,-119.125 25.8,-124.125
  text "8" at -98.367,159.543 h1.85
  text "7" at -48.367,159.543 h1.85
  text "6" at 1.633,159.543 h1.85
  text "5" at 51.633,159.543 h1.85
  text "4" at 101.633,159.543 h1.85
  text "3" at 151.633,159.543 h1.85
  text "2" at 201.634,159.543 h1.85
  text "1" at 251.217,159.543 h1.85
  text "A" at -125.867,145.543 h1.85
  text "A" at 279.134,145.543 h1.85
  text "B" at -125.867,95.543 h1.85
  text "B" at 279.134,95.543 h1.85
  text "C" at -125.867,45.543 h1.85
  text "C" at 279.134,45.543 h1.85
  text "D" at -125.867,-4.457 h1.85
  text "D" at 279.134,-4.457 h1.85
  text "E" at -125.867,-54.457 h1.85
  text "E" at 279.134,-54.457 h1.85
  text "19-11-2025" at -93.992,-92.125 h2
  text "CHECKED BY" at -109.192,-96.125 h2
  text "DATE" at -96.092,-96.125 h2
  text "PCB DESIGNER" at -76.192,-96.125 h2
  text "COMPAGNY" at -58.892,-96.125 h2
  text "DESCRIPTION" at 26.308,-96.125 h2
  text "Revision" at 36.808,-96.125 h2
  text "TITLE" at -16.292,-100.125 h2
  text "Carte STM32F746G-DISCOVERY" at -24.192,-103.125 h5
  text "F" at -125.867,-104.457 h1.85
  text "F" at 279.134,-104.457 h1.85
  text "LAYER" at -46.192,-108.025 h2
  text "GERBER" at -110.192,-108.125 h2
  text "REF." at -16.292,-108.125 h2
  text "'.Layer_Name'" at -53.8,-112.175 h3
  text "MB1191D" at -24.192,-112.175 h3
  text "Ce document est la propriété de STMICROELECTRONICS et ne peut être reproduit ou transmis sans son autorisation écrite." at 37.908,-116.025 h2.4
  text "A4" at -105.892,-118.125 h4.5
  text "This document is the property of STMICROELECTRONICS and shall not be reproduced nor transmitted without written approval." at 37.908,-118.425 h2.4
  text "8" at -98.367,-122.457 h1.85
  text "7" at -48.367,-122.457 h1.85
  text "6" at 1.633,-122.457 h1.85
  text "5" at 51.633,-122.457 h1.85
  text "4" at 101.633,-122.457 h1.85
  text "3" at 151.633,-122.457 h1.85
  text "2" at 201.634,-122.457 h1.85
  text "1" at 251.217,-122.457 h1.85
Drill Drawing:
  drawing of 332 lines, arcs and shapes, not listed
  text "Symbol" at 149.056,163.876 h3
  text "Hit Count" at 160.808,163.876 h3
  text "Finished Hole Size" at 174.867,163.876 h3
  text "Plated" at 200.036,163.876 h3
  text "Hole Length" at 210.352,163.876 h3
  text "Routed Path Length" at 231.947,163.876 h3
  text "Via/Pad" at 258.549,163.876 h3
  text "27" at 160.808,158.699 h2.5
  text "0.10mm (3.94mil)" at 174.867,158.699 h2.5
  text "PTH" at 200.036,158.699 h2.5
  text "-" at 210.352,158.699 h2.5
  text "-" at 231.947,158.699 h2.5
  text "Via" at 258.549,158.699 h2.5
  text "1041" at 160.808,153.522 h2.5
  text "0.15mm (5.91mil)" at 174.867,153.522 h2.5
  text "PTH" at 200.036,153.522 h2.5
  text "-" at 210.352,153.522 h2.5
  text "-" at 231.947,153.522 h2.5
  text "Via" at 258.549,153.522 h2.5
  text "1" at 160.808,148.344 h2.5
  text "0.65mm (25.59mil)" at 174.867,148.344 h2.5
  text "NPTH" at 200.036,148.344 h2.5
  text "-" at 210.352,148.344 h2.5
  text "-" at 231.947,148.344 h2.5
  text "Pad" at 258.549,148.344 h2.5
  text "4" at 160.808,143.167 h2.5
  text "0.65mm (25.59mil)" at 174.867,143.167 h2.5
  text "PTH" at 200.036,143.167 h2.5
  text "0.85mm (33.47mil)" at 210.352,143.167 h2.5
  text "0.20mm (7.87mil)" at 231.947,143.167 h2.5
  text "Pad" at 258.549,143.167 h2.5
  text "BE CAREFULL : CHECK CAPABILITIES MANUFACTURER PCB FOR HOLES AND PADS" at -8.95,140.5 h4
  text "1" at 160.808,137.989 h2.5
  text "0.70mm (27.56mil)" at 174.867,137.989 h2.5
  text "NPTH" at 200.036,137.989 h2.5
  text "-" at 210.352,137.989 h2.5
  text "-" at 231.947,137.989 h2.5
  text "Pad" at 258.549,137.989 h2.5
  text "4" at 160.808,132.812 h2.5
  text "0.80mm (31.50mil)" at 174.867,132.812 h2.5
  text "PTH" at 200.036,132.812 h2.5
  text "1.40mm (55.12mil)" at 210.352,132.812 h2.5
  text "0.60mm (23.62mil)" at 231.947,132.812 h2.5
  text "Pad" at 258.549,132.812 h2.5
  text "8" at 160.808,127.634 h2.5
  text "1.00mm (39.37mil)" at 174.867,127.634 h2.5
  text "NPTH" at 200.036,127.634 h2.5
  text "-" at 210.352,127.634 h2.5
  text "-" at 231.947,127.634 h2.5
  text "Pad" at 258.549,127.634 h2.5
  text "150" at -59.4,123.75 h2.54
  text "EDGED COUPLED" at -83.1,123.725 h2.54
  text "130" at -45.9,123.675 h2.54
  text "90 Ohms" at -33.7,123.55 h2.54
  text "10" at -16.625,123.45 h2.54
  text "2" at -3.85,123.35 h2.54
  text "9" at 160.808,122.457 h2.5
  text "1.00mm (39.37mil)" at 174.867,122.457 h2.5
  text "PTH" at 200.036,122.457 h2.5
  text "-" at 210.352,122.457 h2.5
  text "-" at 231.947,122.457 h2.5
  text "Pad" at 258.549,122.457 h2.5
  text "EDGED COUPLED" at -83.203,121.2 h2.54
  text "125" at -59.45,121.15 h2.54
  text "165" at -45.95,121.075 h2.54
  text "100 Ohms" at -33.85,120.95 h2.54
  text "10" at -16.675,120.85 h2.54
  text "2" at -3.9,120.75 h2.54
  text "1" at 160.808,117.28 h2.5
  text "1.00mm (39.37mil)" at 174.867,117.28 h2.5
  text "PTH" at 200.036,117.28 h2.5
  text "1.60mm (62.99mil)" at 210.352,117.28 h2.5
  text "1.60mm (62.99mil)" at 231.947,117.28 h2.5
  text "Pad" at 258.549,117.28 h2.5
  text "SINGLE ENDED" at -81.575,112.75 h2.54
  text "120" at -59.497,112.7 h2.54
  text "50 Ohms" at -33.625,112.5 h2.54
  text "10" at -16.725,112.5 h2.54
  text "3, 5" at -3.95,112.4 h2.54
  text "2" at 160.808,112.102 h2.5
  text "1.20mm (47.24mil)" at 174.867,112.102 h2.5
  text "NPTH" at 200.036,112.102 h2.5
  text "-" at 210.352,112.102 h2.5
  text "-" at 231.947,112.102 h2.5
  text "Pad" at 258.549,112.102 h2.5
  text "SINGLE ENDED" at -81.676,109.825 h2.54
  text "120" at -59.598,109.775 h2.54
  text "50 Ohms" at -33.726,109.575 h2.54
  text "10" at -16.826,109.575 h2.54
  text "4, 6" at -4.051,109.475 h2.54
  text "1" at 160.808,106.925 h2.5
  text "1.73mm (68.11mil)" at 174.867,106.925 h2.5
  text "NPTH" at 200.036,106.925 h2.5
  text "-" at 210.352,106.925 h2.5
  text "-" at 231.947,106.925 h2.5
  text "Pad" at 258.549,106.925 h2.5
  text "SINGLE ENDED" at -81.576,106.775 h2.54
  text "120" at -59.498,106.725 h2.54
  text "50 Ohms" at -33.626,106.525 h2.54
  text "10" at -16.726,106.525 h2.54
  text "5, 7" at -3.951,106.425 h2.54
  text "4" at 160.808,101.747 h2.5
  text "2.00mm (78.74mil)" at 174.867,101.747 h2.5
  text "NPTH" at 200.036,101.747 h2.5
  text "-" at 210.352,101.747 h2.5
  text "-" at 231.947,101.747 h2.5
  text "Pad" at 258.549,101.747 h2.5
  text "SINGLE ENDED" at -81.626,99.975 h2.54
  text "120" at -59.548,99.925 h2.54
  text "50 Ohms" at -33.676,99.725 h2.54
  text "10" at -16.776,99.725 h2.54
  text "7" at -4.001,99.625 h2.54
  text "3" at 160.808,96.57 h2.5
  text "3.25mm (127.95mil)" at 174.867,96.57 h2.5
  text "NPTH" at 200.036,96.57 h2.5
  text "-" at 210.352,96.57 h2.5
  text "-" at 231.947,96.57 h2.5
  text "Pad" at 258.549,96.57 h2.5
  text "3" at 160.808,91.392 h2.5
  text "3.25mm (127.95mil)" at 174.867,91.392 h2.5
  text "PTH" at 200.036,91.392 h2.5
  text "-" at 210.352,91.392 h2.5
  text "-" at 231.947,91.392 h2.5
  text "Pad" at 258.549,91.392 h2.5
  text "1109 Total" at 160.808,86.215 h2.5
  text "Slot definitions :" at 149.056,82.591 h2.5
  text "Routed Path Length" at 166.118,82.591 h2.5
  text "= Calculated from tool start centre position to tool end centre position." at 187.254,82.591 h2.5
  text "Hole Length" at 166.118,80.52 h2.5
  text "= Routed Path Length + Tool Size = Slot length as defined in the PCB layout" at 179.407,80.52 h2.5
  text "Layer" at 157.115,66.24 h3
  text "Name" at 169.673,66.24 h3
  text "Material" at 193.96,66.24 h3
  text "Thickness" at 215.904,66.24 h3
  text "1" at 157.115,60.24 h3
  text "Top Silk" at 169.673,60.24 h3
  text "2" at 157.115,54.24 h3
  text "Top Mask" at 169.673,54.24 h3
  text "Solder Resist" at 193.96,54.24 h3
  text "0.015mm" at 215.904,54.24 h3
  text "3" at 157.115,48.24 h3
  text "TOP" at 169.673,48.24 h3
  text "Copper" at 193.96,48.24 h3
  text "0.055mm" at 215.904,48.24 h3
  text "4" at 157.115,42.24 h3
  text "Dielectric 1" at 169.673,42.24 h3
  text "Prepreg 2116" at 193.96,42.24 h3
  text "0.108mm" at 215.904,42.24 h3
  text "5" at 157.115,36.24 h3
  text "F2" at 169.673,36.24 h3
  text "Copper" at 193.96,36.24 h3
  text "0.033mm" at 215.904,36.24 h3
  text "6" at 157.115,30.24 h3
  text "Dielectric2" at 169.673,30.24 h3
  text "Core 125" at 193.96,30.24 h3
  text "0.125mm" at 215.904,30.24 h3
  text "7" at 157.115,24.24 h3
  text "F3" at 169.673,24.24 h3
  text "Copper" at 193.96,24.24 h3
  text "0.033mm" at 215.904,24.24 h3
  text "8" at 157.115,18.24 h3
  text "Dielectric3" at 169.673,18.24 h3
  text "Prepreg 2116" at 193.96,18.24 h3
  text "0.108mm" at 215.904,18.24 h3
  text "9" at 157.115,12.24 h3
  text "F4" at 169.673,12.24 h3
  text "Copper" at 193.96,12.24 h3
  text "0.033mm" at 215.904,12.24 h3
  text "10" at 157.115,6.24 h3
  text "Dielectric4" at 169.673,6.24 h3
  text "Core 125" at 193.96,6.24 h3
  text "0.125mm" at 215.904,6.24 h3
  text "11" at 157.115,0.24 h3
  text "F5" at 169.673,0.24 h3
  text "Copper" at 193.96,0.24 h3
  text "0.033mm" at 215.904,0.24 h3
  text "12" at 157.115,-5.76 h3
  text "Dielectric5" at 169.673,-5.76 h3
  text "Prepreg 2116" at 193.96,-5.76 h3
  text "0.108mm" at 215.904,-5.76 h3
  text "13" at 157.115,-11.76 h3
  text "F6" at 169.673,-11.76 h3
  text "Copper" at 193.96,-11.76 h3
  text "0.033mm" at 215.904,-11.76 h3
  text "14" at 157.115,-17.76 h3
  text "Dielectric6" at 169.673,-17.76 h3
  text "Core 125" at 193.96,-17.76 h3
  text "0.125mm" at 215.904,-17.76 h3
  text "15" at 157.115,-23.76 h3
  text "F7" at 169.673,-23.76 h3
  text "Copper" at 193.96,-23.76 h3
  text "0.033mm" at 215.904,-23.76 h3
  text "PCB SPECIFICATIONS:" at -1.81,-24.784 h3
  text "A.   MATERIAL :" at -1.81,-28.784 h3
  text "FR-4" at 36.69,-28.784 h3
  text "TG-170" at 53.19,-28.784 h3
  text "X  TG-150" at 71.44,-28.784 h3
  text "TG-140" at 87.44,-28.784 h3
  text "16" at 157.115,-29.76 h3
  text "Dielectric7" at 169.673,-29.76 h3
  text "Prepreg 2116" at 193.96,-29.76 h3
  text "0.108mm" at 215.904,-29.76 h3
  text "B.   MATERIAL FAMILY :" at -1.81,-31.784 h3
  text "N/A" at 36.69,-31.784 h3
  text "C.   SOLDERMASK COLOR :" at -1.81,-34.784 h3
  text "GREEN" at 36.69,-34.784 h3
  text "X  BLUE" at 53.19,-34.784 h3
  text "RED" at 71.44,-34.784 h3
  text "BLACK" at 87.44,-34.784 h3
  text "17" at 157.115,-35.76 h3
  text "Bottom" at 169.673,-35.76 h3
  text "Copper" at 193.96,-35.76 h3
  text "0.055mm" at 215.904,-35.76 h3
  text "X  WHITE" at 36.7,-37.75 h3
  text "D.   SILKSCREEN COLOR :" at -1.81,-37.784 h3
  text "YELLOW" at 53.19,-37.784 h3
  text "BLACK" at 71.44,-37.784 h3
  text "E.   SURFACE FINISH :" at -1.81,-40.784 h3
  text "X  ENIG" at 36.69,-40.784 h3
  text "IMMERSION SILVER" at 53.19,-40.784 h3
  text "IMMERSION TIN" at 87.44,-40.784 h3
  text "18" at 157.115,-41.76 h3
  text "Bottom Solder" at 169.673,-41.76 h3
  text "Solder Resist" at 193.96,-41.76 h3
  text "0.015mm" at 215.904,-41.76 h3
  text "HASL" at 36.69,-43.784 h3
  text "HASL (PB-FREE)" at 53.19,-43.784 h3
  text "GOLDEN FINGER" at 87.44,-43.784 h3
  text "F.   IMPEDANCE CONTROL :" at -1.81,-46.784 h3
  text "NO" at 36.69,-46.784 h3
  text "X  YES  (SEE IMPEDANCE TABLE FOR DETAIL INFORMATION)" at 53.225,-46.975 h3
  text "19" at 157.115,-47.76 h3
  text "Bottom Overlay" at 169.673,-47.76 h3
  text "G.   THROUGH VIA :" at -1.81,-49.784 h3
  text "PLUG THE VIAS WHICH ARE COVERED WITH SOLDERMASK ONE OR TWO SIDE." at 36.69,-49.784 h3
  text "PLUG MATERIAL :" at 36.69,-52.784 h3
  text "X  SOLDERMASK" at 62.19,-52.784 h3
  text "NON-CONDUCTIVE EPOXY." at 87.44,-52.784 h3
  text "H.   STACK-UP :" at -1.81,-55.784 h3
  text "SEE LAYER STACK-UP SEQUENCE FOR OVERALL THICKNESS." at 36.69,-55.784 h3
  text "Drill Drawing" at 197.65,-112.032 h4
Template Top:
  circle w0.254: c151.676,-111.299 r1.3
  region: 151.201,-104.063 135.674,-104.063 134.98,-105.838 133.769,-107.063 132.372,-105.203 132.372,-103.552 133.515,-102.155 134.951,-101.777 151.201,-101.777
  region: 137.198,-112.392 126.442,-112.392 127.435,-109.9 135.293,-109.9 135.742,-109.14 137.95,-111.689
  lines w0.2: 85.8,-119.125 275.8,-119.125 ; 112.8,-119.125 112.8,-89.125 275.8,-89.125 ; 112.8,-114.125 275.8,-114.125 ; 112.8,-97.125 275.8,-97.125 ; 112.8,-93.668 275.8,-93.668 ; 123.3,-97.125 123.3,-89.125 ; 151.3,-97.125 151.3,-89.125 ; 165.8,-114.125 165.8,-97.125 ; 165.85,-105.125 275.8,-105.125 ; 195.8,-114.125 195.8,-105.125 ; 205.8,-97.039 205.8,-89.125 ; 225.8,-97.125 225.8,-89.125 ; 242.8,-97.039 242.8,-89.125 ; 255.8,-119.125 255.8,-114.125 ; 257.8,-97.039 257.8,-89.125 ; 263.7,-119.125 263.7,-114.125
  lines w0.254: 127.435,-109.9 136.227,-109.9 133.161,-106.362 cw(c134.965,-104.418) 135.205,-101.777 151.969,-101.777 151.207,-104.063 ; 130.749,-101.53 cw(c133.175,-102.5) 133.412,-99.898 ; 130.788,-101.497 126.442,-112.392 145.764,-112.392 ccw(c146.013,-109.658) 148.562,-110.678 ; 132.528,-105.432 137.95,-111.689 ; 132.782,-105.432 138.087,-111.553 ; 132.782,-105.178 138.087,-111.299 ; 132.88,-104.063 145.873,-104.063 ; 132.909,-105.051 138.214,-111.172 ; 133.036,-104.924 138.341,-111.045 ; 133.163,-104.797 138.468,-110.918 ; 133.29,-104.67 138.595,-110.791 ; 133.345,-102.718 138.65,-108.839 ; 133.413,-99.898 152.863,-99.898 148.563,-110.675 ; 133.417,-104.543 138.667,-110.601 ; 133.417,-104.289 138.722,-110.41 ; 133.417,-104.035 138.722,-110.156 ; 133.417,-103.146 138.722,-109.267 ; 133.544,-103.908 138.849,-110.029 ; 133.544,-103.527 138.849,-109.648 ; 134.916,-109.913 ccw(c135.021,-109.378) 135.318,-108.921 ; 136.002,-104.05 ccw(c135.976,-104.617) 135.646,-105.079 138.011,-107.808 cw(c136.207,-109.751) 136.94,-112.3 ; 142.283,-112.188 145.173,-103.809 ; 142.506,-112.138 145.375,-103.818 ; 142.633,-112.138 145.502,-103.818 ; 142.887,-112.138 145.756,-103.818 ; 143.141,-112.138 146.01,-103.818 ; 143.395,-112.138 146.264,-103.818 ; 143.649,-112.138 146.518,-103.818 ; 143.903,-112.138 146.772,-103.818 ; 144.157,-112.138 147.026,-103.818 ; 144.411,-112.138 147.28,-103.818 ; 144.619,-112.188 147.509,-103.809 ; 147.509,-104.063 151.201,-104.063 ; 150.533,-104.06 151.295,-101.774 ; 150.699,-104.063 151.461,-101.777 ; 150.953,-104.063 151.715,-101.777
  lines w0.3: -129.2,-80.625 -124.2,-80.625 ; -129.2,-30.625 -124.2,-30.625 ; -129.2,19.375 -119.2,19.375 ; -129.2,69.375 -124.2,69.375 ; -129.2,119.375 -124.2,119.375 ; -74.2,-124.125 -74.2,-119.125 ; -74.2,157.875 -74.2,162.875 ; -24.2,-124.125 -24.2,-119.125 ; -24.2,157.875 -24.2,162.875 ; 25.8,-124.125 25.8,-119.125 ; 25.8,157.875 25.8,162.875 ; 75.8,-124.125 75.8,-114.125 ; 75.8,157.875 75.8,162.875 ; 85.8,-119.125 275.8,-119.125 ; 125.8,157.875 125.8,162.875 ; 142.283,-112.188 144.619,-112.188 ; 175.8,-124.125 175.8,-119.125 ; 175.8,157.875 175.8,162.875 ; 225.8,-124.125 225.8,-119.125 ; 225.8,157.875 225.8,162.875 ; 275.8,-80.625 280.8,-80.625 ; 275.8,-30.625 280.8,-30.625 ; 275.8,69.375 280.8,69.375 ; 275.8,119.375 280.8,119.375 ; 275.8,-119.125 275.8,157.875 -124.2,157.875 -124.2,-119.125 275.8,-119.125 ; -129.2,-124.125 -129.2,162.875 280.8,162.875 280.8,-124.125 -129.2,-124.125 ; 125.8,-124.125 125.8,-119.125 125.8,-124.125
  text "1" at -99.617,159.543 h1.85
  text "2" at -50.033,159.543 h1.85
  text "3" at -0.033,159.543 h1.85
  text "4" at 49.967,159.543 h1.85
  text "5" at 99.967,159.543 h1.85
  text "6" at 149.967,159.543 h1.85
  text "7" at 199.967,159.543 h1.85
  text "8" at 249.967,159.543 h1.85
  text "A" at -127.533,145.543 h1.85
  text "A" at 277.467,145.543 h1.85
  text "B" at -127.533,95.543 h1.85
  text "B" at 277.467,95.543 h1.85
  text "C" at -127.533,45.543 h1.85
  text "C" at 277.467,45.543 h1.85
  text "D" at -127.533,-4.457 h1.85
  text "D" at 277.467,-4.457 h1.85
  text "E" at -127.533,-54.457 h1.85
  text "E" at 277.467,-54.457 h1.85
  text "19-11-2025" at 245.6,-92.125 h2
  text "Revision" at 114.8,-96.125 h2
  text "DESCRIPTION" at 125.3,-96.125 h2
  text "COMPAGNY" at 210.5,-96.125 h2
  text "PCB DESIGNER" at 227.8,-96.125 h2
  text "DATE" at 247.7,-96.125 h2
  text "CHECKED BY" at 260.8,-96.125 h2
  text "TITLE" at 167.9,-100.125 h2
  text "Carte STM32F746G-DISCOVERY" at 175.8,-103.125 h5
  text "F" at -127.533,-104.457 h1.85
  text "F" at 277.467,-104.457 h1.85
  text "LAYER" at 197.8,-108.025 h2
  text "REF." at 167.9,-108.125 h2
  text "GERBER" at 261.8,-108.125 h2
  text "MB1191D" at 175.8,-112.125 h3
  text "Ce document est la propriété de STMICROELECTRONICS et ne peut être reproduit ou transmis sans son autorisation écrite." at 113.7,-116.025 h2.4
  text "A4" at 257.5,-118.125 h4.5
  text "This document is the property of STMICROELECTRONICS and shall not be reproduced nor transmitted without written approval." at 113.7,-118.425 h2.4
  text "1" at -99.617,-122.457 h1.85
  text "2" at -50.033,-122.457 h1.85
  text "3" at -0.033,-122.457 h1.85
  text "4" at 49.967,-122.457 h1.85
  text "5" at 99.967,-122.457 h1.85
  text "6" at 149.967,-122.457 h1.85
  text "7" at 199.967,-122.457 h1.85
  text "8" at 249.967,-122.457 h1.85

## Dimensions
1,-12.75 to 1,67.25 on Mechanical Drawing
1,63.25 to 1,67.25 on Mechanical Drawing
1,63.25 to 1,-8.75 on Mechanical Drawing
127,63.25 to -3,63.25 on Mechanical Drawing
1,63.25 to 123,63.25 on Mechanical Drawing
-3,63.25 to 1,63.25 on Mechanical Drawing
